VERSION 5.8 ;
BUSBITCHARS "[]" ;
DIVIDERCHAR "/" ;
UNITS
    DATABASE MICRONS 1000 ;
END UNITS

VIA transformer_layer_block_via2_3_1600_480_1_5_320_320
  VIARULE M1M2_PR ;
  CUTSIZE 0.15 0.15 ;
  LAYERS met1 via met2 ;
  CUTSPACING 0.17 0.17 ;
  ENCLOSURE 0.085 0.165 0.055 0.085 ;
  ROWCOL 1 5 ;
END transformer_layer_block_via2_3_1600_480_1_5_320_320

VIA transformer_layer_block_via3_4_1600_480_1_4_400_400
  VIARULE M2M3_PR ;
  CUTSIZE 0.2 0.2 ;
  LAYERS met2 via2 met3 ;
  CUTSPACING 0.2 0.2 ;
  ENCLOSURE 0.04 0.085 0.065 0.065 ;
  ROWCOL 1 4 ;
END transformer_layer_block_via3_4_1600_480_1_4_400_400

VIA transformer_layer_block_via4_5_1600_480_1_4_400_400
  VIARULE M3M4_PR ;
  CUTSIZE 0.2 0.2 ;
  LAYERS met3 via3 met4 ;
  CUTSPACING 0.2 0.2 ;
  ENCLOSURE 0.09 0.06 0.1 0.065 ;
  ROWCOL 1 4 ;
END transformer_layer_block_via4_5_1600_480_1_4_400_400

VIA transformer_layer_block_via5_6_1600_1600_1_1_1600_1600
  VIARULE M4M5_PR ;
  CUTSIZE 0.8 0.8 ;
  LAYERS met4 via4 met5 ;
  CUTSPACING 0.8 0.8 ;
  ENCLOSURE 0.4 0.19 0.31 0.4 ;
END transformer_layer_block_via5_6_1600_1600_1_1_1600_1600

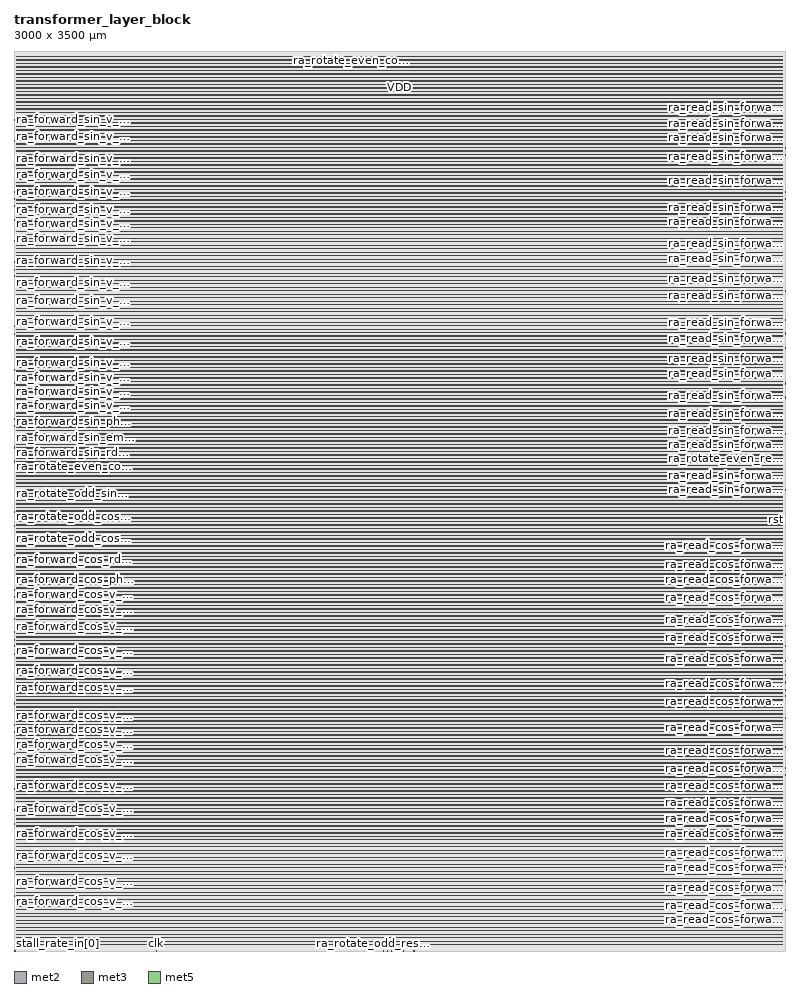
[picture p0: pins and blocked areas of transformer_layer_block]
MACRO transformer_layer_block
  FOREIGN transformer_layer_block 0 0 ;
  CLASS BLOCK ;
  SIZE 3000 BY 3500 ;
  PIN clk
    DIRECTION INPUT ;
    USE SIGNAL ;
    PORT
      LAYER met2 ;
        RECT  554 0 554.14 0.485 ;
    END
  END clk
  PIN ra_forward_cos_empty_out
    DIRECTION OUTPUT ;
    USE SIGNAL ;
    PORT
      LAYER met3 ;
        RECT  0 1504.35 0.8 1504.65 ;
    END
  END ra_forward_cos_empty_out
  PIN ra_forward_cos_phase_in[0]
    DIRECTION INPUT ;
    USE SIGNAL ;
    PORT
      LAYER met3 ;
        RECT  0 1443.15 0.8 1443.45 ;
    END
  END ra_forward_cos_phase_in[0]
  PIN ra_forward_cos_phase_in[1]
    DIRECTION INPUT ;
    USE SIGNAL ;
    PORT
      LAYER met3 ;
        RECT  0 1444.51 0.8 1444.81 ;
    END
  END ra_forward_cos_phase_in[1]
  PIN ra_forward_cos_rden_in
    DIRECTION INPUT ;
    USE SIGNAL ;
    PORT
      LAYER met3 ;
        RECT  0 1520.67 0.8 1520.97 ;
    END
  END ra_forward_cos_rden_in
  PIN ra_forward_cos_rdy_out
    DIRECTION OUTPUT ;
    USE SIGNAL ;
    PORT
      LAYER met3 ;
        RECT  0 1496.19 0.8 1496.49 ;
    END
  END ra_forward_cos_rdy_out
  PIN ra_forward_cos_v_in[0]
    DIRECTION INPUT ;
    USE SIGNAL ;
    PORT
      LAYER met3 ;
        RECT  0 288.51 0.8 288.81 ;
    END
  END ra_forward_cos_v_in[0]
  PIN ra_forward_cos_v_in[100]
    DIRECTION INPUT ;
    USE SIGNAL ;
    PORT
      LAYER met3 ;
        RECT  0 916.83 0.8 917.13 ;
    END
  END ra_forward_cos_v_in[100]
  PIN ra_forward_cos_v_in[101]
    DIRECTION INPUT ;
    USE SIGNAL ;
    PORT
      LAYER met3 ;
        RECT  0 861.07 0.8 861.37 ;
    END
  END ra_forward_cos_v_in[101]
  PIN ra_forward_cos_v_in[102]
    DIRECTION INPUT ;
    USE SIGNAL ;
    PORT
      LAYER met3 ;
        RECT  0 1028.35 0.8 1028.65 ;
    END
  END ra_forward_cos_v_in[102]
  PIN ra_forward_cos_v_in[103]
    DIRECTION INPUT ;
    USE SIGNAL ;
    PORT
      LAYER met3 ;
        RECT  0 1167.07 0.8 1167.37 ;
    END
  END ra_forward_cos_v_in[103]
  PIN ra_forward_cos_v_in[104]
    DIRECTION INPUT ;
    USE SIGNAL ;
    PORT
      LAYER met3 ;
        RECT  0 1417.31 0.8 1417.61 ;
    END
  END ra_forward_cos_v_in[104]
  PIN ra_forward_cos_v_in[105]
    DIRECTION INPUT ;
    USE SIGNAL ;
    PORT
      LAYER met3 ;
        RECT  0 454.43 0.8 454.73 ;
    END
  END ra_forward_cos_v_in[105]
  PIN ra_forward_cos_v_in[106]
    DIRECTION INPUT ;
    USE SIGNAL ;
    PORT
      LAYER met3 ;
        RECT  0 397.31 0.8 397.61 ;
    END
  END ra_forward_cos_v_in[106]
  PIN ra_forward_cos_v_in[107]
    DIRECTION INPUT ;
    USE SIGNAL ;
    PORT
      LAYER met3 ;
        RECT  0 1024.27 0.8 1024.57 ;
    END
  END ra_forward_cos_v_in[107]
  PIN ra_forward_cos_v_in[108]
    DIRECTION INPUT ;
    USE SIGNAL ;
    PORT
      LAYER met3 ;
        RECT  0 224.59 0.8 224.89 ;
    END
  END ra_forward_cos_v_in[108]
  PIN ra_forward_cos_v_in[109]
    DIRECTION INPUT ;
    USE SIGNAL ;
    PORT
      LAYER met3 ;
        RECT  0 923.63 0.8 923.93 ;
    END
  END ra_forward_cos_v_in[109]
  PIN ra_forward_cos_v_in[10]
    DIRECTION INPUT ;
    USE SIGNAL ;
    PORT
      LAYER met3 ;
        RECT  0 270.83 0.8 271.13 ;
    END
  END ra_forward_cos_v_in[10]
  PIN ra_forward_cos_v_in[110]
    DIRECTION INPUT ;
    USE SIGNAL ;
    PORT
      LAYER met3 ;
        RECT  0 1328.91 0.8 1329.21 ;
    END
  END ra_forward_cos_v_in[110]
  PIN ra_forward_cos_v_in[111]
    DIRECTION INPUT ;
    USE SIGNAL ;
    PORT
      LAYER met3 ;
        RECT  0 832.51 0.8 832.81 ;
    END
  END ra_forward_cos_v_in[111]
  PIN ra_forward_cos_v_in[112]
    DIRECTION INPUT ;
    USE SIGNAL ;
    PORT
      LAYER met3 ;
        RECT  0 971.23 0.8 971.53 ;
    END
  END ra_forward_cos_v_in[112]
  PIN ra_forward_cos_v_in[113]
    DIRECTION INPUT ;
    USE SIGNAL ;
    PORT
      LAYER met3 ;
        RECT  0 642.11 0.8 642.41 ;
    END
  END ra_forward_cos_v_in[113]
  PIN ra_forward_cos_v_in[114]
    DIRECTION INPUT ;
    USE SIGNAL ;
    PORT
      LAYER met3 ;
        RECT  0 648.91 0.8 649.21 ;
    END
  END ra_forward_cos_v_in[114]
  PIN ra_forward_cos_v_in[115]
    DIRECTION INPUT ;
    USE SIGNAL ;
    PORT
      LAYER met3 ;
        RECT  0 1262.27 0.8 1262.57 ;
    END
  END ra_forward_cos_v_in[115]
  PIN ra_forward_cos_v_in[116]
    DIRECTION INPUT ;
    USE SIGNAL ;
    PORT
      LAYER met3 ;
        RECT  0 871.95 0.8 872.25 ;
    END
  END ra_forward_cos_v_in[116]
  PIN ra_forward_cos_v_in[117]
    DIRECTION INPUT ;
    USE SIGNAL ;
    PORT
      LAYER met3 ;
        RECT  0 201.47 0.8 201.77 ;
    END
  END ra_forward_cos_v_in[117]
  PIN ra_forward_cos_v_in[118]
    DIRECTION INPUT ;
    USE SIGNAL ;
    PORT
      LAYER met3 ;
        RECT  0 534.67 0.8 534.97 ;
    END
  END ra_forward_cos_v_in[118]
  PIN ra_forward_cos_v_in[119]
    DIRECTION INPUT ;
    USE SIGNAL ;
    PORT
      LAYER met3 ;
        RECT  0 497.95 0.8 498.25 ;
    END
  END ra_forward_cos_v_in[119]
  PIN ra_forward_cos_v_in[11]
    DIRECTION INPUT ;
    USE SIGNAL ;
    PORT
      LAYER met3 ;
        RECT  0 640.75 0.8 641.05 ;
    END
  END ra_forward_cos_v_in[11]
  PIN ra_forward_cos_v_in[120]
    DIRECTION INPUT ;
    USE SIGNAL ;
    PORT
      LAYER met3 ;
        RECT  0 413.63 0.8 413.93 ;
    END
  END ra_forward_cos_v_in[120]
  PIN ra_forward_cos_v_in[121]
    DIRECTION INPUT ;
    USE SIGNAL ;
    PORT
      LAYER met3 ;
        RECT  0 371.47 0.8 371.77 ;
    END
  END ra_forward_cos_v_in[121]
  PIN ra_forward_cos_v_in[122]
    DIRECTION INPUT ;
    USE SIGNAL ;
    PORT
      LAYER met3 ;
        RECT  0 296.67 0.8 296.97 ;
    END
  END ra_forward_cos_v_in[122]
  PIN ra_forward_cos_v_in[123]
    DIRECTION INPUT ;
    USE SIGNAL ;
    PORT
      LAYER met3 ;
        RECT  0 269.47 0.8 269.77 ;
    END
  END ra_forward_cos_v_in[123]
  PIN ra_forward_cos_v_in[124]
    DIRECTION INPUT ;
    USE SIGNAL ;
    PORT
      LAYER met3 ;
        RECT  0 900.51 0.8 900.81 ;
    END
  END ra_forward_cos_v_in[124]
  PIN ra_forward_cos_v_in[125]
    DIRECTION INPUT ;
    USE SIGNAL ;
    PORT
      LAYER met3 ;
        RECT  0 907.31 0.8 907.61 ;
    END
  END ra_forward_cos_v_in[125]
  PIN ra_forward_cos_v_in[126]
    DIRECTION INPUT ;
    USE SIGNAL ;
    PORT
      LAYER met3 ;
        RECT  0 878.75 0.8 879.05 ;
    END
  END ra_forward_cos_v_in[126]
  PIN ra_forward_cos_v_in[127]
    DIRECTION INPUT ;
    USE SIGNAL ;
    PORT
      LAYER met3 ;
        RECT  0 1418.67 0.8 1418.97 ;
    END
  END ra_forward_cos_v_in[127]
  PIN ra_forward_cos_v_in[128]
    DIRECTION INPUT ;
    USE SIGNAL ;
    PORT
      LAYER met3 ;
        RECT  0 1290.83 0.8 1291.13 ;
    END
  END ra_forward_cos_v_in[128]
  PIN ra_forward_cos_v_in[129]
    DIRECTION INPUT ;
    USE SIGNAL ;
    PORT
      LAYER met3 ;
        RECT  0 1002.51 0.8 1002.81 ;
    END
  END ra_forward_cos_v_in[129]
  PIN ra_forward_cos_v_in[12]
    DIRECTION INPUT ;
    USE SIGNAL ;
    PORT
      LAYER met3 ;
        RECT  0 284.43 0.8 284.73 ;
    END
  END ra_forward_cos_v_in[12]
  PIN ra_forward_cos_v_in[130]
    DIRECTION INPUT ;
    USE SIGNAL ;
    PORT
      LAYER met3 ;
        RECT  0 220.51 0.8 220.81 ;
    END
  END ra_forward_cos_v_in[130]
  PIN ra_forward_cos_v_in[131]
    DIRECTION INPUT ;
    USE SIGNAL ;
    PORT
      LAYER met3 ;
        RECT  0 322.51 0.8 322.81 ;
    END
  END ra_forward_cos_v_in[131]
  PIN ra_forward_cos_v_in[132]
    DIRECTION INPUT ;
    USE SIGNAL ;
    PORT
      LAYER met3 ;
        RECT  0 929.07 0.8 929.37 ;
    END
  END ra_forward_cos_v_in[132]
  PIN ra_forward_cos_v_in[133]
    DIRECTION INPUT ;
    USE SIGNAL ;
    PORT
      LAYER met3 ;
        RECT  0 202.83 0.8 203.13 ;
    END
  END ra_forward_cos_v_in[133]
  PIN ra_forward_cos_v_in[134]
    DIRECTION INPUT ;
    USE SIGNAL ;
    PORT
      LAYER met3 ;
        RECT  0 1368.35 0.8 1368.65 ;
    END
  END ra_forward_cos_v_in[134]
  PIN ra_forward_cos_v_in[135]
    DIRECTION INPUT ;
    USE SIGNAL ;
    PORT
      LAYER met3 ;
        RECT  0 455.79 0.8 456.09 ;
    END
  END ra_forward_cos_v_in[135]
  PIN ra_forward_cos_v_in[136]
    DIRECTION INPUT ;
    USE SIGNAL ;
    PORT
      LAYER met3 ;
        RECT  0 423.15 0.8 423.45 ;
    END
  END ra_forward_cos_v_in[136]
  PIN ra_forward_cos_v_in[137]
    DIRECTION INPUT ;
    USE SIGNAL ;
    PORT
      LAYER met3 ;
        RECT  0 973.95 0.8 974.25 ;
    END
  END ra_forward_cos_v_in[137]
  PIN ra_forward_cos_v_in[138]
    DIRECTION INPUT ;
    USE SIGNAL ;
    PORT
      LAYER met3 ;
        RECT  0 1315.31 0.8 1315.61 ;
    END
  END ra_forward_cos_v_in[138]
  PIN ra_forward_cos_v_in[139]
    DIRECTION INPUT ;
    USE SIGNAL ;
    PORT
      LAYER met3 ;
        RECT  0 525.15 0.8 525.45 ;
    END
  END ra_forward_cos_v_in[139]
  PIN ra_forward_cos_v_in[13]
    DIRECTION INPUT ;
    USE SIGNAL ;
    PORT
      LAYER met3 ;
        RECT  0 1224.19 0.8 1224.49 ;
    END
  END ra_forward_cos_v_in[13]
  PIN ra_forward_cos_v_in[140]
    DIRECTION INPUT ;
    USE SIGNAL ;
    PORT
      LAYER met3 ;
        RECT  0 409.55 0.8 409.85 ;
    END
  END ra_forward_cos_v_in[140]
  PIN ra_forward_cos_v_in[141]
    DIRECTION INPUT ;
    USE SIGNAL ;
    PORT
      LAYER met3 ;
        RECT  0 1331.63 0.8 1331.93 ;
    END
  END ra_forward_cos_v_in[141]
  PIN ra_forward_cos_v_in[142]
    DIRECTION INPUT ;
    USE SIGNAL ;
    PORT
      LAYER met3 ;
        RECT  0 1426.83 0.8 1427.13 ;
    END
  END ra_forward_cos_v_in[142]
  PIN ra_forward_cos_v_in[143]
    DIRECTION INPUT ;
    USE SIGNAL ;
    PORT
      LAYER met3 ;
        RECT  0 881.47 0.8 881.77 ;
    END
  END ra_forward_cos_v_in[143]
  PIN ra_forward_cos_v_in[144]
    DIRECTION INPUT ;
    USE SIGNAL ;
    PORT
      LAYER met3 ;
        RECT  0 1398.27 0.8 1398.57 ;
    END
  END ra_forward_cos_v_in[144]
  PIN ra_forward_cos_v_in[145]
    DIRECTION INPUT ;
    USE SIGNAL ;
    PORT
      LAYER met3 ;
        RECT  0 837.95 0.8 838.25 ;
    END
  END ra_forward_cos_v_in[145]
  PIN ra_forward_cos_v_in[146]
    DIRECTION INPUT ;
    USE SIGNAL ;
    PORT
      LAYER met3 ;
        RECT  0 1428.19 0.8 1428.49 ;
    END
  END ra_forward_cos_v_in[146]
  PIN ra_forward_cos_v_in[147]
    DIRECTION INPUT ;
    USE SIGNAL ;
    PORT
      LAYER met3 ;
        RECT  0 1255.47 0.8 1255.77 ;
    END
  END ra_forward_cos_v_in[147]
  PIN ra_forward_cos_v_in[148]
    DIRECTION INPUT ;
    USE SIGNAL ;
    PORT
      LAYER met3 ;
        RECT  0 1217.39 0.8 1217.69 ;
    END
  END ra_forward_cos_v_in[148]
  PIN ra_forward_cos_v_in[149]
    DIRECTION INPUT ;
    USE SIGNAL ;
    PORT
      LAYER met3 ;
        RECT  0 1043.31 0.8 1043.61 ;
    END
  END ra_forward_cos_v_in[149]
  PIN ra_forward_cos_v_in[14]
    DIRECTION INPUT ;
    USE SIGNAL ;
    PORT
      LAYER met3 ;
        RECT  0 552.35 0.8 552.65 ;
    END
  END ra_forward_cos_v_in[14]
  PIN ra_forward_cos_v_in[150]
    DIRECTION INPUT ;
    USE SIGNAL ;
    PORT
      LAYER met3 ;
        RECT  0 1240.51 0.8 1240.81 ;
    END
  END ra_forward_cos_v_in[150]
  PIN ra_forward_cos_v_in[151]
    DIRECTION INPUT ;
    USE SIGNAL ;
    PORT
      LAYER met3 ;
        RECT  0 1421.39 0.8 1421.69 ;
    END
  END ra_forward_cos_v_in[151]
  PIN ra_forward_cos_v_in[152]
    DIRECTION INPUT ;
    USE SIGNAL ;
    PORT
      LAYER met3 ;
        RECT  0 336.11 0.8 336.41 ;
    END
  END ra_forward_cos_v_in[152]
  PIN ra_forward_cos_v_in[153]
    DIRECTION INPUT ;
    USE SIGNAL ;
    PORT
      LAYER met3 ;
        RECT  0 314.35 0.8 314.65 ;
    END
  END ra_forward_cos_v_in[153]
  PIN ra_forward_cos_v_in[154]
    DIRECTION INPUT ;
    USE SIGNAL ;
    PORT
      LAYER met3 ;
        RECT  0 225.95 0.8 226.25 ;
    END
  END ra_forward_cos_v_in[154]
  PIN ra_forward_cos_v_in[155]
    DIRECTION INPUT ;
    USE SIGNAL ;
    PORT
      LAYER met3 ;
        RECT  0 1122.19 0.8 1122.49 ;
    END
  END ra_forward_cos_v_in[155]
  PIN ra_forward_cos_v_in[156]
    DIRECTION INPUT ;
    USE SIGNAL ;
    PORT
      LAYER met3 ;
        RECT  0 1199.71 0.8 1200.01 ;
    END
  END ra_forward_cos_v_in[156]
  PIN ra_forward_cos_v_in[157]
    DIRECTION INPUT ;
    USE SIGNAL ;
    PORT
      LAYER met3 ;
        RECT  0 703.31 0.8 703.61 ;
    END
  END ra_forward_cos_v_in[157]
  PIN ra_forward_cos_v_in[158]
    DIRECTION INPUT ;
    USE SIGNAL ;
    PORT
      LAYER met3 ;
        RECT  0 999.79 0.8 1000.09 ;
    END
  END ra_forward_cos_v_in[158]
  PIN ra_forward_cos_v_in[159]
    DIRECTION INPUT ;
    USE SIGNAL ;
    PORT
      LAYER met3 ;
        RECT  0 1377.87 0.8 1378.17 ;
    END
  END ra_forward_cos_v_in[159]
  PIN ra_forward_cos_v_in[15]
    DIRECTION INPUT ;
    USE SIGNAL ;
    PORT
      LAYER met3 ;
        RECT  0 1312.59 0.8 1312.89 ;
    END
  END ra_forward_cos_v_in[15]
  PIN ra_forward_cos_v_in[160]
    DIRECTION INPUT ;
    USE SIGNAL ;
    PORT
      LAYER met3 ;
        RECT  0 744.11 0.8 744.41 ;
    END
  END ra_forward_cos_v_in[160]
  PIN ra_forward_cos_v_in[161]
    DIRECTION INPUT ;
    USE SIGNAL ;
    PORT
      LAYER met3 ;
        RECT  0 439.47 0.8 439.77 ;
    END
  END ra_forward_cos_v_in[161]
  PIN ra_forward_cos_v_in[162]
    DIRECTION INPUT ;
    USE SIGNAL ;
    PORT
      LAYER met3 ;
        RECT  0 937.23 0.8 937.53 ;
    END
  END ra_forward_cos_v_in[162]
  PIN ra_forward_cos_v_in[163]
    DIRECTION INPUT ;
    USE SIGNAL ;
    PORT
      LAYER met3 ;
        RECT  0 221.87 0.8 222.17 ;
    END
  END ra_forward_cos_v_in[163]
  PIN ra_forward_cos_v_in[164]
    DIRECTION INPUT ;
    USE SIGNAL ;
    PORT
      LAYER met3 ;
        RECT  0 1101.79 0.8 1102.09 ;
    END
  END ra_forward_cos_v_in[164]
  PIN ra_forward_cos_v_in[165]
    DIRECTION INPUT ;
    USE SIGNAL ;
    PORT
      LAYER met3 ;
        RECT  0 1293.55 0.8 1293.85 ;
    END
  END ra_forward_cos_v_in[165]
  PIN ra_forward_cos_v_in[166]
    DIRECTION INPUT ;
    USE SIGNAL ;
    PORT
      LAYER met3 ;
        RECT  0 1103.15 0.8 1103.45 ;
    END
  END ra_forward_cos_v_in[166]
  PIN ra_forward_cos_v_in[167]
    DIRECTION INPUT ;
    USE SIGNAL ;
    PORT
      LAYER met3 ;
        RECT  0 1186.11 0.8 1186.41 ;
    END
  END ra_forward_cos_v_in[167]
  PIN ra_forward_cos_v_in[168]
    DIRECTION INPUT ;
    USE SIGNAL ;
    PORT
      LAYER met3 ;
        RECT  0 204.19 0.8 204.49 ;
    END
  END ra_forward_cos_v_in[168]
  PIN ra_forward_cos_v_in[169]
    DIRECTION INPUT ;
    USE SIGNAL ;
    PORT
      LAYER met3 ;
        RECT  0 1383.31 0.8 1383.61 ;
    END
  END ra_forward_cos_v_in[169]
  PIN ra_forward_cos_v_in[16]
    DIRECTION INPUT ;
    USE SIGNAL ;
    PORT
      LAYER met3 ;
        RECT  0 623.07 0.8 623.37 ;
    END
  END ra_forward_cos_v_in[16]
  PIN ra_forward_cos_v_in[170]
    DIRECTION INPUT ;
    USE SIGNAL ;
    PORT
      LAYER met3 ;
        RECT  0 414.99 0.8 415.29 ;
    END
  END ra_forward_cos_v_in[170]
  PIN ra_forward_cos_v_in[171]
    DIRECTION INPUT ;
    USE SIGNAL ;
    PORT
      LAYER met3 ;
        RECT  0 258.59 0.8 258.89 ;
    END
  END ra_forward_cos_v_in[171]
  PIN ra_forward_cos_v_in[172]
    DIRECTION INPUT ;
    USE SIGNAL ;
    PORT
      LAYER met3 ;
        RECT  0 208.27 0.8 208.57 ;
    END
  END ra_forward_cos_v_in[172]
  PIN ra_forward_cos_v_in[173]
    DIRECTION INPUT ;
    USE SIGNAL ;
    PORT
      LAYER met3 ;
        RECT  0 1071.87 0.8 1072.17 ;
    END
  END ra_forward_cos_v_in[173]
  PIN ra_forward_cos_v_in[174]
    DIRECTION INPUT ;
    USE SIGNAL ;
    PORT
      LAYER met3 ;
        RECT  0 492.51 0.8 492.81 ;
    END
  END ra_forward_cos_v_in[174]
  PIN ra_forward_cos_v_in[175]
    DIRECTION INPUT ;
    USE SIGNAL ;
    PORT
      LAYER met3 ;
        RECT  0 1356.11 0.8 1356.41 ;
    END
  END ra_forward_cos_v_in[175]
  PIN ra_forward_cos_v_in[176]
    DIRECTION INPUT ;
    USE SIGNAL ;
    PORT
      LAYER met3 ;
        RECT  0 1048.75 0.8 1049.05 ;
    END
  END ra_forward_cos_v_in[176]
  PIN ra_forward_cos_v_in[177]
    DIRECTION INPUT ;
    USE SIGNAL ;
    PORT
      LAYER met3 ;
        RECT  0 1282.67 0.8 1282.97 ;
    END
  END ra_forward_cos_v_in[177]
  PIN ra_forward_cos_v_in[178]
    DIRECTION INPUT ;
    USE SIGNAL ;
    PORT
      LAYER met3 ;
        RECT  0 1092.27 0.8 1092.57 ;
    END
  END ra_forward_cos_v_in[178]
  PIN ra_forward_cos_v_in[179]
    DIRECTION INPUT ;
    USE SIGNAL ;
    PORT
      LAYER met3 ;
        RECT  0 591.79 0.8 592.09 ;
    END
  END ra_forward_cos_v_in[179]
  PIN ra_forward_cos_v_in[17]
    DIRECTION INPUT ;
    USE SIGNAL ;
    PORT
      LAYER met3 ;
        RECT  0 689.71 0.8 690.01 ;
    END
  END ra_forward_cos_v_in[17]
  PIN ra_forward_cos_v_in[180]
    DIRECTION INPUT ;
    USE SIGNAL ;
    PORT
      LAYER met3 ;
        RECT  0 935.87 0.8 936.17 ;
    END
  END ra_forward_cos_v_in[180]
  PIN ra_forward_cos_v_in[181]
    DIRECTION INPUT ;
    USE SIGNAL ;
    PORT
      LAYER met3 ;
        RECT  0 417.71 0.8 418.01 ;
    END
  END ra_forward_cos_v_in[181]
  PIN ra_forward_cos_v_in[182]
    DIRECTION INPUT ;
    USE SIGNAL ;
    PORT
      LAYER met3 ;
        RECT  0 776.75 0.8 777.05 ;
    END
  END ra_forward_cos_v_in[182]
  PIN ra_forward_cos_v_in[183]
    DIRECTION INPUT ;
    USE SIGNAL ;
    PORT
      LAYER met3 ;
        RECT  0 618.99 0.8 619.29 ;
    END
  END ra_forward_cos_v_in[183]
  PIN ra_forward_cos_v_in[184]
    DIRECTION INPUT ;
    USE SIGNAL ;
    PORT
      LAYER met3 ;
        RECT  0 829.79 0.8 830.09 ;
    END
  END ra_forward_cos_v_in[184]
  PIN ra_forward_cos_v_in[185]
    DIRECTION INPUT ;
    USE SIGNAL ;
    PORT
      LAYER met3 ;
        RECT  0 315.71 0.8 316.01 ;
    END
  END ra_forward_cos_v_in[185]
  PIN ra_forward_cos_v_in[186]
    DIRECTION INPUT ;
    USE SIGNAL ;
    PORT
      LAYER met3 ;
        RECT  0 1352.03 0.8 1352.33 ;
    END
  END ra_forward_cos_v_in[186]
  PIN ra_forward_cos_v_in[187]
    DIRECTION INPUT ;
    USE SIGNAL ;
    PORT
      LAYER met3 ;
        RECT  0 376.91 0.8 377.21 ;
    END
  END ra_forward_cos_v_in[187]
  PIN ra_forward_cos_v_in[188]
    DIRECTION INPUT ;
    USE SIGNAL ;
    PORT
      LAYER met3 ;
        RECT  0 767.23 0.8 767.53 ;
    END
  END ra_forward_cos_v_in[188]
  PIN ra_forward_cos_v_in[189]
    DIRECTION INPUT ;
    USE SIGNAL ;
    PORT
      LAYER met3 ;
        RECT  0 662.51 0.8 662.81 ;
    END
  END ra_forward_cos_v_in[189]
  PIN ra_forward_cos_v_in[18]
    DIRECTION INPUT ;
    USE SIGNAL ;
    PORT
      LAYER met3 ;
        RECT  0 1201.07 0.8 1201.37 ;
    END
  END ra_forward_cos_v_in[18]
  PIN ra_forward_cos_v_in[190]
    DIRECTION INPUT ;
    USE SIGNAL ;
    PORT
      LAYER met3 ;
        RECT  0 1339.79 0.8 1340.09 ;
    END
  END ra_forward_cos_v_in[190]
  PIN ra_forward_cos_v_in[191]
    DIRECTION INPUT ;
    USE SIGNAL ;
    PORT
      LAYER met3 ;
        RECT  0 549.63 0.8 549.93 ;
    END
  END ra_forward_cos_v_in[191]
  PIN ra_forward_cos_v_in[192]
    DIRECTION INPUT ;
    USE SIGNAL ;
    PORT
      LAYER met3 ;
        RECT  0 512.91 0.8 513.21 ;
    END
  END ra_forward_cos_v_in[192]
  PIN ra_forward_cos_v_in[193]
    DIRECTION INPUT ;
    USE SIGNAL ;
    PORT
      LAYER met3 ;
        RECT  0 1409.15 0.8 1409.45 ;
    END
  END ra_forward_cos_v_in[193]
  PIN ra_forward_cos_v_in[194]
    DIRECTION INPUT ;
    USE SIGNAL ;
    PORT
      LAYER met3 ;
        RECT  0 976.67 0.8 976.97 ;
    END
  END ra_forward_cos_v_in[194]
  PIN ra_forward_cos_v_in[195]
    DIRECTION INPUT ;
    USE SIGNAL ;
    PORT
      LAYER met3 ;
        RECT  0 1387.39 0.8 1387.69 ;
    END
  END ra_forward_cos_v_in[195]
  PIN ra_forward_cos_v_in[196]
    DIRECTION INPUT ;
    USE SIGNAL ;
    PORT
      LAYER met3 ;
        RECT  0 205.55 0.8 205.85 ;
    END
  END ra_forward_cos_v_in[196]
  PIN ra_forward_cos_v_in[197]
    DIRECTION INPUT ;
    USE SIGNAL ;
    PORT
      LAYER met3 ;
        RECT  0 1436.35 0.8 1436.65 ;
    END
  END ra_forward_cos_v_in[197]
  PIN ra_forward_cos_v_in[198]
    DIRECTION INPUT ;
    USE SIGNAL ;
    PORT
      LAYER met3 ;
        RECT  0 1012.03 0.8 1012.33 ;
    END
  END ra_forward_cos_v_in[198]
  PIN ra_forward_cos_v_in[199]
    DIRECTION INPUT ;
    USE SIGNAL ;
    PORT
      LAYER met3 ;
        RECT  0 378.27 0.8 378.57 ;
    END
  END ra_forward_cos_v_in[199]
  PIN ra_forward_cos_v_in[19]
    DIRECTION INPUT ;
    USE SIGNAL ;
    PORT
      LAYER met3 ;
        RECT  0 629.87 0.8 630.17 ;
    END
  END ra_forward_cos_v_in[19]
  PIN ra_forward_cos_v_in[1]
    DIRECTION INPUT ;
    USE SIGNAL ;
    PORT
      LAYER met3 ;
        RECT  0 1286.75 0.8 1287.05 ;
    END
  END ra_forward_cos_v_in[1]
  PIN ra_forward_cos_v_in[200]
    DIRECTION INPUT ;
    USE SIGNAL ;
    PORT
      LAYER met3 ;
        RECT  0 780.83 0.8 781.13 ;
    END
  END ra_forward_cos_v_in[200]
  PIN ra_forward_cos_v_in[201]
    DIRECTION INPUT ;
    USE SIGNAL ;
    PORT
      LAYER met3 ;
        RECT  0 729.15 0.8 729.45 ;
    END
  END ra_forward_cos_v_in[201]
  PIN ra_forward_cos_v_in[202]
    DIRECTION INPUT ;
    USE SIGNAL ;
    PORT
      LAYER met3 ;
        RECT  0 1175.23 0.8 1175.53 ;
    END
  END ra_forward_cos_v_in[202]
  PIN ra_forward_cos_v_in[203]
    DIRECTION INPUT ;
    USE SIGNAL ;
    PORT
      LAYER met3 ;
        RECT  0 319.79 0.8 320.09 ;
    END
  END ra_forward_cos_v_in[203]
  PIN ra_forward_cos_v_in[204]
    DIRECTION INPUT ;
    USE SIGNAL ;
    PORT
      LAYER met3 ;
        RECT  0 206.91 0.8 207.21 ;
    END
  END ra_forward_cos_v_in[204]
  PIN ra_forward_cos_v_in[205]
    DIRECTION INPUT ;
    USE SIGNAL ;
    PORT
      LAYER met3 ;
        RECT  0 485.71 0.8 486.01 ;
    END
  END ra_forward_cos_v_in[205]
  PIN ra_forward_cos_v_in[206]
    DIRECTION INPUT ;
    USE SIGNAL ;
    PORT
      LAYER met3 ;
        RECT  0 546.91 0.8 547.21 ;
    END
  END ra_forward_cos_v_in[206]
  PIN ra_forward_cos_v_in[207]
    DIRECTION INPUT ;
    USE SIGNAL ;
    PORT
      LAYER met3 ;
        RECT  0 636.67 0.8 636.97 ;
    END
  END ra_forward_cos_v_in[207]
  PIN ra_forward_cos_v_in[208]
    DIRECTION INPUT ;
    USE SIGNAL ;
    PORT
      LAYER met3 ;
        RECT  0 859.71 0.8 860.01 ;
    END
  END ra_forward_cos_v_in[208]
  PIN ra_forward_cos_v_in[209]
    DIRECTION INPUT ;
    USE SIGNAL ;
    PORT
      LAYER met3 ;
        RECT  0 444.91 0.8 445.21 ;
    END
  END ra_forward_cos_v_in[209]
  PIN ra_forward_cos_v_in[20]
    DIRECTION INPUT ;
    USE SIGNAL ;
    PORT
      LAYER met3 ;
        RECT  0 682.91 0.8 683.21 ;
    END
  END ra_forward_cos_v_in[20]
  PIN ra_forward_cos_v_in[210]
    DIRECTION INPUT ;
    USE SIGNAL ;
    PORT
      LAYER met3 ;
        RECT  0 1078.67 0.8 1078.97 ;
    END
  END ra_forward_cos_v_in[210]
  PIN ra_forward_cos_v_in[211]
    DIRECTION INPUT ;
    USE SIGNAL ;
    PORT
      LAYER met3 ;
        RECT  0 783.55 0.8 783.85 ;
    END
  END ra_forward_cos_v_in[211]
  PIN ra_forward_cos_v_in[212]
    DIRECTION INPUT ;
    USE SIGNAL ;
    PORT
      LAYER met3 ;
        RECT  0 605.39 0.8 605.69 ;
    END
  END ra_forward_cos_v_in[212]
  PIN ra_forward_cos_v_in[213]
    DIRECTION INPUT ;
    USE SIGNAL ;
    PORT
      LAYER met3 ;
        RECT  0 608.11 0.8 608.41 ;
    END
  END ra_forward_cos_v_in[213]
  PIN ra_forward_cos_v_in[214]
    DIRECTION INPUT ;
    USE SIGNAL ;
    PORT
      LAYER met3 ;
        RECT  0 697.87 0.8 698.17 ;
    END
  END ra_forward_cos_v_in[214]
  PIN ra_forward_cos_v_in[215]
    DIRECTION INPUT ;
    USE SIGNAL ;
    PORT
      LAYER met3 ;
        RECT  0 831.15 0.8 831.45 ;
    END
  END ra_forward_cos_v_in[215]
  PIN ra_forward_cos_v_in[216]
    DIRECTION INPUT ;
    USE SIGNAL ;
    PORT
      LAYER met3 ;
        RECT  0 882.83 0.8 883.13 ;
    END
  END ra_forward_cos_v_in[216]
  PIN ra_forward_cos_v_in[217]
    DIRECTION INPUT ;
    USE SIGNAL ;
    PORT
      LAYER met3 ;
        RECT  0 874.67 0.8 874.97 ;
    END
  END ra_forward_cos_v_in[217]
  PIN ra_forward_cos_v_in[218]
    DIRECTION INPUT ;
    USE SIGNAL ;
    PORT
      LAYER met3 ;
        RECT  0 526.51 0.8 526.81 ;
    END
  END ra_forward_cos_v_in[218]
  PIN ra_forward_cos_v_in[219]
    DIRECTION INPUT ;
    USE SIGNAL ;
    PORT
      LAYER met3 ;
        RECT  0 210.99 0.8 211.29 ;
    END
  END ra_forward_cos_v_in[219]
  PIN ra_forward_cos_v_in[21]
    DIRECTION INPUT ;
    USE SIGNAL ;
    PORT
      LAYER met3 ;
        RECT  0 606.75 0.8 607.05 ;
    END
  END ra_forward_cos_v_in[21]
  PIN ra_forward_cos_v_in[220]
    DIRECTION INPUT ;
    USE SIGNAL ;
    PORT
      LAYER met3 ;
        RECT  0 808.03 0.8 808.33 ;
    END
  END ra_forward_cos_v_in[220]
  PIN ra_forward_cos_v_in[221]
    DIRECTION INPUT ;
    USE SIGNAL ;
    PORT
      LAYER met3 ;
        RECT  0 321.15 0.8 321.45 ;
    END
  END ra_forward_cos_v_in[221]
  PIN ra_forward_cos_v_in[222]
    DIRECTION INPUT ;
    USE SIGNAL ;
    PORT
      LAYER met3 ;
        RECT  0 292.59 0.8 292.89 ;
    END
  END ra_forward_cos_v_in[222]
  PIN ra_forward_cos_v_in[223]
    DIRECTION INPUT ;
    USE SIGNAL ;
    PORT
      LAYER met3 ;
        RECT  0 548.27 0.8 548.57 ;
    END
  END ra_forward_cos_v_in[223]
  PIN ra_forward_cos_v_in[224]
    DIRECTION INPUT ;
    USE SIGNAL ;
    PORT
      LAYER met3 ;
        RECT  0 760.43 0.8 760.73 ;
    END
  END ra_forward_cos_v_in[224]
  PIN ra_forward_cos_v_in[225]
    DIRECTION INPUT ;
    USE SIGNAL ;
    PORT
      LAYER met3 ;
        RECT  0 1164.35 0.8 1164.65 ;
    END
  END ra_forward_cos_v_in[225]
  PIN ra_forward_cos_v_in[226]
    DIRECTION INPUT ;
    USE SIGNAL ;
    PORT
      LAYER met3 ;
        RECT  0 965.79 0.8 966.09 ;
    END
  END ra_forward_cos_v_in[226]
  PIN ra_forward_cos_v_in[227]
    DIRECTION INPUT ;
    USE SIGNAL ;
    PORT
      LAYER met3 ;
        RECT  0 1376.51 0.8 1376.81 ;
    END
  END ra_forward_cos_v_in[227]
  PIN ra_forward_cos_v_in[228]
    DIRECTION INPUT ;
    USE SIGNAL ;
    PORT
      LAYER met3 ;
        RECT  0 209.63 0.8 209.93 ;
    END
  END ra_forward_cos_v_in[228]
  PIN ra_forward_cos_v_in[229]
    DIRECTION INPUT ;
    USE SIGNAL ;
    PORT
      LAYER met3 ;
        RECT  0 357.87 0.8 358.17 ;
    END
  END ra_forward_cos_v_in[229]
  PIN ra_forward_cos_v_in[22]
    DIRECTION INPUT ;
    USE SIGNAL ;
    PORT
      LAYER met3 ;
        RECT  0 1346.59 0.8 1346.89 ;
    END
  END ra_forward_cos_v_in[22]
  PIN ra_forward_cos_v_in[230]
    DIRECTION INPUT ;
    USE SIGNAL ;
    PORT
      LAYER met3 ;
        RECT  0 1429.55 0.8 1429.85 ;
    END
  END ra_forward_cos_v_in[230]
  PIN ra_forward_cos_v_in[231]
    DIRECTION INPUT ;
    USE SIGNAL ;
    PORT
      LAYER met3 ;
        RECT  0 330.67 0.8 330.97 ;
    END
  END ra_forward_cos_v_in[231]
  PIN ra_forward_cos_v_in[232]
    DIRECTION INPUT ;
    USE SIGNAL ;
    PORT
      LAYER met3 ;
        RECT  0 255.87 0.8 256.17 ;
    END
  END ra_forward_cos_v_in[232]
  PIN ra_forward_cos_v_in[233]
    DIRECTION INPUT ;
    USE SIGNAL ;
    PORT
      LAYER met3 ;
        RECT  0 765.87 0.8 766.17 ;
    END
  END ra_forward_cos_v_in[233]
  PIN ra_forward_cos_v_in[234]
    DIRECTION INPUT ;
    USE SIGNAL ;
    PORT
      LAYER met3 ;
        RECT  0 223.23 0.8 223.53 ;
    END
  END ra_forward_cos_v_in[234]
  PIN ra_forward_cos_v_in[235]
    DIRECTION INPUT ;
    USE SIGNAL ;
    PORT
      LAYER met3 ;
        RECT  0 289.87 0.8 290.17 ;
    END
  END ra_forward_cos_v_in[235]
  PIN ra_forward_cos_v_in[236]
    DIRECTION INPUT ;
    USE SIGNAL ;
    PORT
      LAYER met3 ;
        RECT  0 784.91 0.8 785.21 ;
    END
  END ra_forward_cos_v_in[236]
  PIN ra_forward_cos_v_in[237]
    DIRECTION INPUT ;
    USE SIGNAL ;
    PORT
      LAYER met3 ;
        RECT  0 730.51 0.8 730.81 ;
    END
  END ra_forward_cos_v_in[237]
  PIN ra_forward_cos_v_in[238]
    DIRECTION INPUT ;
    USE SIGNAL ;
    PORT
      LAYER met3 ;
        RECT  0 1350.67 0.8 1350.97 ;
    END
  END ra_forward_cos_v_in[238]
  PIN ra_forward_cos_v_in[239]
    DIRECTION INPUT ;
    USE SIGNAL ;
    PORT
      LAYER met3 ;
        RECT  0 960.35 0.8 960.65 ;
    END
  END ra_forward_cos_v_in[239]
  PIN ra_forward_cos_v_in[23]
    DIRECTION INPUT ;
    USE SIGNAL ;
    PORT
      LAYER met3 ;
        RECT  0 1403.71 0.8 1404.01 ;
    END
  END ra_forward_cos_v_in[23]
  PIN ra_forward_cos_v_in[240]
    DIRECTION INPUT ;
    USE SIGNAL ;
    PORT
      LAYER met3 ;
        RECT  0 386.43 0.8 386.73 ;
    END
  END ra_forward_cos_v_in[240]
  PIN ra_forward_cos_v_in[241]
    DIRECTION INPUT ;
    USE SIGNAL ;
    PORT
      LAYER met3 ;
        RECT  0 522.43 0.8 522.73 ;
    END
  END ra_forward_cos_v_in[241]
  PIN ra_forward_cos_v_in[242]
    DIRECTION INPUT ;
    USE SIGNAL ;
    PORT
      LAYER met3 ;
        RECT  0 1420.03 0.8 1420.33 ;
    END
  END ra_forward_cos_v_in[242]
  PIN ra_forward_cos_v_in[243]
    DIRECTION INPUT ;
    USE SIGNAL ;
    PORT
      LAYER met3 ;
        RECT  0 1096.35 0.8 1096.65 ;
    END
  END ra_forward_cos_v_in[243]
  PIN ra_forward_cos_v_in[244]
    DIRECTION INPUT ;
    USE SIGNAL ;
    PORT
      LAYER met3 ;
        RECT  0 538.75 0.8 539.05 ;
    END
  END ra_forward_cos_v_in[244]
  PIN ra_forward_cos_v_in[245]
    DIRECTION INPUT ;
    USE SIGNAL ;
    PORT
      LAYER met3 ;
        RECT  0 701.95 0.8 702.25 ;
    END
  END ra_forward_cos_v_in[245]
  PIN ra_forward_cos_v_in[246]
    DIRECTION INPUT ;
    USE SIGNAL ;
    PORT
      LAYER met3 ;
        RECT  0 764.51 0.8 764.81 ;
    END
  END ra_forward_cos_v_in[246]
  PIN ra_forward_cos_v_in[247]
    DIRECTION INPUT ;
    USE SIGNAL ;
    PORT
      LAYER met3 ;
        RECT  0 1244.59 0.8 1244.89 ;
    END
  END ra_forward_cos_v_in[247]
  PIN ra_forward_cos_v_in[248]
    DIRECTION INPUT ;
    USE SIGNAL ;
    PORT
      LAYER met3 ;
        RECT  0 213.71 0.8 214.01 ;
    END
  END ra_forward_cos_v_in[248]
  PIN ra_forward_cos_v_in[249]
    DIRECTION INPUT ;
    USE SIGNAL ;
    PORT
      LAYER met3 ;
        RECT  0 257.23 0.8 257.53 ;
    END
  END ra_forward_cos_v_in[249]
  PIN ra_forward_cos_v_in[24]
    DIRECTION INPUT ;
    USE SIGNAL ;
    PORT
      LAYER met3 ;
        RECT  0 318.43 0.8 318.73 ;
    END
  END ra_forward_cos_v_in[24]
  PIN ra_forward_cos_v_in[250]
    DIRECTION INPUT ;
    USE SIGNAL ;
    PORT
      LAYER met3 ;
        RECT  0 1120.83 0.8 1121.13 ;
    END
  END ra_forward_cos_v_in[250]
  PIN ra_forward_cos_v_in[251]
    DIRECTION INPUT ;
    USE SIGNAL ;
    PORT
      LAYER met3 ;
        RECT  0 632.59 0.8 632.89 ;
    END
  END ra_forward_cos_v_in[251]
  PIN ra_forward_cos_v_in[252]
    DIRECTION INPUT ;
    USE SIGNAL ;
    PORT
      LAYER met3 ;
        RECT  0 1162.99 0.8 1163.29 ;
    END
  END ra_forward_cos_v_in[252]
  PIN ra_forward_cos_v_in[253]
    DIRECTION INPUT ;
    USE SIGNAL ;
    PORT
      LAYER met3 ;
        RECT  0 212.35 0.8 212.65 ;
    END
  END ra_forward_cos_v_in[253]
  PIN ra_forward_cos_v_in[254]
    DIRECTION INPUT ;
    USE SIGNAL ;
    PORT
      LAYER met3 ;
        RECT  0 888.27 0.8 888.57 ;
    END
  END ra_forward_cos_v_in[254]
  PIN ra_forward_cos_v_in[255]
    DIRECTION INPUT ;
    USE SIGNAL ;
    PORT
      LAYER met3 ;
        RECT  0 234.11 0.8 234.41 ;
    END
  END ra_forward_cos_v_in[255]
  PIN ra_forward_cos_v_in[25]
    DIRECTION INPUT ;
    USE SIGNAL ;
    PORT
      LAYER met3 ;
        RECT  0 828.43 0.8 828.73 ;
    END
  END ra_forward_cos_v_in[25]
  PIN ra_forward_cos_v_in[26]
    DIRECTION INPUT ;
    USE SIGNAL ;
    PORT
      LAYER met3 ;
        RECT  0 232.75 0.8 233.05 ;
    END
  END ra_forward_cos_v_in[26]
  PIN ra_forward_cos_v_in[27]
    DIRECTION INPUT ;
    USE SIGNAL ;
    PORT
      LAYER met3 ;
        RECT  0 337.47 0.8 337.77 ;
    END
  END ra_forward_cos_v_in[27]
  PIN ra_forward_cos_v_in[28]
    DIRECTION INPUT ;
    USE SIGNAL ;
    PORT
      LAYER met3 ;
        RECT  0 934.51 0.8 934.81 ;
    END
  END ra_forward_cos_v_in[28]
  PIN ra_forward_cos_v_in[29]
    DIRECTION INPUT ;
    USE SIGNAL ;
    PORT
      LAYER met3 ;
        RECT  0 227.31 0.8 227.61 ;
    END
  END ra_forward_cos_v_in[29]
  PIN ra_forward_cos_v_in[2]
    DIRECTION INPUT ;
    USE SIGNAL ;
    PORT
      LAYER met3 ;
        RECT  0 748.19 0.8 748.49 ;
    END
  END ra_forward_cos_v_in[2]
  PIN ra_forward_cos_v_in[30]
    DIRECTION INPUT ;
    USE SIGNAL ;
    PORT
      LAYER met3 ;
        RECT  0 1190.19 0.8 1190.49 ;
    END
  END ra_forward_cos_v_in[30]
  PIN ra_forward_cos_v_in[31]
    DIRECTION INPUT ;
    USE SIGNAL ;
    PORT
      LAYER met3 ;
        RECT  0 876.03 0.8 876.33 ;
    END
  END ra_forward_cos_v_in[31]
  PIN ra_forward_cos_v_in[32]
    DIRECTION INPUT ;
    USE SIGNAL ;
    PORT
      LAYER met3 ;
        RECT  0 1128.99 0.8 1129.29 ;
    END
  END ra_forward_cos_v_in[32]
  PIN ra_forward_cos_v_in[33]
    DIRECTION INPUT ;
    USE SIGNAL ;
    PORT
      LAYER met3 ;
        RECT  0 631.23 0.8 631.53 ;
    END
  END ra_forward_cos_v_in[33]
  PIN ra_forward_cos_v_in[34]
    DIRECTION INPUT ;
    USE SIGNAL ;
    PORT
      LAYER met3 ;
        RECT  0 964.43 0.8 964.73 ;
    END
  END ra_forward_cos_v_in[34]
  PIN ra_forward_cos_v_in[35]
    DIRECTION INPUT ;
    USE SIGNAL ;
    PORT
      LAYER met3 ;
        RECT  0 1031.07 0.8 1031.37 ;
    END
  END ra_forward_cos_v_in[35]
  PIN ra_forward_cos_v_in[36]
    DIRECTION INPUT ;
    USE SIGNAL ;
    PORT
      LAYER met3 ;
        RECT  0 617.63 0.8 617.93 ;
    END
  END ra_forward_cos_v_in[36]
  PIN ra_forward_cos_v_in[37]
    DIRECTION INPUT ;
    USE SIGNAL ;
    PORT
      LAYER met3 ;
        RECT  0 806.67 0.8 806.97 ;
    END
  END ra_forward_cos_v_in[37]
  PIN ra_forward_cos_v_in[38]
    DIRECTION INPUT ;
    USE SIGNAL ;
    PORT
      LAYER met3 ;
        RECT  0 360.59 0.8 360.89 ;
    END
  END ra_forward_cos_v_in[38]
  PIN ra_forward_cos_v_in[39]
    DIRECTION INPUT ;
    USE SIGNAL ;
    PORT
      LAYER met3 ;
        RECT  0 740.03 0.8 740.33 ;
    END
  END ra_forward_cos_v_in[39]
  PIN ra_forward_cos_v_in[3]
    DIRECTION INPUT ;
    USE SIGNAL ;
    PORT
      LAYER met3 ;
        RECT  0 527.87 0.8 528.17 ;
    END
  END ra_forward_cos_v_in[3]
  PIN ra_forward_cos_v_in[40]
    DIRECTION INPUT ;
    USE SIGNAL ;
    PORT
      LAYER met3 ;
        RECT  0 402.75 0.8 403.05 ;
    END
  END ra_forward_cos_v_in[40]
  PIN ra_forward_cos_v_in[41]
    DIRECTION INPUT ;
    USE SIGNAL ;
    PORT
      LAYER met3 ;
        RECT  0 1422.75 0.8 1423.05 ;
    END
  END ra_forward_cos_v_in[41]
  PIN ra_forward_cos_v_in[42]
    DIRECTION INPUT ;
    USE SIGNAL ;
    PORT
      LAYER met3 ;
        RECT  0 374.19 0.8 374.49 ;
    END
  END ra_forward_cos_v_in[42]
  PIN ra_forward_cos_v_in[43]
    DIRECTION INPUT ;
    USE SIGNAL ;
    PORT
      LAYER met3 ;
        RECT  0 493.87 0.8 494.17 ;
    END
  END ra_forward_cos_v_in[43]
  PIN ra_forward_cos_v_in[44]
    DIRECTION INPUT ;
    USE SIGNAL ;
    PORT
      LAYER met3 ;
        RECT  0 613.55 0.8 613.85 ;
    END
  END ra_forward_cos_v_in[44]
  PIN ra_forward_cos_v_in[45]
    DIRECTION INPUT ;
    USE SIGNAL ;
    PORT
      LAYER met3 ;
        RECT  0 514.27 0.8 514.57 ;
    END
  END ra_forward_cos_v_in[45]
  PIN ra_forward_cos_v_in[46]
    DIRECTION INPUT ;
    USE SIGNAL ;
    PORT
      LAYER met3 ;
        RECT  0 217.79 0.8 218.09 ;
    END
  END ra_forward_cos_v_in[46]
  PIN ra_forward_cos_v_in[47]
    DIRECTION INPUT ;
    USE SIGNAL ;
    PORT
      LAYER met3 ;
        RECT  0 1133.07 0.8 1133.37 ;
    END
  END ra_forward_cos_v_in[47]
  PIN ra_forward_cos_v_in[48]
    DIRECTION INPUT ;
    USE SIGNAL ;
    PORT
      LAYER met3 ;
        RECT  0 379.63 0.8 379.93 ;
    END
  END ra_forward_cos_v_in[48]
  PIN ra_forward_cos_v_in[49]
    DIRECTION INPUT ;
    USE SIGNAL ;
    PORT
      LAYER met3 ;
        RECT  0 372.83 0.8 373.13 ;
    END
  END ra_forward_cos_v_in[49]
  PIN ra_forward_cos_v_in[4]
    DIRECTION INPUT ;
    USE SIGNAL ;
    PORT
      LAYER met3 ;
        RECT  0 550.99 0.8 551.29 ;
    END
  END ra_forward_cos_v_in[4]
  PIN ra_forward_cos_v_in[50]
    DIRECTION INPUT ;
    USE SIGNAL ;
    PORT
      LAYER met3 ;
        RECT  0 851.55 0.8 851.85 ;
    END
  END ra_forward_cos_v_in[50]
  PIN ra_forward_cos_v_in[51]
    DIRECTION INPUT ;
    USE SIGNAL ;
    PORT
      LAYER met3 ;
        RECT  0 261.31 0.8 261.61 ;
    END
  END ra_forward_cos_v_in[51]
  PIN ra_forward_cos_v_in[52]
    DIRECTION INPUT ;
    USE SIGNAL ;
    PORT
      LAYER met3 ;
        RECT  0 484.35 0.8 484.65 ;
    END
  END ra_forward_cos_v_in[52]
  PIN ra_forward_cos_v_in[53]
    DIRECTION INPUT ;
    USE SIGNAL ;
    PORT
      LAYER met3 ;
        RECT  0 502.03 0.8 502.33 ;
    END
  END ra_forward_cos_v_in[53]
  PIN ra_forward_cos_v_in[54]
    DIRECTION INPUT ;
    USE SIGNAL ;
    PORT
      LAYER met3 ;
        RECT  0 866.51 0.8 866.81 ;
    END
  END ra_forward_cos_v_in[54]
  PIN ra_forward_cos_v_in[55]
    DIRECTION INPUT ;
    USE SIGNAL ;
    PORT
      LAYER met3 ;
        RECT  0 355.15 0.8 355.45 ;
    END
  END ra_forward_cos_v_in[55]
  PIN ra_forward_cos_v_in[56]
    DIRECTION INPUT ;
    USE SIGNAL ;
    PORT
      LAYER met3 ;
        RECT  0 1247.31 0.8 1247.61 ;
    END
  END ra_forward_cos_v_in[56]
  PIN ra_forward_cos_v_in[57]
    DIRECTION INPUT ;
    USE SIGNAL ;
    PORT
      LAYER met3 ;
        RECT  0 1022.91 0.8 1023.21 ;
    END
  END ra_forward_cos_v_in[57]
  PIN ra_forward_cos_v_in[58]
    DIRECTION INPUT ;
    USE SIGNAL ;
    PORT
      LAYER met3 ;
        RECT  0 1347.95 0.8 1348.25 ;
    END
  END ra_forward_cos_v_in[58]
  PIN ra_forward_cos_v_in[59]
    DIRECTION INPUT ;
    USE SIGNAL ;
    PORT
      LAYER met3 ;
        RECT  0 228.67 0.8 228.97 ;
    END
  END ra_forward_cos_v_in[59]
  PIN ra_forward_cos_v_in[5]
    DIRECTION INPUT ;
    USE SIGNAL ;
    PORT
      LAYER met3 ;
        RECT  0 1425.47 0.8 1425.77 ;
    END
  END ra_forward_cos_v_in[5]
  PIN ra_forward_cos_v_in[60]
    DIRECTION INPUT ;
    USE SIGNAL ;
    PORT
      LAYER met3 ;
        RECT  0 537.39 0.8 537.69 ;
    END
  END ra_forward_cos_v_in[60]
  PIN ra_forward_cos_v_in[61]
    DIRECTION INPUT ;
    USE SIGNAL ;
    PORT
      LAYER met3 ;
        RECT  0 1345.23 0.8 1345.53 ;
    END
  END ra_forward_cos_v_in[61]
  PIN ra_forward_cos_v_in[62]
    DIRECTION INPUT ;
    USE SIGNAL ;
    PORT
      LAYER met3 ;
        RECT  0 511.55 0.8 511.85 ;
    END
  END ra_forward_cos_v_in[62]
  PIN ra_forward_cos_v_in[63]
    DIRECTION INPUT ;
    USE SIGNAL ;
    PORT
      LAYER met3 ;
        RECT  0 230.03 0.8 230.33 ;
    END
  END ra_forward_cos_v_in[63]
  PIN ra_forward_cos_v_in[64]
    DIRECTION INPUT ;
    USE SIGNAL ;
    PORT
      LAYER met3 ;
        RECT  0 1131.71 0.8 1132.01 ;
    END
  END ra_forward_cos_v_in[64]
  PIN ra_forward_cos_v_in[65]
    DIRECTION INPUT ;
    USE SIGNAL ;
    PORT
      LAYER met3 ;
        RECT  0 852.91 0.8 853.21 ;
    END
  END ra_forward_cos_v_in[65]
  PIN ra_forward_cos_v_in[66]
    DIRECTION INPUT ;
    USE SIGNAL ;
    PORT
      LAYER met3 ;
        RECT  0 1165.71 0.8 1166.01 ;
    END
  END ra_forward_cos_v_in[66]
  PIN ra_forward_cos_v_in[67]
    DIRECTION INPUT ;
    USE SIGNAL ;
    PORT
      LAYER met3 ;
        RECT  0 972.59 0.8 972.89 ;
    END
  END ra_forward_cos_v_in[67]
  PIN ra_forward_cos_v_in[68]
    DIRECTION INPUT ;
    USE SIGNAL ;
    PORT
      LAYER met3 ;
        RECT  0 231.39 0.8 231.69 ;
    END
  END ra_forward_cos_v_in[68]
  PIN ra_forward_cos_v_in[69]
    DIRECTION INPUT ;
    USE SIGNAL ;
    PORT
      LAYER met3 ;
        RECT  0 443.55 0.8 443.85 ;
    END
  END ra_forward_cos_v_in[69]
  PIN ra_forward_cos_v_in[6]
    DIRECTION INPUT ;
    USE SIGNAL ;
    PORT
      LAYER met3 ;
        RECT  0 387.79 0.8 388.09 ;
    END
  END ra_forward_cos_v_in[6]
  PIN ra_forward_cos_v_in[70]
    DIRECTION INPUT ;
    USE SIGNAL ;
    PORT
      LAYER met3 ;
        RECT  0 1343.87 0.8 1344.17 ;
    END
  END ra_forward_cos_v_in[70]
  PIN ra_forward_cos_v_in[71]
    DIRECTION INPUT ;
    USE SIGNAL ;
    PORT
      LAYER met3 ;
        RECT  0 1153.47 0.8 1153.77 ;
    END
  END ra_forward_cos_v_in[71]
  PIN ra_forward_cos_v_in[72]
    DIRECTION INPUT ;
    USE SIGNAL ;
    PORT
      LAYER met3 ;
        RECT  0 967.15 0.8 967.45 ;
    END
  END ra_forward_cos_v_in[72]
  PIN ra_forward_cos_v_in[73]
    DIRECTION INPUT ;
    USE SIGNAL ;
    PORT
      LAYER met3 ;
        RECT  0 839.31 0.8 839.61 ;
    END
  END ra_forward_cos_v_in[73]
  PIN ra_forward_cos_v_in[74]
    DIRECTION INPUT ;
    USE SIGNAL ;
    PORT
      LAYER met3 ;
        RECT  0 1105.87 0.8 1106.17 ;
    END
  END ra_forward_cos_v_in[74]
  PIN ra_forward_cos_v_in[75]
    DIRECTION INPUT ;
    USE SIGNAL ;
    PORT
      LAYER met3 ;
        RECT  0 726.43 0.8 726.73 ;
    END
  END ra_forward_cos_v_in[75]
  PIN ra_forward_cos_v_in[76]
    DIRECTION INPUT ;
    USE SIGNAL ;
    PORT
      LAYER met3 ;
        RECT  0 945.39 0.8 945.69 ;
    END
  END ra_forward_cos_v_in[76]
  PIN ra_forward_cos_v_in[77]
    DIRECTION INPUT ;
    USE SIGNAL ;
    PORT
      LAYER met3 ;
        RECT  0 673.39 0.8 673.69 ;
    END
  END ra_forward_cos_v_in[77]
  PIN ra_forward_cos_v_in[78]
    DIRECTION INPUT ;
    USE SIGNAL ;
    PORT
      LAYER met3 ;
        RECT  0 956.27 0.8 956.57 ;
    END
  END ra_forward_cos_v_in[78]
  PIN ra_forward_cos_v_in[79]
    DIRECTION INPUT ;
    USE SIGNAL ;
    PORT
      LAYER met3 ;
        RECT  0 661.15 0.8 661.45 ;
    END
  END ra_forward_cos_v_in[79]
  PIN ra_forward_cos_v_in[7]
    DIRECTION INPUT ;
    USE SIGNAL ;
    PORT
      LAYER met3 ;
        RECT  0 752.27 0.8 752.57 ;
    END
  END ra_forward_cos_v_in[7]
  PIN ra_forward_cos_v_in[80]
    DIRECTION INPUT ;
    USE SIGNAL ;
    PORT
      LAYER met3 ;
        RECT  0 215.07 0.8 215.37 ;
    END
  END ra_forward_cos_v_in[80]
  PIN ra_forward_cos_v_in[81]
    DIRECTION INPUT ;
    USE SIGNAL ;
    PORT
      LAYER met3 ;
        RECT  0 1239.15 0.8 1239.45 ;
    END
  END ra_forward_cos_v_in[81]
  PIN ra_forward_cos_v_in[82]
    DIRECTION INPUT ;
    USE SIGNAL ;
    PORT
      LAYER met3 ;
        RECT  0 466.67 0.8 466.97 ;
    END
  END ra_forward_cos_v_in[82]
  PIN ra_forward_cos_v_in[83]
    DIRECTION INPUT ;
    USE SIGNAL ;
    PORT
      LAYER met3 ;
        RECT  0 219.15 0.8 219.45 ;
    END
  END ra_forward_cos_v_in[83]
  PIN ra_forward_cos_v_in[84]
    DIRECTION INPUT ;
    USE SIGNAL ;
    PORT
      LAYER met3 ;
        RECT  0 1067.79 0.8 1068.09 ;
    END
  END ra_forward_cos_v_in[84]
  PIN ra_forward_cos_v_in[85]
    DIRECTION INPUT ;
    USE SIGNAL ;
    PORT
      LAYER met3 ;
        RECT  0 725.07 0.8 725.37 ;
    END
  END ra_forward_cos_v_in[85]
  PIN ra_forward_cos_v_in[86]
    DIRECTION INPUT ;
    USE SIGNAL ;
    PORT
      LAYER met3 ;
        RECT  0 633.95 0.8 634.25 ;
    END
  END ra_forward_cos_v_in[86]
  PIN ra_forward_cos_v_in[87]
    DIRECTION INPUT ;
    USE SIGNAL ;
    PORT
      LAYER met3 ;
        RECT  0 1126.27 0.8 1126.57 ;
    END
  END ra_forward_cos_v_in[87]
  PIN ra_forward_cos_v_in[88]
    DIRECTION INPUT ;
    USE SIGNAL ;
    PORT
      LAYER met3 ;
        RECT  0 375.55 0.8 375.85 ;
    END
  END ra_forward_cos_v_in[88]
  PIN ra_forward_cos_v_in[89]
    DIRECTION INPUT ;
    USE SIGNAL ;
    PORT
      LAYER met3 ;
        RECT  0 317.07 0.8 317.37 ;
    END
  END ra_forward_cos_v_in[89]
  PIN ra_forward_cos_v_in[8]
    DIRECTION INPUT ;
    USE SIGNAL ;
    PORT
      LAYER met3 ;
        RECT  0 541.47 0.8 541.77 ;
    END
  END ra_forward_cos_v_in[8]
  PIN ra_forward_cos_v_in[90]
    DIRECTION INPUT ;
    USE SIGNAL ;
    PORT
      LAYER met3 ;
        RECT  0 635.31 0.8 635.61 ;
    END
  END ra_forward_cos_v_in[90]
  PIN ra_forward_cos_v_in[91]
    DIRECTION INPUT ;
    USE SIGNAL ;
    PORT
      LAYER met3 ;
        RECT  0 216.43 0.8 216.73 ;
    END
  END ra_forward_cos_v_in[91]
  PIN ra_forward_cos_v_in[92]
    DIRECTION INPUT ;
    USE SIGNAL ;
    PORT
      LAYER met3 ;
        RECT  0 1168.43 0.8 1168.73 ;
    END
  END ra_forward_cos_v_in[92]
  PIN ra_forward_cos_v_in[93]
    DIRECTION INPUT ;
    USE SIGNAL ;
    PORT
      LAYER met3 ;
        RECT  0 1013.39 0.8 1013.69 ;
    END
  END ra_forward_cos_v_in[93]
  PIN ra_forward_cos_v_in[94]
    DIRECTION INPUT ;
    USE SIGNAL ;
    PORT
      LAYER met3 ;
        RECT  0 1424.11 0.8 1424.41 ;
    END
  END ra_forward_cos_v_in[94]
  PIN ra_forward_cos_v_in[95]
    DIRECTION INPUT ;
    USE SIGNAL ;
    PORT
      LAYER met3 ;
        RECT  0 1154.83 0.8 1155.13 ;
    END
  END ra_forward_cos_v_in[95]
  PIN ra_forward_cos_v_in[96]
    DIRECTION INPUT ;
    USE SIGNAL ;
    PORT
      LAYER met3 ;
        RECT  0 1050.11 0.8 1050.41 ;
    END
  END ra_forward_cos_v_in[96]
  PIN ra_forward_cos_v_in[97]
    DIRECTION INPUT ;
    USE SIGNAL ;
    PORT
      LAYER met3 ;
        RECT  0 1433.63 0.8 1433.93 ;
    END
  END ra_forward_cos_v_in[97]
  PIN ra_forward_cos_v_in[98]
    DIRECTION INPUT ;
    USE SIGNAL ;
    PORT
      LAYER met3 ;
        RECT  0 727.79 0.8 728.09 ;
    END
  END ra_forward_cos_v_in[98]
  PIN ra_forward_cos_v_in[99]
    DIRECTION INPUT ;
    USE SIGNAL ;
    PORT
      LAYER met3 ;
        RECT  0 495.23 0.8 495.53 ;
    END
  END ra_forward_cos_v_in[99]
  PIN ra_forward_cos_v_in[9]
    DIRECTION INPUT ;
    USE SIGNAL ;
    PORT
      LAYER met3 ;
        RECT  0 1209.23 0.8 1209.53 ;
    END
  END ra_forward_cos_v_in[9]
  PIN ra_forward_cos_valid_in
    DIRECTION INPUT ;
    USE SIGNAL ;
    PORT
      LAYER met3 ;
        RECT  0 1493.47 0.8 1493.77 ;
    END
  END ra_forward_cos_valid_in
  PIN ra_forward_sin_empty_out
    DIRECTION OUTPUT ;
    USE SIGNAL ;
    PORT
      LAYER met3 ;
        RECT  0 1998.03 0.8 1998.33 ;
    END
  END ra_forward_sin_empty_out
  PIN ra_forward_sin_phase_in[0]
    DIRECTION INPUT ;
    USE SIGNAL ;
    PORT
      LAYER met3 ;
        RECT  0 2060.59 0.8 2060.89 ;
    END
  END ra_forward_sin_phase_in[0]
  PIN ra_forward_sin_phase_in[1]
    DIRECTION INPUT ;
    USE SIGNAL ;
    PORT
      LAYER met3 ;
        RECT  0 2061.95 0.8 2062.25 ;
    END
  END ra_forward_sin_phase_in[1]
  PIN ra_forward_sin_rden_in
    DIRECTION INPUT ;
    USE SIGNAL ;
    PORT
      LAYER met3 ;
        RECT  0 1969.47 0.8 1969.77 ;
    END
  END ra_forward_sin_rden_in
  PIN ra_forward_sin_rdy_out
    DIRECTION OUTPUT ;
    USE SIGNAL ;
    PORT
      LAYER met3 ;
        RECT  0 1995.31 0.8 1995.61 ;
    END
  END ra_forward_sin_rdy_out
  PIN ra_forward_sin_v_in[0]
    DIRECTION INPUT ;
    USE SIGNAL ;
    PORT
      LAYER met3 ;
        RECT  0 2853.47 0.8 2853.77 ;
    END
  END ra_forward_sin_v_in[0]
  PIN ra_forward_sin_v_in[100]
    DIRECTION INPUT ;
    USE SIGNAL ;
    PORT
      LAYER met3 ;
        RECT  0 2828.99 0.8 2829.29 ;
    END
  END ra_forward_sin_v_in[100]
  PIN ra_forward_sin_v_in[101]
    DIRECTION INPUT ;
    USE SIGNAL ;
    PORT
      LAYER met3 ;
        RECT  0 3039.79 0.8 3040.09 ;
    END
  END ra_forward_sin_v_in[101]
  PIN ra_forward_sin_v_in[102]
    DIRECTION INPUT ;
    USE SIGNAL ;
    PORT
      LAYER met3 ;
        RECT  0 3151.31 0.8 3151.61 ;
    END
  END ra_forward_sin_v_in[102]
  PIN ra_forward_sin_v_in[103]
    DIRECTION INPUT ;
    USE SIGNAL ;
    PORT
      LAYER met3 ;
        RECT  0 3096.91 0.8 3097.21 ;
    END
  END ra_forward_sin_v_in[103]
  PIN ra_forward_sin_v_in[104]
    DIRECTION INPUT ;
    USE SIGNAL ;
    PORT
      LAYER met3 ;
        RECT  0 3013.95 0.8 3014.25 ;
    END
  END ra_forward_sin_v_in[104]
  PIN ra_forward_sin_v_in[105]
    DIRECTION INPUT ;
    USE SIGNAL ;
    PORT
      LAYER met3 ;
        RECT  0 2737.87 0.8 2738.17 ;
    END
  END ra_forward_sin_v_in[105]
  PIN ra_forward_sin_v_in[106]
    DIRECTION INPUT ;
    USE SIGNAL ;
    PORT
      LAYER met3 ;
        RECT  0 2089.15 0.8 2089.45 ;
    END
  END ra_forward_sin_v_in[106]
  PIN ra_forward_sin_v_in[107]
    DIRECTION INPUT ;
    USE SIGNAL ;
    PORT
      LAYER met3 ;
        RECT  0 2449.55 0.8 2449.85 ;
    END
  END ra_forward_sin_v_in[107]
  PIN ra_forward_sin_v_in[108]
    DIRECTION INPUT ;
    USE SIGNAL ;
    PORT
      LAYER met3 ;
        RECT  0 3134.99 0.8 3135.29 ;
    END
  END ra_forward_sin_v_in[108]
  PIN ra_forward_sin_v_in[109]
    DIRECTION INPUT ;
    USE SIGNAL ;
    PORT
      LAYER met3 ;
        RECT  0 3231.55 0.8 3231.85 ;
    END
  END ra_forward_sin_v_in[109]
  PIN ra_forward_sin_v_in[10]
    DIRECTION INPUT ;
    USE SIGNAL ;
    PORT
      LAYER met3 ;
        RECT  0 2495.79 0.8 2496.09 ;
    END
  END ra_forward_sin_v_in[10]
  PIN ra_forward_sin_v_in[110]
    DIRECTION INPUT ;
    USE SIGNAL ;
    PORT
      LAYER met3 ;
        RECT  0 2930.99 0.8 2931.29 ;
    END
  END ra_forward_sin_v_in[110]
  PIN ra_forward_sin_v_in[111]
    DIRECTION INPUT ;
    USE SIGNAL ;
    PORT
      LAYER met3 ;
        RECT  0 3222.03 0.8 3222.33 ;
    END
  END ra_forward_sin_v_in[111]
  PIN ra_forward_sin_v_in[112]
    DIRECTION INPUT ;
    USE SIGNAL ;
    PORT
      LAYER met3 ;
        RECT  0 3209.79 0.8 3210.09 ;
    END
  END ra_forward_sin_v_in[112]
  PIN ra_forward_sin_v_in[113]
    DIRECTION INPUT ;
    USE SIGNAL ;
    PORT
      LAYER met3 ;
        RECT  0 2138.11 0.8 2138.41 ;
    END
  END ra_forward_sin_v_in[113]
  PIN ra_forward_sin_v_in[114]
    DIRECTION INPUT ;
    USE SIGNAL ;
    PORT
      LAYER met3 ;
        RECT  0 2067.39 0.8 2067.69 ;
    END
  END ra_forward_sin_v_in[114]
  PIN ra_forward_sin_v_in[115]
    DIRECTION INPUT ;
    USE SIGNAL ;
    PORT
      LAYER met3 ;
        RECT  0 2365.23 0.8 2365.53 ;
    END
  END ra_forward_sin_v_in[115]
  PIN ra_forward_sin_v_in[116]
    DIRECTION INPUT ;
    USE SIGNAL ;
    PORT
      LAYER met3 ;
        RECT  0 2106.83 0.8 2107.13 ;
    END
  END ra_forward_sin_v_in[116]
  PIN ra_forward_sin_v_in[117]
    DIRECTION INPUT ;
    USE SIGNAL ;
    PORT
      LAYER met3 ;
        RECT  0 2161.23 0.8 2161.53 ;
    END
  END ra_forward_sin_v_in[117]
  PIN ra_forward_sin_v_in[118]
    DIRECTION INPUT ;
    USE SIGNAL ;
    PORT
      LAYER met3 ;
        RECT  0 2827.63 0.8 2827.93 ;
    END
  END ra_forward_sin_v_in[118]
  PIN ra_forward_sin_v_in[119]
    DIRECTION INPUT ;
    USE SIGNAL ;
    PORT
      LAYER met3 ;
        RECT  0 2280.91 0.8 2281.21 ;
    END
  END ra_forward_sin_v_in[119]
  PIN ra_forward_sin_v_in[11]
    DIRECTION INPUT ;
    USE SIGNAL ;
    PORT
      LAYER met3 ;
        RECT  0 2877.95 0.8 2878.25 ;
    END
  END ra_forward_sin_v_in[11]
  PIN ra_forward_sin_v_in[120]
    DIRECTION INPUT ;
    USE SIGNAL ;
    PORT
      LAYER met3 ;
        RECT  0 2686.19 0.8 2686.49 ;
    END
  END ra_forward_sin_v_in[120]
  PIN ra_forward_sin_v_in[121]
    DIRECTION INPUT ;
    USE SIGNAL ;
    PORT
      LAYER met3 ;
        RECT  0 2816.75 0.8 2817.05 ;
    END
  END ra_forward_sin_v_in[121]
  PIN ra_forward_sin_v_in[122]
    DIRECTION INPUT ;
    USE SIGNAL ;
    PORT
      LAYER met3 ;
        RECT  0 3126.83 0.8 3127.13 ;
    END
  END ra_forward_sin_v_in[122]
  PIN ra_forward_sin_v_in[123]
    DIRECTION INPUT ;
    USE SIGNAL ;
    PORT
      LAYER met3 ;
        RECT  0 2085.07 0.8 2085.37 ;
    END
  END ra_forward_sin_v_in[123]
  PIN ra_forward_sin_v_in[124]
    DIRECTION INPUT ;
    USE SIGNAL ;
    PORT
      LAYER met3 ;
        RECT  0 3215.23 0.8 3215.53 ;
    END
  END ra_forward_sin_v_in[124]
  PIN ra_forward_sin_v_in[125]
    DIRECTION INPUT ;
    USE SIGNAL ;
    PORT
      LAYER met3 ;
        RECT  0 3193.47 0.8 3193.77 ;
    END
  END ra_forward_sin_v_in[125]
  PIN ra_forward_sin_v_in[126]
    DIRECTION INPUT ;
    USE SIGNAL ;
    PORT
      LAYER met3 ;
        RECT  0 2658.99 0.8 2659.29 ;
    END
  END ra_forward_sin_v_in[126]
  PIN ra_forward_sin_v_in[127]
    DIRECTION INPUT ;
    USE SIGNAL ;
    PORT
      LAYER met3 ;
        RECT  0 2600.51 0.8 2600.81 ;
    END
  END ra_forward_sin_v_in[127]
  PIN ra_forward_sin_v_in[128]
    DIRECTION INPUT ;
    USE SIGNAL ;
    PORT
      LAYER met3 ;
        RECT  0 3136.35 0.8 3136.65 ;
    END
  END ra_forward_sin_v_in[128]
  PIN ra_forward_sin_v_in[129]
    DIRECTION INPUT ;
    USE SIGNAL ;
    PORT
      LAYER met3 ;
        RECT  0 3107.79 0.8 3108.09 ;
    END
  END ra_forward_sin_v_in[129]
  PIN ra_forward_sin_v_in[12]
    DIRECTION INPUT ;
    USE SIGNAL ;
    PORT
      LAYER met3 ;
        RECT  0 2289.07 0.8 2289.37 ;
    END
  END ra_forward_sin_v_in[12]
  PIN ra_forward_sin_v_in[130]
    DIRECTION INPUT ;
    USE SIGNAL ;
    PORT
      LAYER met3 ;
        RECT  0 2286.35 0.8 2286.65 ;
    END
  END ra_forward_sin_v_in[130]
  PIN ra_forward_sin_v_in[131]
    DIRECTION INPUT ;
    USE SIGNAL ;
    PORT
      LAYER met3 ;
        RECT  0 2339.39 0.8 2339.69 ;
    END
  END ra_forward_sin_v_in[131]
  PIN ra_forward_sin_v_in[132]
    DIRECTION INPUT ;
    USE SIGNAL ;
    PORT
      LAYER met3 ;
        RECT  0 2305.39 0.8 2305.69 ;
    END
  END ra_forward_sin_v_in[132]
  PIN ra_forward_sin_v_in[133]
    DIRECTION INPUT ;
    USE SIGNAL ;
    PORT
      LAYER met3 ;
        RECT  0 2611.39 0.8 2611.69 ;
    END
  END ra_forward_sin_v_in[133]
  PIN ra_forward_sin_v_in[134]
    DIRECTION INPUT ;
    USE SIGNAL ;
    PORT
      LAYER met3 ;
        RECT  0 2278.19 0.8 2278.49 ;
    END
  END ra_forward_sin_v_in[134]
  PIN ra_forward_sin_v_in[135]
    DIRECTION INPUT ;
    USE SIGNAL ;
    PORT
      LAYER met3 ;
        RECT  0 3236.99 0.8 3237.29 ;
    END
  END ra_forward_sin_v_in[135]
  PIN ra_forward_sin_v_in[136]
    DIRECTION INPUT ;
    USE SIGNAL ;
    PORT
      LAYER met3 ;
        RECT  0 2879.31 0.8 2879.61 ;
    END
  END ra_forward_sin_v_in[136]
  PIN ra_forward_sin_v_in[137]
    DIRECTION INPUT ;
    USE SIGNAL ;
    PORT
      LAYER met3 ;
        RECT  0 2082.35 0.8 2082.65 ;
    END
  END ra_forward_sin_v_in[137]
  PIN ra_forward_sin_v_in[138]
    DIRECTION INPUT ;
    USE SIGNAL ;
    PORT
      LAYER met3 ;
        RECT  0 2370.67 0.8 2370.97 ;
    END
  END ra_forward_sin_v_in[138]
  PIN ra_forward_sin_v_in[139]
    DIRECTION INPUT ;
    USE SIGNAL ;
    PORT
      LAYER met3 ;
        RECT  0 2195.23 0.8 2195.53 ;
    END
  END ra_forward_sin_v_in[139]
  PIN ra_forward_sin_v_in[13]
    DIRECTION INPUT ;
    USE SIGNAL ;
    PORT
      LAYER met3 ;
        RECT  0 2819.47 0.8 2819.77 ;
    END
  END ra_forward_sin_v_in[13]
  PIN ra_forward_sin_v_in[140]
    DIRECTION INPUT ;
    USE SIGNAL ;
    PORT
      LAYER met3 ;
        RECT  0 3018.03 0.8 3018.33 ;
    END
  END ra_forward_sin_v_in[140]
  PIN ra_forward_sin_v_in[141]
    DIRECTION INPUT ;
    USE SIGNAL ;
    PORT
      LAYER met3 ;
        RECT  0 2896.99 0.8 2897.29 ;
    END
  END ra_forward_sin_v_in[141]
  PIN ra_forward_sin_v_in[142]
    DIRECTION INPUT ;
    USE SIGNAL ;
    PORT
      LAYER met3 ;
        RECT  0 2076.91 0.8 2077.21 ;
    END
  END ra_forward_sin_v_in[142]
  PIN ra_forward_sin_v_in[143]
    DIRECTION INPUT ;
    USE SIGNAL ;
    PORT
      LAYER met3 ;
        RECT  0 2282.27 0.8 2282.57 ;
    END
  END ra_forward_sin_v_in[143]
  PIN ra_forward_sin_v_in[144]
    DIRECTION INPUT ;
    USE SIGNAL ;
    PORT
      LAYER met3 ;
        RECT  0 3226.11 0.8 3226.41 ;
    END
  END ra_forward_sin_v_in[144]
  PIN ra_forward_sin_v_in[145]
    DIRECTION INPUT ;
    USE SIGNAL ;
    PORT
      LAYER met3 ;
        RECT  0 2531.15 0.8 2531.45 ;
    END
  END ra_forward_sin_v_in[145]
  PIN ra_forward_sin_v_in[146]
    DIRECTION INPUT ;
    USE SIGNAL ;
    PORT
      LAYER met3 ;
        RECT  0 2952.75 0.8 2953.05 ;
    END
  END ra_forward_sin_v_in[146]
  PIN ra_forward_sin_v_in[147]
    DIRECTION INPUT ;
    USE SIGNAL ;
    PORT
      LAYER met3 ;
        RECT  0 3224.75 0.8 3225.05 ;
    END
  END ra_forward_sin_v_in[147]
  PIN ra_forward_sin_v_in[148]
    DIRECTION INPUT ;
    USE SIGNAL ;
    PORT
      LAYER met3 ;
        RECT  0 2954.11 0.8 2954.41 ;
    END
  END ra_forward_sin_v_in[148]
  PIN ra_forward_sin_v_in[149]
    DIRECTION INPUT ;
    USE SIGNAL ;
    PORT
      LAYER met3 ;
        RECT  0 2624.99 0.8 2625.29 ;
    END
  END ra_forward_sin_v_in[149]
  PIN ra_forward_sin_v_in[14]
    DIRECTION INPUT ;
    USE SIGNAL ;
    PORT
      LAYER met3 ;
        RECT  0 2410.11 0.8 2410.41 ;
    END
  END ra_forward_sin_v_in[14]
  PIN ra_forward_sin_v_in[150]
    DIRECTION INPUT ;
    USE SIGNAL ;
    PORT
      LAYER met3 ;
        RECT  0 2612.75 0.8 2613.05 ;
    END
  END ra_forward_sin_v_in[150]
  PIN ra_forward_sin_v_in[151]
    DIRECTION INPUT ;
    USE SIGNAL ;
    PORT
      LAYER met3 ;
        RECT  0 3167.63 0.8 3167.93 ;
    END
  END ra_forward_sin_v_in[151]
  PIN ra_forward_sin_v_in[152]
    DIRECTION INPUT ;
    USE SIGNAL ;
    PORT
      LAYER met3 ;
        RECT  0 2505.31 0.8 2505.61 ;
    END
  END ra_forward_sin_v_in[152]
  PIN ra_forward_sin_v_in[153]
    DIRECTION INPUT ;
    USE SIGNAL ;
    PORT
      LAYER met3 ;
        RECT  0 3114.59 0.8 3114.89 ;
    END
  END ra_forward_sin_v_in[153]
  PIN ra_forward_sin_v_in[154]
    DIRECTION INPUT ;
    USE SIGNAL ;
    PORT
      LAYER met3 ;
        RECT  0 2080.99 0.8 2081.29 ;
    END
  END ra_forward_sin_v_in[154]
  PIN ra_forward_sin_v_in[155]
    DIRECTION INPUT ;
    USE SIGNAL ;
    PORT
      LAYER met3 ;
        RECT  0 2452.27 0.8 2452.57 ;
    END
  END ra_forward_sin_v_in[155]
  PIN ra_forward_sin_v_in[156]
    DIRECTION INPUT ;
    USE SIGNAL ;
    PORT
      LAYER met3 ;
        RECT  0 3190.75 0.8 3191.05 ;
    END
  END ra_forward_sin_v_in[156]
  PIN ra_forward_sin_v_in[157]
    DIRECTION INPUT ;
    USE SIGNAL ;
    PORT
      LAYER met3 ;
        RECT  0 2948.67 0.8 2948.97 ;
    END
  END ra_forward_sin_v_in[157]
  PIN ra_forward_sin_v_in[158]
    DIRECTION INPUT ;
    USE SIGNAL ;
    PORT
      LAYER met3 ;
        RECT  0 2169.39 0.8 2169.69 ;
    END
  END ra_forward_sin_v_in[158]
  PIN ra_forward_sin_v_in[159]
    DIRECTION INPUT ;
    USE SIGNAL ;
    PORT
      LAYER met3 ;
        RECT  0 2423.71 0.8 2424.01 ;
    END
  END ra_forward_sin_v_in[159]
  PIN ra_forward_sin_v_in[15]
    DIRECTION INPUT ;
    USE SIGNAL ;
    PORT
      LAYER met3 ;
        RECT  0 3194.83 0.8 3195.13 ;
    END
  END ra_forward_sin_v_in[15]
  PIN ra_forward_sin_v_in[160]
    DIRECTION INPUT ;
    USE SIGNAL ;
    PORT
      LAYER met3 ;
        RECT  0 2554.27 0.8 2554.57 ;
    END
  END ra_forward_sin_v_in[160]
  PIN ra_forward_sin_v_in[161]
    DIRECTION INPUT ;
    USE SIGNAL ;
    PORT
      LAYER met3 ;
        RECT  0 2188.43 0.8 2188.73 ;
    END
  END ra_forward_sin_v_in[161]
  PIN ra_forward_sin_v_in[162]
    DIRECTION INPUT ;
    USE SIGNAL ;
    PORT
      LAYER met3 ;
        RECT  0 2550.19 0.8 2550.49 ;
    END
  END ra_forward_sin_v_in[162]
  PIN ra_forward_sin_v_in[163]
    DIRECTION INPUT ;
    USE SIGNAL ;
    PORT
      LAYER met3 ;
        RECT  0 3235.63 0.8 3235.93 ;
    END
  END ra_forward_sin_v_in[163]
  PIN ra_forward_sin_v_in[164]
    DIRECTION INPUT ;
    USE SIGNAL ;
    PORT
      LAYER met3 ;
        RECT  0 2064.67 0.8 2064.97 ;
    END
  END ra_forward_sin_v_in[164]
  PIN ra_forward_sin_v_in[165]
    DIRECTION INPUT ;
    USE SIGNAL ;
    PORT
      LAYER met3 ;
        RECT  0 2524.35 0.8 2524.65 ;
    END
  END ra_forward_sin_v_in[165]
  PIN ra_forward_sin_v_in[166]
    DIRECTION INPUT ;
    USE SIGNAL ;
    PORT
      LAYER met3 ;
        RECT  0 2607.31 0.8 2607.61 ;
    END
  END ra_forward_sin_v_in[166]
  PIN ra_forward_sin_v_in[167]
    DIRECTION INPUT ;
    USE SIGNAL ;
    PORT
      LAYER met3 ;
        RECT  0 2184.35 0.8 2184.65 ;
    END
  END ra_forward_sin_v_in[167]
  PIN ra_forward_sin_v_in[168]
    DIRECTION INPUT ;
    USE SIGNAL ;
    PORT
      LAYER met3 ;
        RECT  0 2769.15 0.8 2769.45 ;
    END
  END ra_forward_sin_v_in[168]
  PIN ra_forward_sin_v_in[169]
    DIRECTION INPUT ;
    USE SIGNAL ;
    PORT
      LAYER met3 ;
        RECT  0 2396.51 0.8 2396.81 ;
    END
  END ra_forward_sin_v_in[169]
  PIN ra_forward_sin_v_in[16]
    DIRECTION INPUT ;
    USE SIGNAL ;
    PORT
      LAYER met3 ;
        RECT  0 2918.75 0.8 2919.05 ;
    END
  END ra_forward_sin_v_in[16]
  PIN ra_forward_sin_v_in[170]
    DIRECTION INPUT ;
    USE SIGNAL ;
    PORT
      LAYER met3 ;
        RECT  0 3216.59 0.8 3216.89 ;
    END
  END ra_forward_sin_v_in[170]
  PIN ra_forward_sin_v_in[171]
    DIRECTION INPUT ;
    USE SIGNAL ;
    PORT
      LAYER met3 ;
        RECT  0 2230.59 0.8 2230.89 ;
    END
  END ra_forward_sin_v_in[171]
  PIN ra_forward_sin_v_in[172]
    DIRECTION INPUT ;
    USE SIGNAL ;
    PORT
      LAYER met3 ;
        RECT  0 2921.47 0.8 2921.77 ;
    END
  END ra_forward_sin_v_in[172]
  PIN ra_forward_sin_v_in[173]
    DIRECTION INPUT ;
    USE SIGNAL ;
    PORT
      LAYER met3 ;
        RECT  0 3227.47 0.8 3227.77 ;
    END
  END ra_forward_sin_v_in[173]
  PIN ra_forward_sin_v_in[174]
    DIRECTION INPUT ;
    USE SIGNAL ;
    PORT
      LAYER met3 ;
        RECT  0 3054.75 0.8 3055.05 ;
    END
  END ra_forward_sin_v_in[174]
  PIN ra_forward_sin_v_in[175]
    DIRECTION INPUT ;
    USE SIGNAL ;
    PORT
      LAYER met3 ;
        RECT  0 3003.07 0.8 3003.37 ;
    END
  END ra_forward_sin_v_in[175]
  PIN ra_forward_sin_v_in[176]
    DIRECTION INPUT ;
    USE SIGNAL ;
    PORT
      LAYER met3 ;
        RECT  0 2208.83 0.8 2209.13 ;
    END
  END ra_forward_sin_v_in[176]
  PIN ra_forward_sin_v_in[177]
    DIRECTION INPUT ;
    USE SIGNAL ;
    PORT
      LAYER met3 ;
        RECT  0 2578.75 0.8 2579.05 ;
    END
  END ra_forward_sin_v_in[177]
  PIN ra_forward_sin_v_in[178]
    DIRECTION INPUT ;
    USE SIGNAL ;
    PORT
      LAYER met3 ;
        RECT  0 2608.67 0.8 2608.97 ;
    END
  END ra_forward_sin_v_in[178]
  PIN ra_forward_sin_v_in[179]
    DIRECTION INPUT ;
    USE SIGNAL ;
    PORT
      LAYER met3 ;
        RECT  0 2100.03 0.8 2100.33 ;
    END
  END ra_forward_sin_v_in[179]
  PIN ra_forward_sin_v_in[17]
    DIRECTION INPUT ;
    USE SIGNAL ;
    PORT
      LAYER met3 ;
        RECT  0 2548.83 0.8 2549.13 ;
    END
  END ra_forward_sin_v_in[17]
  PIN ra_forward_sin_v_in[180]
    DIRECTION INPUT ;
    USE SIGNAL ;
    PORT
      LAYER met3 ;
        RECT  0 2399.23 0.8 2399.53 ;
    END
  END ra_forward_sin_v_in[180]
  PIN ra_forward_sin_v_in[181]
    DIRECTION INPUT ;
    USE SIGNAL ;
    PORT
      LAYER met3 ;
        RECT  0 2808.59 0.8 2808.89 ;
    END
  END ra_forward_sin_v_in[181]
  PIN ra_forward_sin_v_in[182]
    DIRECTION INPUT ;
    USE SIGNAL ;
    PORT
      LAYER met3 ;
        RECT  0 2151.71 0.8 2152.01 ;
    END
  END ra_forward_sin_v_in[182]
  PIN ra_forward_sin_v_in[183]
    DIRECTION INPUT ;
    USE SIGNAL ;
    PORT
      LAYER met3 ;
        RECT  0 2109.55 0.8 2109.85 ;
    END
  END ra_forward_sin_v_in[183]
  PIN ra_forward_sin_v_in[184]
    DIRECTION INPUT ;
    USE SIGNAL ;
    PORT
      LAYER met3 ;
        RECT  0 2165.31 0.8 2165.61 ;
    END
  END ra_forward_sin_v_in[184]
  PIN ra_forward_sin_v_in[185]
    DIRECTION INPUT ;
    USE SIGNAL ;
    PORT
      LAYER met3 ;
        RECT  0 3223.39 0.8 3223.69 ;
    END
  END ra_forward_sin_v_in[185]
  PIN ra_forward_sin_v_in[186]
    DIRECTION INPUT ;
    USE SIGNAL ;
    PORT
      LAYER met3 ;
        RECT  0 3069.71 0.8 3070.01 ;
    END
  END ra_forward_sin_v_in[186]
  PIN ra_forward_sin_v_in[187]
    DIRECTION INPUT ;
    USE SIGNAL ;
    PORT
      LAYER met3 ;
        RECT  0 2501.23 0.8 2501.53 ;
    END
  END ra_forward_sin_v_in[187]
  PIN ra_forward_sin_v_in[188]
    DIRECTION INPUT ;
    USE SIGNAL ;
    PORT
      LAYER met3 ;
        RECT  0 2216.99 0.8 2217.29 ;
    END
  END ra_forward_sin_v_in[188]
  PIN ra_forward_sin_v_in[189]
    DIRECTION INPUT ;
    USE SIGNAL ;
    PORT
      LAYER met3 ;
        RECT  0 2057.87 0.8 2058.17 ;
    END
  END ra_forward_sin_v_in[189]
  PIN ra_forward_sin_v_in[18]
    DIRECTION INPUT ;
    USE SIGNAL ;
    PORT
      LAYER met3 ;
        RECT  0 3211.15 0.8 3211.45 ;
    END
  END ra_forward_sin_v_in[18]
  PIN ra_forward_sin_v_in[190]
    DIRECTION INPUT ;
    USE SIGNAL ;
    PORT
      LAYER met3 ;
        RECT  0 2468.59 0.8 2468.89 ;
    END
  END ra_forward_sin_v_in[190]
  PIN ra_forward_sin_v_in[191]
    DIRECTION INPUT ;
    USE SIGNAL ;
    PORT
      LAYER met3 ;
        RECT  0 2794.99 0.8 2795.29 ;
    END
  END ra_forward_sin_v_in[191]
  PIN ra_forward_sin_v_in[192]
    DIRECTION INPUT ;
    USE SIGNAL ;
    PORT
      LAYER met3 ;
        RECT  0 2274.11 0.8 2274.41 ;
    END
  END ra_forward_sin_v_in[192]
  PIN ra_forward_sin_v_in[193]
    DIRECTION INPUT ;
    USE SIGNAL ;
    PORT
      LAYER met3 ;
        RECT  0 2430.51 0.8 2430.81 ;
    END
  END ra_forward_sin_v_in[193]
  PIN ra_forward_sin_v_in[194]
    DIRECTION INPUT ;
    USE SIGNAL ;
    PORT
      LAYER met3 ;
        RECT  0 2078.27 0.8 2078.57 ;
    END
  END ra_forward_sin_v_in[194]
  PIN ra_forward_sin_v_in[195]
    DIRECTION INPUT ;
    USE SIGNAL ;
    PORT
      LAYER met3 ;
        RECT  0 2063.31 0.8 2063.61 ;
    END
  END ra_forward_sin_v_in[195]
  PIN ra_forward_sin_v_in[196]
    DIRECTION INPUT ;
    USE SIGNAL ;
    PORT
      LAYER met3 ;
        RECT  0 2162.59 0.8 2162.89 ;
    END
  END ra_forward_sin_v_in[196]
  PIN ra_forward_sin_v_in[197]
    DIRECTION INPUT ;
    USE SIGNAL ;
    PORT
      LAYER met3 ;
        RECT  0 2414.19 0.8 2414.49 ;
    END
  END ra_forward_sin_v_in[197]
  PIN ra_forward_sin_v_in[198]
    DIRECTION INPUT ;
    USE SIGNAL ;
    PORT
      LAYER met3 ;
        RECT  0 3023.47 0.8 3023.77 ;
    END
  END ra_forward_sin_v_in[198]
  PIN ra_forward_sin_v_in[199]
    DIRECTION INPUT ;
    USE SIGNAL ;
    PORT
      LAYER met3 ;
        RECT  0 2283.63 0.8 2283.93 ;
    END
  END ra_forward_sin_v_in[199]
  PIN ra_forward_sin_v_in[19]
    DIRECTION INPUT ;
    USE SIGNAL ;
    PORT
      LAYER met3 ;
        RECT  0 2691.63 0.8 2691.93 ;
    END
  END ra_forward_sin_v_in[19]
  PIN ra_forward_sin_v_in[1]
    DIRECTION INPUT ;
    USE SIGNAL ;
    PORT
      LAYER met3 ;
        RECT  0 2687.55 0.8 2687.85 ;
    END
  END ra_forward_sin_v_in[1]
  PIN ra_forward_sin_v_in[200]
    DIRECTION INPUT ;
    USE SIGNAL ;
    PORT
      LAYER met3 ;
        RECT  0 2498.51 0.8 2498.81 ;
    END
  END ra_forward_sin_v_in[200]
  PIN ra_forward_sin_v_in[201]
    DIRECTION INPUT ;
    USE SIGNAL ;
    PORT
      LAYER met3 ;
        RECT  0 3219.31 0.8 3219.61 ;
    END
  END ra_forward_sin_v_in[201]
  PIN ra_forward_sin_v_in[202]
    DIRECTION INPUT ;
    USE SIGNAL ;
    PORT
      LAYER met3 ;
        RECT  0 2559.71 0.8 2560.01 ;
    END
  END ra_forward_sin_v_in[202]
  PIN ra_forward_sin_v_in[203]
    DIRECTION INPUT ;
    USE SIGNAL ;
    PORT
      LAYER met3 ;
        RECT  0 2187.07 0.8 2187.37 ;
    END
  END ra_forward_sin_v_in[203]
  PIN ra_forward_sin_v_in[204]
    DIRECTION INPUT ;
    USE SIGNAL ;
    PORT
      LAYER met3 ;
        RECT  0 3046.59 0.8 3046.89 ;
    END
  END ra_forward_sin_v_in[204]
  PIN ra_forward_sin_v_in[205]
    DIRECTION INPUT ;
    USE SIGNAL ;
    PORT
      LAYER met3 ;
        RECT  0 3182.59 0.8 3182.89 ;
    END
  END ra_forward_sin_v_in[205]
  PIN ra_forward_sin_v_in[206]
    DIRECTION INPUT ;
    USE SIGNAL ;
    PORT
      LAYER met3 ;
        RECT  0 2852.11 0.8 2852.41 ;
    END
  END ra_forward_sin_v_in[206]
  PIN ra_forward_sin_v_in[207]
    DIRECTION INPUT ;
    USE SIGNAL ;
    PORT
      LAYER met3 ;
        RECT  0 2755.55 0.8 2755.85 ;
    END
  END ra_forward_sin_v_in[207]
  PIN ra_forward_sin_v_in[208]
    DIRECTION INPUT ;
    USE SIGNAL ;
    PORT
      LAYER met3 ;
        RECT  0 2679.39 0.8 2679.69 ;
    END
  END ra_forward_sin_v_in[208]
  PIN ra_forward_sin_v_in[209]
    DIRECTION INPUT ;
    USE SIGNAL ;
    PORT
      LAYER met3 ;
        RECT  0 2820.83 0.8 2821.13 ;
    END
  END ra_forward_sin_v_in[209]
  PIN ra_forward_sin_v_in[20]
    DIRECTION INPUT ;
    USE SIGNAL ;
    PORT
      LAYER met3 ;
        RECT  0 2174.83 0.8 2175.13 ;
    END
  END ra_forward_sin_v_in[20]
  PIN ra_forward_sin_v_in[210]
    DIRECTION INPUT ;
    USE SIGNAL ;
    PORT
      LAYER met3 ;
        RECT  0 2525.71 0.8 2526.01 ;
    END
  END ra_forward_sin_v_in[210]
  PIN ra_forward_sin_v_in[211]
    DIRECTION INPUT ;
    USE SIGNAL ;
    PORT
      LAYER met3 ;
        RECT  0 2418.27 0.8 2418.57 ;
    END
  END ra_forward_sin_v_in[211]
  PIN ra_forward_sin_v_in[212]
    DIRECTION INPUT ;
    USE SIGNAL ;
    PORT
      LAYER met3 ;
        RECT  0 3212.51 0.8 3212.81 ;
    END
  END ra_forward_sin_v_in[212]
  PIN ra_forward_sin_v_in[213]
    DIRECTION INPUT ;
    USE SIGNAL ;
    PORT
      LAYER met3 ;
        RECT  0 2071.47 0.8 2071.77 ;
    END
  END ra_forward_sin_v_in[213]
  PIN ra_forward_sin_v_in[214]
    DIRECTION INPUT ;
    USE SIGNAL ;
    PORT
      LAYER met3 ;
        RECT  0 3232.91 0.8 3233.21 ;
    END
  END ra_forward_sin_v_in[214]
  PIN ra_forward_sin_v_in[215]
    DIRECTION INPUT ;
    USE SIGNAL ;
    PORT
      LAYER met3 ;
        RECT  0 2826.27 0.8 2826.57 ;
    END
  END ra_forward_sin_v_in[215]
  PIN ra_forward_sin_v_in[216]
    DIRECTION INPUT ;
    USE SIGNAL ;
    PORT
      LAYER met3 ;
        RECT  0 2562.43 0.8 2562.73 ;
    END
  END ra_forward_sin_v_in[216]
  PIN ra_forward_sin_v_in[217]
    DIRECTION INPUT ;
    USE SIGNAL ;
    PORT
      LAYER met3 ;
        RECT  0 2291.79 0.8 2292.09 ;
    END
  END ra_forward_sin_v_in[217]
  PIN ra_forward_sin_v_in[218]
    DIRECTION INPUT ;
    USE SIGNAL ;
    PORT
      LAYER met3 ;
        RECT  0 2660.35 0.8 2660.65 ;
    END
  END ra_forward_sin_v_in[218]
  PIN ra_forward_sin_v_in[219]
    DIRECTION INPUT ;
    USE SIGNAL ;
    PORT
      LAYER met3 ;
        RECT  0 2093.23 0.8 2093.53 ;
    END
  END ra_forward_sin_v_in[219]
  PIN ra_forward_sin_v_in[21]
    DIRECTION INPUT ;
    USE SIGNAL ;
    PORT
      LAYER met3 ;
        RECT  0 3213.87 0.8 3214.17 ;
    END
  END ra_forward_sin_v_in[21]
  PIN ra_forward_sin_v_in[220]
    DIRECTION INPUT ;
    USE SIGNAL ;
    PORT
      LAYER met3 ;
        RECT  0 3098.27 0.8 3098.57 ;
    END
  END ra_forward_sin_v_in[220]
  PIN ra_forward_sin_v_in[221]
    DIRECTION INPUT ;
    USE SIGNAL ;
    PORT
      LAYER met3 ;
        RECT  0 2967.71 0.8 2968.01 ;
    END
  END ra_forward_sin_v_in[221]
  PIN ra_forward_sin_v_in[222]
    DIRECTION INPUT ;
    USE SIGNAL ;
    PORT
      LAYER met3 ;
        RECT  0 2713.39 0.8 2713.69 ;
    END
  END ra_forward_sin_v_in[222]
  PIN ra_forward_sin_v_in[223]
    DIRECTION INPUT ;
    USE SIGNAL ;
    PORT
      LAYER met3 ;
        RECT  0 2688.91 0.8 2689.21 ;
    END
  END ra_forward_sin_v_in[223]
  PIN ra_forward_sin_v_in[224]
    DIRECTION INPUT ;
    USE SIGNAL ;
    PORT
      LAYER met3 ;
        RECT  0 2722.91 0.8 2723.21 ;
    END
  END ra_forward_sin_v_in[224]
  PIN ra_forward_sin_v_in[225]
    DIRECTION INPUT ;
    USE SIGNAL ;
    PORT
      LAYER met3 ;
        RECT  0 3011.23 0.8 3011.53 ;
    END
  END ra_forward_sin_v_in[225]
  PIN ra_forward_sin_v_in[226]
    DIRECTION INPUT ;
    USE SIGNAL ;
    PORT
      LAYER met3 ;
        RECT  0 2994.91 0.8 2995.21 ;
    END
  END ra_forward_sin_v_in[226]
  PIN ra_forward_sin_v_in[227]
    DIRECTION INPUT ;
    USE SIGNAL ;
    PORT
      LAYER met3 ;
        RECT  0 2639.95 0.8 2640.25 ;
    END
  END ra_forward_sin_v_in[227]
  PIN ra_forward_sin_v_in[228]
    DIRECTION INPUT ;
    USE SIGNAL ;
    PORT
      LAYER met3 ;
        RECT  0 3168.99 0.8 3169.29 ;
    END
  END ra_forward_sin_v_in[228]
  PIN ra_forward_sin_v_in[229]
    DIRECTION INPUT ;
    USE SIGNAL ;
    PORT
      LAYER met3 ;
        RECT  0 3124.11 0.8 3124.41 ;
    END
  END ra_forward_sin_v_in[229]
  PIN ra_forward_sin_v_in[22]
    DIRECTION INPUT ;
    USE SIGNAL ;
    PORT
      LAYER met3 ;
        RECT  0 2642.67 0.8 2642.97 ;
    END
  END ra_forward_sin_v_in[22]
  PIN ra_forward_sin_v_in[230]
    DIRECTION INPUT ;
    USE SIGNAL ;
    PORT
      LAYER met3 ;
        RECT  0 2951.39 0.8 2951.69 ;
    END
  END ra_forward_sin_v_in[230]
  PIN ra_forward_sin_v_in[231]
    DIRECTION INPUT ;
    USE SIGNAL ;
    PORT
      LAYER met3 ;
        RECT  0 2479.47 0.8 2479.77 ;
    END
  END ra_forward_sin_v_in[231]
  PIN ra_forward_sin_v_in[232]
    DIRECTION INPUT ;
    USE SIGNAL ;
    PORT
      LAYER met3 ;
        RECT  0 2871.15 0.8 2871.45 ;
    END
  END ra_forward_sin_v_in[232]
  PIN ra_forward_sin_v_in[233]
    DIRECTION INPUT ;
    USE SIGNAL ;
    PORT
      LAYER met3 ;
        RECT  0 2997.63 0.8 2997.93 ;
    END
  END ra_forward_sin_v_in[233]
  PIN ra_forward_sin_v_in[234]
    DIRECTION INPUT ;
    USE SIGNAL ;
    PORT
      LAYER met3 ;
        RECT  0 3149.95 0.8 3150.25 ;
    END
  END ra_forward_sin_v_in[234]
  PIN ra_forward_sin_v_in[235]
    DIRECTION INPUT ;
    USE SIGNAL ;
    PORT
      LAYER met3 ;
        RECT  0 2108.19 0.8 2108.49 ;
    END
  END ra_forward_sin_v_in[235]
  PIN ra_forward_sin_v_in[236]
    DIRECTION INPUT ;
    USE SIGNAL ;
    PORT
      LAYER met3 ;
        RECT  0 3140.43 0.8 3140.73 ;
    END
  END ra_forward_sin_v_in[236]
  PIN ra_forward_sin_v_in[237]
    DIRECTION INPUT ;
    USE SIGNAL ;
    PORT
      LAYER met3 ;
        RECT  0 2695.71 0.8 2696.01 ;
    END
  END ra_forward_sin_v_in[237]
  PIN ra_forward_sin_v_in[238]
    DIRECTION INPUT ;
    USE SIGNAL ;
    PORT
      LAYER met3 ;
        RECT  0 2079.63 0.8 2079.93 ;
    END
  END ra_forward_sin_v_in[238]
  PIN ra_forward_sin_v_in[239]
    DIRECTION INPUT ;
    USE SIGNAL ;
    PORT
      LAYER met3 ;
        RECT  0 2226.51 0.8 2226.81 ;
    END
  END ra_forward_sin_v_in[239]
  PIN ra_forward_sin_v_in[23]
    DIRECTION INPUT ;
    USE SIGNAL ;
    PORT
      LAYER met3 ;
        RECT  0 2882.03 0.8 2882.33 ;
    END
  END ra_forward_sin_v_in[23]
  PIN ra_forward_sin_v_in[240]
    DIRECTION INPUT ;
    USE SIGNAL ;
    PORT
      LAYER met3 ;
        RECT  0 2760.99 0.8 2761.29 ;
    END
  END ra_forward_sin_v_in[240]
  PIN ra_forward_sin_v_in[241]
    DIRECTION INPUT ;
    USE SIGNAL ;
    PORT
      LAYER met3 ;
        RECT  0 3208.43 0.8 3208.73 ;
    END
  END ra_forward_sin_v_in[241]
  PIN ra_forward_sin_v_in[242]
    DIRECTION INPUT ;
    USE SIGNAL ;
    PORT
      LAYER met3 ;
        RECT  0 2605.95 0.8 2606.25 ;
    END
  END ra_forward_sin_v_in[242]
  PIN ra_forward_sin_v_in[243]
    DIRECTION INPUT ;
    USE SIGNAL ;
    PORT
      LAYER met3 ;
        RECT  0 2420.99 0.8 2421.29 ;
    END
  END ra_forward_sin_v_in[243]
  PIN ra_forward_sin_v_in[244]
    DIRECTION INPUT ;
    USE SIGNAL ;
    PORT
      LAYER met3 ;
        RECT  0 2422.35 0.8 2422.65 ;
    END
  END ra_forward_sin_v_in[244]
  PIN ra_forward_sin_v_in[245]
    DIRECTION INPUT ;
    USE SIGNAL ;
    PORT
      LAYER met3 ;
        RECT  0 2425.07 0.8 2425.37 ;
    END
  END ra_forward_sin_v_in[245]
  PIN ra_forward_sin_v_in[246]
    DIRECTION INPUT ;
    USE SIGNAL ;
    PORT
      LAYER met3 ;
        RECT  0 3087.39 0.8 3087.69 ;
    END
  END ra_forward_sin_v_in[246]
  PIN ra_forward_sin_v_in[247]
    DIRECTION INPUT ;
    USE SIGNAL ;
    PORT
      LAYER met3 ;
        RECT  0 2467.23 0.8 2467.53 ;
    END
  END ra_forward_sin_v_in[247]
  PIN ra_forward_sin_v_in[248]
    DIRECTION INPUT ;
    USE SIGNAL ;
    PORT
      LAYER met3 ;
        RECT  0 2070.11 0.8 2070.41 ;
    END
  END ra_forward_sin_v_in[248]
  PIN ra_forward_sin_v_in[249]
    DIRECTION INPUT ;
    USE SIGNAL ;
    PORT
      LAYER met3 ;
        RECT  0 3071.07 0.8 3071.37 ;
    END
  END ra_forward_sin_v_in[249]
  PIN ra_forward_sin_v_in[24]
    DIRECTION INPUT ;
    USE SIGNAL ;
    PORT
      LAYER met3 ;
        RECT  0 2856.19 0.8 2856.49 ;
    END
  END ra_forward_sin_v_in[24]
  PIN ra_forward_sin_v_in[250]
    DIRECTION INPUT ;
    USE SIGNAL ;
    PORT
      LAYER met3 ;
        RECT  0 3080.59 0.8 3080.89 ;
    END
  END ra_forward_sin_v_in[250]
  PIN ra_forward_sin_v_in[251]
    DIRECTION INPUT ;
    USE SIGNAL ;
    PORT
      LAYER met3 ;
        RECT  0 2310.83 0.8 2311.13 ;
    END
  END ra_forward_sin_v_in[251]
  PIN ra_forward_sin_v_in[252]
    DIRECTION INPUT ;
    USE SIGNAL ;
    PORT
      LAYER met3 ;
        RECT  0 3049.31 0.8 3049.61 ;
    END
  END ra_forward_sin_v_in[252]
  PIN ra_forward_sin_v_in[253]
    DIRECTION INPUT ;
    USE SIGNAL ;
    PORT
      LAYER met3 ;
        RECT  0 2697.07 0.8 2697.37 ;
    END
  END ra_forward_sin_v_in[253]
  PIN ra_forward_sin_v_in[254]
    DIRECTION INPUT ;
    USE SIGNAL ;
    PORT
      LAYER met3 ;
        RECT  0 2714.75 0.8 2715.05 ;
    END
  END ra_forward_sin_v_in[254]
  PIN ra_forward_sin_v_in[255]
    DIRECTION INPUT ;
    USE SIGNAL ;
    PORT
      LAYER met3 ;
        RECT  0 2842.59 0.8 2842.89 ;
    END
  END ra_forward_sin_v_in[255]
  PIN ra_forward_sin_v_in[25]
    DIRECTION INPUT ;
    USE SIGNAL ;
    PORT
      LAYER met3 ;
        RECT  0 2445.47 0.8 2445.77 ;
    END
  END ra_forward_sin_v_in[25]
  PIN ra_forward_sin_v_in[26]
    DIRECTION INPUT ;
    USE SIGNAL ;
    PORT
      LAYER met3 ;
        RECT  0 2770.51 0.8 2770.81 ;
    END
  END ra_forward_sin_v_in[26]
  PIN ra_forward_sin_v_in[27]
    DIRECTION INPUT ;
    USE SIGNAL ;
    PORT
      LAYER met3 ;
        RECT  0 2094.59 0.8 2094.89 ;
    END
  END ra_forward_sin_v_in[27]
  PIN ra_forward_sin_v_in[28]
    DIRECTION INPUT ;
    USE SIGNAL ;
    PORT
      LAYER met3 ;
        RECT  0 2367.95 0.8 2368.25 ;
    END
  END ra_forward_sin_v_in[28]
  PIN ra_forward_sin_v_in[29]
    DIRECTION INPUT ;
    USE SIGNAL ;
    PORT
      LAYER met3 ;
        RECT  0 3042.51 0.8 3042.81 ;
    END
  END ra_forward_sin_v_in[29]
  PIN ra_forward_sin_v_in[2]
    DIRECTION INPUT ;
    USE SIGNAL ;
    PORT
      LAYER met3 ;
        RECT  0 2419.63 0.8 2419.93 ;
    END
  END ra_forward_sin_v_in[2]
  PIN ra_forward_sin_v_in[30]
    DIRECTION INPUT ;
    USE SIGNAL ;
    PORT
      LAYER met3 ;
        RECT  0 2902.43 0.8 2902.73 ;
    END
  END ra_forward_sin_v_in[30]
  PIN ra_forward_sin_v_in[31]
    DIRECTION INPUT ;
    USE SIGNAL ;
    PORT
      LAYER met3 ;
        RECT  0 2831.71 0.8 2832.01 ;
    END
  END ra_forward_sin_v_in[31]
  PIN ra_forward_sin_v_in[32]
    DIRECTION INPUT ;
    USE SIGNAL ;
    PORT
      LAYER met3 ;
        RECT  0 2427.79 0.8 2428.09 ;
    END
  END ra_forward_sin_v_in[32]
  PIN ra_forward_sin_v_in[33]
    DIRECTION INPUT ;
    USE SIGNAL ;
    PORT
      LAYER met3 ;
        RECT  0 3111.87 0.8 3112.17 ;
    END
  END ra_forward_sin_v_in[33]
  PIN ra_forward_sin_v_in[34]
    DIRECTION INPUT ;
    USE SIGNAL ;
    PORT
      LAYER met3 ;
        RECT  0 2086.43 0.8 2086.73 ;
    END
  END ra_forward_sin_v_in[34]
  PIN ra_forward_sin_v_in[35]
    DIRECTION INPUT ;
    USE SIGNAL ;
    PORT
      LAYER met3 ;
        RECT  0 2767.79 0.8 2768.09 ;
    END
  END ra_forward_sin_v_in[35]
  PIN ra_forward_sin_v_in[36]
    DIRECTION INPUT ;
    USE SIGNAL ;
    PORT
      LAYER met3 ;
        RECT  0 2565.15 0.8 2565.45 ;
    END
  END ra_forward_sin_v_in[36]
  PIN ra_forward_sin_v_in[37]
    DIRECTION INPUT ;
    USE SIGNAL ;
    PORT
      LAYER met3 ;
        RECT  0 2929.63 0.8 2929.93 ;
    END
  END ra_forward_sin_v_in[37]
  PIN ra_forward_sin_v_in[38]
    DIRECTION INPUT ;
    USE SIGNAL ;
    PORT
      LAYER met3 ;
        RECT  0 2830.35 0.8 2830.65 ;
    END
  END ra_forward_sin_v_in[38]
  PIN ra_forward_sin_v_in[39]
    DIRECTION INPUT ;
    USE SIGNAL ;
    PORT
      LAYER met3 ;
        RECT  0 3205.71 0.8 3206.01 ;
    END
  END ra_forward_sin_v_in[39]
  PIN ra_forward_sin_v_in[3]
    DIRECTION INPUT ;
    USE SIGNAL ;
    PORT
      LAYER met3 ;
        RECT  0 2087.79 0.8 2088.09 ;
    END
  END ra_forward_sin_v_in[3]
  PIN ra_forward_sin_v_in[40]
    DIRECTION INPUT ;
    USE SIGNAL ;
    PORT
      LAYER met3 ;
        RECT  0 3041.15 0.8 3041.45 ;
    END
  END ra_forward_sin_v_in[40]
  PIN ra_forward_sin_v_in[41]
    DIRECTION INPUT ;
    USE SIGNAL ;
    PORT
      LAYER met3 ;
        RECT  0 2075.55 0.8 2075.85 ;
    END
  END ra_forward_sin_v_in[41]
  PIN ra_forward_sin_v_in[42]
    DIRECTION INPUT ;
    USE SIGNAL ;
    PORT
      LAYER met3 ;
        RECT  0 3186.67 0.8 3186.97 ;
    END
  END ra_forward_sin_v_in[42]
  PIN ra_forward_sin_v_in[43]
    DIRECTION INPUT ;
    USE SIGNAL ;
    PORT
      LAYER met3 ;
        RECT  0 2287.71 0.8 2288.01 ;
    END
  END ra_forward_sin_v_in[43]
  PIN ra_forward_sin_v_in[44]
    DIRECTION INPUT ;
    USE SIGNAL ;
    PORT
      LAYER met3 ;
        RECT  0 3139.07 0.8 3139.37 ;
    END
  END ra_forward_sin_v_in[44]
  PIN ra_forward_sin_v_in[45]
    DIRECTION INPUT ;
    USE SIGNAL ;
    PORT
      LAYER met3 ;
        RECT  0 2629.07 0.8 2629.37 ;
    END
  END ra_forward_sin_v_in[45]
  PIN ra_forward_sin_v_in[46]
    DIRECTION INPUT ;
    USE SIGNAL ;
    PORT
      LAYER met3 ;
        RECT  0 3001.71 0.8 3002.01 ;
    END
  END ra_forward_sin_v_in[46]
  PIN ra_forward_sin_v_in[47]
    DIRECTION INPUT ;
    USE SIGNAL ;
    PORT
      LAYER met3 ;
        RECT  0 2309.47 0.8 2309.77 ;
    END
  END ra_forward_sin_v_in[47]
  PIN ra_forward_sin_v_in[48]
    DIRECTION INPUT ;
    USE SIGNAL ;
    PORT
      LAYER met3 ;
        RECT  0 2083.71 0.8 2084.01 ;
    END
  END ra_forward_sin_v_in[48]
  PIN ra_forward_sin_v_in[49]
    DIRECTION INPUT ;
    USE SIGNAL ;
    PORT
      LAYER met3 ;
        RECT  0 2474.03 0.8 2474.33 ;
    END
  END ra_forward_sin_v_in[49]
  PIN ra_forward_sin_v_in[4]
    DIRECTION INPUT ;
    USE SIGNAL ;
    PORT
      LAYER met3 ;
        RECT  0 2741.95 0.8 2742.25 ;
    END
  END ra_forward_sin_v_in[4]
  PIN ra_forward_sin_v_in[50]
    DIRECTION INPUT ;
    USE SIGNAL ;
    PORT
      LAYER met3 ;
        RECT  0 2294.51 0.8 2294.81 ;
    END
  END ra_forward_sin_v_in[50]
  PIN ra_forward_sin_v_in[51]
    DIRECTION INPUT ;
    USE SIGNAL ;
    PORT
      LAYER met3 ;
        RECT  0 2762.35 0.8 2762.65 ;
    END
  END ra_forward_sin_v_in[51]
  PIN ra_forward_sin_v_in[52]
    DIRECTION INPUT ;
    USE SIGNAL ;
    PORT
      LAYER met3 ;
        RECT  0 2293.15 0.8 2293.45 ;
    END
  END ra_forward_sin_v_in[52]
  PIN ra_forward_sin_v_in[53]
    DIRECTION INPUT ;
    USE SIGNAL ;
    PORT
      LAYER met3 ;
        RECT  0 2848.03 0.8 2848.33 ;
    END
  END ra_forward_sin_v_in[53]
  PIN ra_forward_sin_v_in[54]
    DIRECTION INPUT ;
    USE SIGNAL ;
    PORT
      LAYER met3 ;
        RECT  0 2074.19 0.8 2074.49 ;
    END
  END ra_forward_sin_v_in[54]
  PIN ra_forward_sin_v_in[55]
    DIRECTION INPUT ;
    USE SIGNAL ;
    PORT
      LAYER met3 ;
        RECT  0 2935.07 0.8 2935.37 ;
    END
  END ra_forward_sin_v_in[55]
  PIN ra_forward_sin_v_in[56]
    DIRECTION INPUT ;
    USE SIGNAL ;
    PORT
      LAYER met3 ;
        RECT  0 2185.71 0.8 2186.01 ;
    END
  END ra_forward_sin_v_in[56]
  PIN ra_forward_sin_v_in[57]
    DIRECTION INPUT ;
    USE SIGNAL ;
    PORT
      LAYER met3 ;
        RECT  0 2633.15 0.8 2633.45 ;
    END
  END ra_forward_sin_v_in[57]
  PIN ra_forward_sin_v_in[58]
    DIRECTION INPUT ;
    USE SIGNAL ;
    PORT
      LAYER met3 ;
        RECT  0 3166.27 0.8 3166.57 ;
    END
  END ra_forward_sin_v_in[58]
  PIN ra_forward_sin_v_in[59]
    DIRECTION INPUT ;
    USE SIGNAL ;
    PORT
      LAYER met3 ;
        RECT  0 2351.63 0.8 2351.93 ;
    END
  END ra_forward_sin_v_in[59]
  PIN ra_forward_sin_v_in[5]
    DIRECTION INPUT ;
    USE SIGNAL ;
    PORT
      LAYER met3 ;
        RECT  0 2306.75 0.8 2307.05 ;
    END
  END ra_forward_sin_v_in[5]
  PIN ra_forward_sin_v_in[60]
    DIRECTION INPUT ;
    USE SIGNAL ;
    PORT
      LAYER met3 ;
        RECT  0 2114.99 0.8 2115.29 ;
    END
  END ra_forward_sin_v_in[60]
  PIN ra_forward_sin_v_in[61]
    DIRECTION INPUT ;
    USE SIGNAL ;
    PORT
      LAYER met3 ;
        RECT  0 2924.19 0.8 2924.49 ;
    END
  END ra_forward_sin_v_in[61]
  PIN ra_forward_sin_v_in[62]
    DIRECTION INPUT ;
    USE SIGNAL ;
    PORT
      LAYER met3 ;
        RECT  0 2486.27 0.8 2486.57 ;
    END
  END ra_forward_sin_v_in[62]
  PIN ra_forward_sin_v_in[63]
    DIRECTION INPUT ;
    USE SIGNAL ;
    PORT
      LAYER met3 ;
        RECT  0 2532.51 0.8 2532.81 ;
    END
  END ra_forward_sin_v_in[63]
  PIN ra_forward_sin_v_in[64]
    DIRECTION INPUT ;
    USE SIGNAL ;
    PORT
      LAYER met3 ;
        RECT  0 2446.83 0.8 2447.13 ;
    END
  END ra_forward_sin_v_in[64]
  PIN ra_forward_sin_v_in[65]
    DIRECTION INPUT ;
    USE SIGNAL ;
    PORT
      LAYER met3 ;
        RECT  0 3094.19 0.8 3094.49 ;
    END
  END ra_forward_sin_v_in[65]
  PIN ra_forward_sin_v_in[66]
    DIRECTION INPUT ;
    USE SIGNAL ;
    PORT
      LAYER met3 ;
        RECT  0 3137.71 0.8 3138.01 ;
    END
  END ra_forward_sin_v_in[66]
  PIN ra_forward_sin_v_in[67]
    DIRECTION INPUT ;
    USE SIGNAL ;
    PORT
      LAYER met3 ;
        RECT  0 2726.99 0.8 2727.29 ;
    END
  END ra_forward_sin_v_in[67]
  PIN ra_forward_sin_v_in[68]
    DIRECTION INPUT ;
    USE SIGNAL ;
    PORT
      LAYER met3 ;
        RECT  0 2577.39 0.8 2577.69 ;
    END
  END ra_forward_sin_v_in[68]
  PIN ra_forward_sin_v_in[69]
    DIRECTION INPUT ;
    USE SIGNAL ;
    PORT
      LAYER met3 ;
        RECT  0 3220.67 0.8 3220.97 ;
    END
  END ra_forward_sin_v_in[69]
  PIN ra_forward_sin_v_in[6]
    DIRECTION INPUT ;
    USE SIGNAL ;
    PORT
      LAYER met3 ;
        RECT  0 2212.91 0.8 2213.21 ;
    END
  END ra_forward_sin_v_in[6]
  PIN ra_forward_sin_v_in[70]
    DIRECTION INPUT ;
    USE SIGNAL ;
    PORT
      LAYER met3 ;
        RECT  0 2880.67 0.8 2880.97 ;
    END
  END ra_forward_sin_v_in[70]
  PIN ra_forward_sin_v_in[71]
    DIRECTION INPUT ;
    USE SIGNAL ;
    PORT
      LAYER met3 ;
        RECT  0 3217.95 0.8 3218.25 ;
    END
  END ra_forward_sin_v_in[71]
  PIN ra_forward_sin_v_in[72]
    DIRECTION INPUT ;
    USE SIGNAL ;
    PORT
      LAYER met3 ;
        RECT  0 2634.51 0.8 2634.81 ;
    END
  END ra_forward_sin_v_in[72]
  PIN ra_forward_sin_v_in[73]
    DIRECTION INPUT ;
    USE SIGNAL ;
    PORT
      LAYER met3 ;
        RECT  0 2444.11 0.8 2444.41 ;
    END
  END ra_forward_sin_v_in[73]
  PIN ra_forward_sin_v_in[74]
    DIRECTION INPUT ;
    USE SIGNAL ;
    PORT
      LAYER met3 ;
        RECT  0 2448.19 0.8 2448.49 ;
    END
  END ra_forward_sin_v_in[74]
  PIN ra_forward_sin_v_in[75]
    DIRECTION INPUT ;
    USE SIGNAL ;
    PORT
      LAYER met3 ;
        RECT  0 2416.91 0.8 2417.21 ;
    END
  END ra_forward_sin_v_in[75]
  PIN ra_forward_sin_v_in[76]
    DIRECTION INPUT ;
    USE SIGNAL ;
    PORT
      LAYER met3 ;
        RECT  0 2903.79 0.8 2904.09 ;
    END
  END ra_forward_sin_v_in[76]
  PIN ra_forward_sin_v_in[77]
    DIRECTION INPUT ;
    USE SIGNAL ;
    PORT
      LAYER met3 ;
        RECT  0 2189.79 0.8 2190.09 ;
    END
  END ra_forward_sin_v_in[77]
  PIN ra_forward_sin_v_in[78]
    DIRECTION INPUT ;
    USE SIGNAL ;
    PORT
      LAYER met3 ;
        RECT  0 3068.35 0.8 3068.65 ;
    END
  END ra_forward_sin_v_in[78]
  PIN ra_forward_sin_v_in[79]
    DIRECTION INPUT ;
    USE SIGNAL ;
    PORT
      LAYER met3 ;
        RECT  0 2857.55 0.8 2857.85 ;
    END
  END ra_forward_sin_v_in[79]
  PIN ra_forward_sin_v_in[7]
    DIRECTION INPUT ;
    USE SIGNAL ;
    PORT
      LAYER met3 ;
        RECT  0 3015.31 0.8 3015.61 ;
    END
  END ra_forward_sin_v_in[7]
  PIN ra_forward_sin_v_in[80]
    DIRECTION INPUT ;
    USE SIGNAL ;
    PORT
      LAYER met3 ;
        RECT  0 2943.23 0.8 2943.53 ;
    END
  END ra_forward_sin_v_in[80]
  PIN ra_forward_sin_v_in[81]
    DIRECTION INPUT ;
    USE SIGNAL ;
    PORT
      LAYER met3 ;
        RECT  0 2735.15 0.8 2735.45 ;
    END
  END ra_forward_sin_v_in[81]
  PIN ra_forward_sin_v_in[82]
    DIRECTION INPUT ;
    USE SIGNAL ;
    PORT
      LAYER met3 ;
        RECT  0 2163.95 0.8 2164.25 ;
    END
  END ra_forward_sin_v_in[82]
  PIN ra_forward_sin_v_in[83]
    DIRECTION INPUT ;
    USE SIGNAL ;
    PORT
      LAYER met3 ;
        RECT  0 3192.11 0.8 3192.41 ;
    END
  END ra_forward_sin_v_in[83]
  PIN ra_forward_sin_v_in[84]
    DIRECTION INPUT ;
    USE SIGNAL ;
    PORT
      LAYER met3 ;
        RECT  0 2592.35 0.8 2592.65 ;
    END
  END ra_forward_sin_v_in[84]
  PIN ra_forward_sin_v_in[85]
    DIRECTION INPUT ;
    USE SIGNAL ;
    PORT
      LAYER met3 ;
        RECT  0 2771.87 0.8 2772.17 ;
    END
  END ra_forward_sin_v_in[85]
  PIN ra_forward_sin_v_in[86]
    DIRECTION INPUT ;
    USE SIGNAL ;
    PORT
      LAYER met3 ;
        RECT  0 3113.23 0.8 3113.53 ;
    END
  END ra_forward_sin_v_in[86]
  PIN ra_forward_sin_v_in[87]
    DIRECTION INPUT ;
    USE SIGNAL ;
    PORT
      LAYER met3 ;
        RECT  0 2796.35 0.8 2796.65 ;
    END
  END ra_forward_sin_v_in[87]
  PIN ra_forward_sin_v_in[88]
    DIRECTION INPUT ;
    USE SIGNAL ;
    PORT
      LAYER met3 ;
        RECT  0 3228.83 0.8 3229.13 ;
    END
  END ra_forward_sin_v_in[88]
  PIN ra_forward_sin_v_in[89]
    DIRECTION INPUT ;
    USE SIGNAL ;
    PORT
      LAYER met3 ;
        RECT  0 3144.51 0.8 3144.81 ;
    END
  END ra_forward_sin_v_in[89]
  PIN ra_forward_sin_v_in[8]
    DIRECTION INPUT ;
    USE SIGNAL ;
    PORT
      LAYER met3 ;
        RECT  0 2238.75 0.8 2239.05 ;
    END
  END ra_forward_sin_v_in[8]
  PIN ra_forward_sin_v_in[90]
    DIRECTION INPUT ;
    USE SIGNAL ;
    PORT
      LAYER met3 ;
        RECT  0 2259.15 0.8 2259.45 ;
    END
  END ra_forward_sin_v_in[90]
  PIN ra_forward_sin_v_in[91]
    DIRECTION INPUT ;
    USE SIGNAL ;
    PORT
      LAYER met3 ;
        RECT  0 2615.47 0.8 2615.77 ;
    END
  END ra_forward_sin_v_in[91]
  PIN ra_forward_sin_v_in[92]
    DIRECTION INPUT ;
    USE SIGNAL ;
    PORT
      LAYER met3 ;
        RECT  0 2234.67 0.8 2234.97 ;
    END
  END ra_forward_sin_v_in[92]
  PIN ra_forward_sin_v_in[93]
    DIRECTION INPUT ;
    USE SIGNAL ;
    PORT
      LAYER met3 ;
        RECT  0 2068.75 0.8 2069.05 ;
    END
  END ra_forward_sin_v_in[93]
  PIN ra_forward_sin_v_in[94]
    DIRECTION INPUT ;
    USE SIGNAL ;
    PORT
      LAYER met3 ;
        RECT  0 2984.03 0.8 2984.33 ;
    END
  END ra_forward_sin_v_in[94]
  PIN ra_forward_sin_v_in[95]
    DIRECTION INPUT ;
    USE SIGNAL ;
    PORT
      LAYER met3 ;
        RECT  0 2824.91 0.8 2825.21 ;
    END
  END ra_forward_sin_v_in[95]
  PIN ra_forward_sin_v_in[96]
    DIRECTION INPUT ;
    USE SIGNAL ;
    PORT
      LAYER met3 ;
        RECT  0 2867.07 0.8 2867.37 ;
    END
  END ra_forward_sin_v_in[96]
  PIN ra_forward_sin_v_in[97]
    DIRECTION INPUT ;
    USE SIGNAL ;
    PORT
      LAYER met3 ;
        RECT  0 2072.83 0.8 2073.13 ;
    END
  END ra_forward_sin_v_in[97]
  PIN ra_forward_sin_v_in[98]
    DIRECTION INPUT ;
    USE SIGNAL ;
    PORT
      LAYER met3 ;
        RECT  0 2544.75 0.8 2545.05 ;
    END
  END ra_forward_sin_v_in[98]
  PIN ra_forward_sin_v_in[99]
    DIRECTION INPUT ;
    USE SIGNAL ;
    PORT
      LAYER met3 ;
        RECT  0 2648.11 0.8 2648.41 ;
    END
  END ra_forward_sin_v_in[99]
  PIN ra_forward_sin_v_in[9]
    DIRECTION INPUT ;
    USE SIGNAL ;
    PORT
      LAYER met3 ;
        RECT  0 2610.03 0.8 2610.33 ;
    END
  END ra_forward_sin_v_in[9]
  PIN ra_forward_sin_valid_in
    DIRECTION INPUT ;
    USE SIGNAL ;
    PORT
      LAYER met3 ;
        RECT  0 1996.67 0.8 1996.97 ;
    END
  END ra_forward_sin_valid_in
  PIN ra_read_cos_forwarded_empty_out
    DIRECTION OUTPUT ;
    USE SIGNAL ;
    PORT
      LAYER met3 ;
        RECT  2999.2 1577.79 3000 1578.09 ;
    END
  END ra_read_cos_forwarded_empty_out
  PIN ra_read_cos_forwarded_phase_in[0]
    DIRECTION INPUT ;
    USE SIGNAL ;
    PORT
      LAYER met3 ;
        RECT  2999.2 710.11 3000 710.41 ;
    END
  END ra_read_cos_forwarded_phase_in[0]
  PIN ra_read_cos_forwarded_phase_in[1]
    DIRECTION INPUT ;
    USE SIGNAL ;
    PORT
      LAYER met3 ;
        RECT  2999.2 659.79 3000 660.09 ;
    END
  END ra_read_cos_forwarded_phase_in[1]
  PIN ra_read_cos_forwarded_rden_in
    DIRECTION INPUT ;
    USE SIGNAL ;
    PORT
      LAYER met3 ;
        RECT  2999.2 1532.91 3000 1533.21 ;
    END
  END ra_read_cos_forwarded_rden_in
  PIN ra_read_cos_forwarded_rdy_out
    DIRECTION OUTPUT ;
    USE SIGNAL ;
    PORT
      LAYER met3 ;
        RECT  2999.2 1561.47 3000 1561.77 ;
    END
  END ra_read_cos_forwarded_rdy_out
  PIN ra_read_cos_forwarded_result_out[0]
    DIRECTION OUTPUT ;
    USE SIGNAL ;
    PORT
      LAYER met3 ;
        RECT  2999.2 261.31 3000 261.61 ;
    END
  END ra_read_cos_forwarded_result_out[0]
  PIN ra_read_cos_forwarded_result_out[100]
    DIRECTION OUTPUT ;
    USE SIGNAL ;
    PORT
      LAYER met3 ;
        RECT  2999.2 968.51 3000 968.81 ;
    END
  END ra_read_cos_forwarded_result_out[100]
  PIN ra_read_cos_forwarded_result_out[101]
    DIRECTION OUTPUT ;
    USE SIGNAL ;
    PORT
      LAYER met3 ;
        RECT  2999.2 888.27 3000 888.57 ;
    END
  END ra_read_cos_forwarded_result_out[101]
  PIN ra_read_cos_forwarded_result_out[102]
    DIRECTION OUTPUT ;
    USE SIGNAL ;
    PORT
      LAYER met3 ;
        RECT  2999.2 986.19 3000 986.49 ;
    END
  END ra_read_cos_forwarded_result_out[102]
  PIN ra_read_cos_forwarded_result_out[103]
    DIRECTION OUTPUT ;
    USE SIGNAL ;
    PORT
      LAYER met3 ;
        RECT  2999.2 1218.75 3000 1219.05 ;
    END
  END ra_read_cos_forwarded_result_out[103]
  PIN ra_read_cos_forwarded_result_out[104]
    DIRECTION OUTPUT ;
    USE SIGNAL ;
    PORT
      LAYER met3 ;
        RECT  2999.2 1477.15 3000 1477.45 ;
    END
  END ra_read_cos_forwarded_result_out[104]
  PIN ra_read_cos_forwarded_result_out[105]
    DIRECTION OUTPUT ;
    USE SIGNAL ;
    PORT
      LAYER met3 ;
        RECT  2999.2 497.95 3000 498.25 ;
    END
  END ra_read_cos_forwarded_result_out[105]
  PIN ra_read_cos_forwarded_result_out[106]
    DIRECTION OUTPUT ;
    USE SIGNAL ;
    PORT
      LAYER met3 ;
        RECT  2999.2 361.95 3000 362.25 ;
    END
  END ra_read_cos_forwarded_result_out[106]
  PIN ra_read_cos_forwarded_result_out[107]
    DIRECTION OUTPUT ;
    USE SIGNAL ;
    PORT
      LAYER met3 ;
        RECT  2999.2 1041.95 3000 1042.25 ;
    END
  END ra_read_cos_forwarded_result_out[107]
  PIN ra_read_cos_forwarded_result_out[108]
    DIRECTION OUTPUT ;
    USE SIGNAL ;
    PORT
      LAYER met3 ;
        RECT  2999.2 189.23 3000 189.53 ;
    END
  END ra_read_cos_forwarded_result_out[108]
  PIN ra_read_cos_forwarded_result_out[109]
    DIRECTION OUTPUT ;
    USE SIGNAL ;
    PORT
      LAYER met3 ;
        RECT  2999.2 965.79 3000 966.09 ;
    END
  END ra_read_cos_forwarded_result_out[109]
  PIN ra_read_cos_forwarded_result_out[10]
    DIRECTION OUTPUT ;
    USE SIGNAL ;
    PORT
      LAYER met3 ;
        RECT  2999.2 268.11 3000 268.41 ;
    END
  END ra_read_cos_forwarded_result_out[10]
  PIN ra_read_cos_forwarded_result_out[110]
    DIRECTION OUTPUT ;
    USE SIGNAL ;
    PORT
      LAYER met3 ;
        RECT  2999.2 1373.79 3000 1374.09 ;
    END
  END ra_read_cos_forwarded_result_out[110]
  PIN ra_read_cos_forwarded_result_out[111]
    DIRECTION OUTPUT ;
    USE SIGNAL ;
    PORT
      LAYER met3 ;
        RECT  2999.2 867.87 3000 868.17 ;
    END
  END ra_read_cos_forwarded_result_out[111]
  PIN ra_read_cos_forwarded_result_out[112]
    DIRECTION OUTPUT ;
    USE SIGNAL ;
    PORT
      LAYER met3 ;
        RECT  2999.2 1032.43 3000 1032.73 ;
    END
  END ra_read_cos_forwarded_result_out[112]
  PIN ra_read_cos_forwarded_result_out[113]
    DIRECTION OUTPUT ;
    USE SIGNAL ;
    PORT
      LAYER met3 ;
        RECT  2999.2 643.47 3000 643.77 ;
    END
  END ra_read_cos_forwarded_result_out[113]
  PIN ra_read_cos_forwarded_result_out[114]
    DIRECTION OUTPUT ;
    USE SIGNAL ;
    PORT
      LAYER met3 ;
        RECT  2999.2 699.23 3000 699.53 ;
    END
  END ra_read_cos_forwarded_result_out[114]
  PIN ra_read_cos_forwarded_result_out[115]
    DIRECTION OUTPUT ;
    USE SIGNAL ;
    PORT
      LAYER met3 ;
        RECT  2999.2 1289.47 3000 1289.77 ;
    END
  END ra_read_cos_forwarded_result_out[115]
  PIN ra_read_cos_forwarded_result_out[116]
    DIRECTION OUTPUT ;
    USE SIGNAL ;
    PORT
      LAYER met3 ;
        RECT  2999.2 904.59 3000 904.89 ;
    END
  END ra_read_cos_forwarded_result_out[116]
  PIN ra_read_cos_forwarded_result_out[117]
    DIRECTION OUTPUT ;
    USE SIGNAL ;
    PORT
      LAYER met3 ;
        RECT  2999.2 170.19 3000 170.49 ;
    END
  END ra_read_cos_forwarded_result_out[117]
  PIN ra_read_cos_forwarded_result_out[118]
    DIRECTION OUTPUT ;
    USE SIGNAL ;
    PORT
      LAYER met3 ;
        RECT  2999.2 578.19 3000 578.49 ;
    END
  END ra_read_cos_forwarded_result_out[118]
  PIN ra_read_cos_forwarded_result_out[119]
    DIRECTION OUTPUT ;
    USE SIGNAL ;
    PORT
      LAYER met3 ;
        RECT  2999.2 455.79 3000 456.09 ;
    END
  END ra_read_cos_forwarded_result_out[119]
  PIN ra_read_cos_forwarded_result_out[11]
    DIRECTION OUTPUT ;
    USE SIGNAL ;
    PORT
      LAYER met3 ;
        RECT  2999.2 613.55 3000 613.85 ;
    END
  END ra_read_cos_forwarded_result_out[11]
  PIN ra_read_cos_forwarded_result_out[120]
    DIRECTION OUTPUT ;
    USE SIGNAL ;
    PORT
      LAYER met3 ;
        RECT  2999.2 439.47 3000 439.77 ;
    END
  END ra_read_cos_forwarded_result_out[120]
  PIN ra_read_cos_forwarded_result_out[121]
    DIRECTION OUTPUT ;
    USE SIGNAL ;
    PORT
      LAYER met3 ;
        RECT  2999.2 390.51 3000 390.81 ;
    END
  END ra_read_cos_forwarded_result_out[121]
  PIN ra_read_cos_forwarded_result_out[122]
    DIRECTION OUTPUT ;
    USE SIGNAL ;
    PORT
      LAYER met3 ;
        RECT  2999.2 283.07 3000 283.37 ;
    END
  END ra_read_cos_forwarded_result_out[122]
  PIN ra_read_cos_forwarded_result_out[123]
    DIRECTION OUTPUT ;
    USE SIGNAL ;
    PORT
      LAYER met3 ;
        RECT  2999.2 272.19 3000 272.49 ;
    END
  END ra_read_cos_forwarded_result_out[123]
  PIN ra_read_cos_forwarded_result_out[124]
    DIRECTION OUTPUT ;
    USE SIGNAL ;
    PORT
      LAYER met3 ;
        RECT  2999.2 897.79 3000 898.09 ;
    END
  END ra_read_cos_forwarded_result_out[124]
  PIN ra_read_cos_forwarded_result_out[125]
    DIRECTION OUTPUT ;
    USE SIGNAL ;
    PORT
      LAYER met3 ;
        RECT  2999.2 919.55 3000 919.85 ;
    END
  END ra_read_cos_forwarded_result_out[125]
  PIN ra_read_cos_forwarded_result_out[126]
    DIRECTION OUTPUT ;
    USE SIGNAL ;
    PORT
      LAYER met3 ;
        RECT  2999.2 920.91 3000 921.21 ;
    END
  END ra_read_cos_forwarded_result_out[126]
  PIN ra_read_cos_forwarded_result_out[127]
    DIRECTION OUTPUT ;
    USE SIGNAL ;
    PORT
      LAYER met3 ;
        RECT  2999.2 1475.79 3000 1476.09 ;
    END
  END ra_read_cos_forwarded_result_out[127]
  PIN ra_read_cos_forwarded_result_out[128]
    DIRECTION OUTPUT ;
    USE SIGNAL ;
    PORT
      LAYER met3 ;
        RECT  2999.2 1264.99 3000 1265.29 ;
    END
  END ra_read_cos_forwarded_result_out[128]
  PIN ra_read_cos_forwarded_result_out[129]
    DIRECTION OUTPUT ;
    USE SIGNAL ;
    PORT
      LAYER met3 ;
        RECT  2999.2 1024.27 3000 1024.57 ;
    END
  END ra_read_cos_forwarded_result_out[129]
  PIN ra_read_cos_forwarded_result_out[12]
    DIRECTION OUTPUT ;
    USE SIGNAL ;
    PORT
      LAYER met3 ;
        RECT  2999.2 325.23 3000 325.53 ;
    END
  END ra_read_cos_forwarded_result_out[12]
  PIN ra_read_cos_forwarded_result_out[130]
    DIRECTION OUTPUT ;
    USE SIGNAL ;
    PORT
      LAYER met3 ;
        RECT  2999.2 176.99 3000 177.29 ;
    END
  END ra_read_cos_forwarded_result_out[130]
  PIN ra_read_cos_forwarded_result_out[131]
    DIRECTION OUTPUT ;
    USE SIGNAL ;
    PORT
      LAYER met3 ;
        RECT  2999.2 327.95 3000 328.25 ;
    END
  END ra_read_cos_forwarded_result_out[131]
  PIN ra_read_cos_forwarded_result_out[132]
    DIRECTION OUTPUT ;
    USE SIGNAL ;
    PORT
      LAYER met3 ;
        RECT  2999.2 945.39 3000 945.69 ;
    END
  END ra_read_cos_forwarded_result_out[132]
  PIN ra_read_cos_forwarded_result_out[133]
    DIRECTION OUTPUT ;
    USE SIGNAL ;
    PORT
      LAYER met3 ;
        RECT  2999.2 166.11 3000 166.41 ;
    END
  END ra_read_cos_forwarded_result_out[133]
  PIN ra_read_cos_forwarded_result_out[134]
    DIRECTION OUTPUT ;
    USE SIGNAL ;
    PORT
      LAYER met3 ;
        RECT  2999.2 1391.47 3000 1391.77 ;
    END
  END ra_read_cos_forwarded_result_out[134]
  PIN ra_read_cos_forwarded_result_out[135]
    DIRECTION OUTPUT ;
    USE SIGNAL ;
    PORT
      LAYER met3 ;
        RECT  2999.2 506.11 3000 506.41 ;
    END
  END ra_read_cos_forwarded_result_out[135]
  PIN ra_read_cos_forwarded_result_out[136]
    DIRECTION OUTPUT ;
    USE SIGNAL ;
    PORT
      LAYER met3 ;
        RECT  2999.2 419.07 3000 419.37 ;
    END
  END ra_read_cos_forwarded_result_out[136]
  PIN ra_read_cos_forwarded_result_out[137]
    DIRECTION OUTPUT ;
    USE SIGNAL ;
    PORT
      LAYER met3 ;
        RECT  2999.2 1025.63 3000 1025.93 ;
    END
  END ra_read_cos_forwarded_result_out[137]
  PIN ra_read_cos_forwarded_result_out[138]
    DIRECTION OUTPUT ;
    USE SIGNAL ;
    PORT
      LAYER met3 ;
        RECT  2999.2 1300.35 3000 1300.65 ;
    END
  END ra_read_cos_forwarded_result_out[138]
  PIN ra_read_cos_forwarded_result_out[139]
    DIRECTION OUTPUT ;
    USE SIGNAL ;
    PORT
      LAYER met3 ;
        RECT  2999.2 576.83 3000 577.13 ;
    END
  END ra_read_cos_forwarded_result_out[139]
  PIN ra_read_cos_forwarded_result_out[13]
    DIRECTION OUTPUT ;
    USE SIGNAL ;
    PORT
      LAYER met3 ;
        RECT  2999.2 1263.63 3000 1263.93 ;
    END
  END ra_read_cos_forwarded_result_out[13]
  PIN ra_read_cos_forwarded_result_out[140]
    DIRECTION OUTPUT ;
    USE SIGNAL ;
    PORT
      LAYER met3 ;
        RECT  2999.2 405.47 3000 405.77 ;
    END
  END ra_read_cos_forwarded_result_out[140]
  PIN ra_read_cos_forwarded_result_out[141]
    DIRECTION OUTPUT ;
    USE SIGNAL ;
    PORT
      LAYER met3 ;
        RECT  2999.2 1313.95 3000 1314.25 ;
    END
  END ra_read_cos_forwarded_result_out[141]
  PIN ra_read_cos_forwarded_result_out[142]
    DIRECTION OUTPUT ;
    USE SIGNAL ;
    PORT
      LAYER met3 ;
        RECT  2999.2 1473.07 3000 1473.37 ;
    END
  END ra_read_cos_forwarded_result_out[142]
  PIN ra_read_cos_forwarded_result_out[143]
    DIRECTION OUTPUT ;
    USE SIGNAL ;
    PORT
      LAYER met3 ;
        RECT  2999.2 908.67 3000 908.97 ;
    END
  END ra_read_cos_forwarded_result_out[143]
  PIN ra_read_cos_forwarded_result_out[144]
    DIRECTION OUTPUT ;
    USE SIGNAL ;
    PORT
      LAYER met3 ;
        RECT  2999.2 1343.87 3000 1344.17 ;
    END
  END ra_read_cos_forwarded_result_out[144]
  PIN ra_read_cos_forwarded_result_out[145]
    DIRECTION OUTPUT ;
    USE SIGNAL ;
    PORT
      LAYER met3 ;
        RECT  2999.2 847.47 3000 847.77 ;
    END
  END ra_read_cos_forwarded_result_out[145]
  PIN ra_read_cos_forwarded_result_out[146]
    DIRECTION OUTPUT ;
    USE SIGNAL ;
    PORT
      LAYER met3 ;
        RECT  2999.2 1471.71 3000 1472.01 ;
    END
  END ra_read_cos_forwarded_result_out[146]
  PIN ra_read_cos_forwarded_result_out[147]
    DIRECTION OUTPUT ;
    USE SIGNAL ;
    PORT
      LAYER met3 ;
        RECT  2999.2 1245.95 3000 1246.25 ;
    END
  END ra_read_cos_forwarded_result_out[147]
  PIN ra_read_cos_forwarded_result_out[148]
    DIRECTION OUTPUT ;
    USE SIGNAL ;
    PORT
      LAYER met3 ;
        RECT  2999.2 1167.07 3000 1167.37 ;
    END
  END ra_read_cos_forwarded_result_out[148]
  PIN ra_read_cos_forwarded_result_out[149]
    DIRECTION OUTPUT ;
    USE SIGNAL ;
    PORT
      LAYER met3 ;
        RECT  2999.2 1006.59 3000 1006.89 ;
    END
  END ra_read_cos_forwarded_result_out[149]
  PIN ra_read_cos_forwarded_result_out[14]
    DIRECTION OUTPUT ;
    USE SIGNAL ;
    PORT
      LAYER met3 ;
        RECT  2999.2 593.15 3000 593.45 ;
    END
  END ra_read_cos_forwarded_result_out[14]
  PIN ra_read_cos_forwarded_result_out[150]
    DIRECTION OUTPUT ;
    USE SIGNAL ;
    PORT
      LAYER met3 ;
        RECT  2999.2 1217.39 3000 1217.69 ;
    END
  END ra_read_cos_forwarded_result_out[150]
  PIN ra_read_cos_forwarded_result_out[151]
    DIRECTION OUTPUT ;
    USE SIGNAL ;
    PORT
      LAYER met3 ;
        RECT  2999.2 1447.23 3000 1447.53 ;
    END
  END ra_read_cos_forwarded_result_out[151]
  PIN ra_read_cos_forwarded_result_out[152]
    DIRECTION OUTPUT ;
    USE SIGNAL ;
    PORT
      LAYER met3 ;
        RECT  2999.2 349.71 3000 350.01 ;
    END
  END ra_read_cos_forwarded_result_out[152]
  PIN ra_read_cos_forwarded_result_out[153]
    DIRECTION OUTPUT ;
    USE SIGNAL ;
    PORT
      LAYER met3 ;
        RECT  2999.2 264.03 3000 264.33 ;
    END
  END ra_read_cos_forwarded_result_out[153]
  PIN ra_read_cos_forwarded_result_out[154]
    DIRECTION OUTPUT ;
    USE SIGNAL ;
    PORT
      LAYER met3 ;
        RECT  2999.2 247.71 3000 248.01 ;
    END
  END ra_read_cos_forwarded_result_out[154]
  PIN ra_read_cos_forwarded_result_out[155]
    DIRECTION OUTPUT ;
    USE SIGNAL ;
    PORT
      LAYER met3 ;
        RECT  2999.2 1111.31 3000 1111.61 ;
    END
  END ra_read_cos_forwarded_result_out[155]
  PIN ra_read_cos_forwarded_result_out[156]
    DIRECTION OUTPUT ;
    USE SIGNAL ;
    PORT
      LAYER met3 ;
        RECT  2999.2 1179.31 3000 1179.61 ;
    END
  END ra_read_cos_forwarded_result_out[156]
  PIN ra_read_cos_forwarded_result_out[157]
    DIRECTION OUTPUT ;
    USE SIGNAL ;
    PORT
      LAYER met3 ;
        RECT  2999.2 748.19 3000 748.49 ;
    END
  END ra_read_cos_forwarded_result_out[157]
  PIN ra_read_cos_forwarded_result_out[158]
    DIRECTION OUTPUT ;
    USE SIGNAL ;
    PORT
      LAYER met3 ;
        RECT  2999.2 1043.31 3000 1043.61 ;
    END
  END ra_read_cos_forwarded_result_out[158]
  PIN ra_read_cos_forwarded_result_out[159]
    DIRECTION OUTPUT ;
    USE SIGNAL ;
    PORT
      LAYER met3 ;
        RECT  2999.2 1352.03 3000 1352.33 ;
    END
  END ra_read_cos_forwarded_result_out[159]
  PIN ra_read_cos_forwarded_result_out[15]
    DIRECTION OUTPUT ;
    USE SIGNAL ;
    PORT
      LAYER met3 ;
        RECT  2999.2 1330.27 3000 1330.57 ;
    END
  END ra_read_cos_forwarded_result_out[15]
  PIN ra_read_cos_forwarded_result_out[160]
    DIRECTION OUTPUT ;
    USE SIGNAL ;
    PORT
      LAYER met3 ;
        RECT  2999.2 791.71 3000 792.01 ;
    END
  END ra_read_cos_forwarded_result_out[160]
  PIN ra_read_cos_forwarded_result_out[161]
    DIRECTION OUTPUT ;
    USE SIGNAL ;
    PORT
      LAYER met3 ;
        RECT  2999.2 492.51 3000 492.81 ;
    END
  END ra_read_cos_forwarded_result_out[161]
  PIN ra_read_cos_forwarded_result_out[162]
    DIRECTION OUTPUT ;
    USE SIGNAL ;
    PORT
      LAYER met3 ;
        RECT  2999.2 978.03 3000 978.33 ;
    END
  END ra_read_cos_forwarded_result_out[162]
  PIN ra_read_cos_forwarded_result_out[163]
    DIRECTION OUTPUT ;
    USE SIGNAL ;
    PORT
      LAYER met3 ;
        RECT  2999.2 171.55 3000 171.85 ;
    END
  END ra_read_cos_forwarded_result_out[163]
  PIN ra_read_cos_forwarded_result_out[164]
    DIRECTION OUTPUT ;
    USE SIGNAL ;
    PORT
      LAYER met3 ;
        RECT  2999.2 1067.79 3000 1068.09 ;
    END
  END ra_read_cos_forwarded_result_out[164]
  PIN ra_read_cos_forwarded_result_out[165]
    DIRECTION OUTPUT ;
    USE SIGNAL ;
    PORT
      LAYER met3 ;
        RECT  2999.2 1338.43 3000 1338.73 ;
    END
  END ra_read_cos_forwarded_result_out[165]
  PIN ra_read_cos_forwarded_result_out[166]
    DIRECTION OUTPUT ;
    USE SIGNAL ;
    PORT
      LAYER met3 ;
        RECT  2999.2 1063.71 3000 1064.01 ;
    END
  END ra_read_cos_forwarded_result_out[166]
  PIN ra_read_cos_forwarded_result_out[167]
    DIRECTION OUTPUT ;
    USE SIGNAL ;
    PORT
      LAYER met3 ;
        RECT  2999.2 1210.59 3000 1210.89 ;
    END
  END ra_read_cos_forwarded_result_out[167]
  PIN ra_read_cos_forwarded_result_out[168]
    DIRECTION OUTPUT ;
    USE SIGNAL ;
    PORT
      LAYER met3 ;
        RECT  2999.2 175.63 3000 175.93 ;
    END
  END ra_read_cos_forwarded_result_out[168]
  PIN ra_read_cos_forwarded_result_out[169]
    DIRECTION OUTPUT ;
    USE SIGNAL ;
    PORT
      LAYER met3 ;
        RECT  2999.2 1379.23 3000 1379.53 ;
    END
  END ra_read_cos_forwarded_result_out[169]
  PIN ra_read_cos_forwarded_result_out[16]
    DIRECTION OUTPUT ;
    USE SIGNAL ;
    PORT
      LAYER met3 ;
        RECT  2999.2 648.91 3000 649.21 ;
    END
  END ra_read_cos_forwarded_result_out[16]
  PIN ra_read_cos_forwarded_result_out[170]
    DIRECTION OUTPUT ;
    USE SIGNAL ;
    PORT
      LAYER met3 ;
        RECT  2999.2 420.43 3000 420.73 ;
    END
  END ra_read_cos_forwarded_result_out[170]
  PIN ra_read_cos_forwarded_result_out[171]
    DIRECTION OUTPUT ;
    USE SIGNAL ;
    PORT
      LAYER met3 ;
        RECT  2999.2 306.19 3000 306.49 ;
    END
  END ra_read_cos_forwarded_result_out[171]
  PIN ra_read_cos_forwarded_result_out[172]
    DIRECTION OUTPUT ;
    USE SIGNAL ;
    PORT
      LAYER met3 ;
        RECT  2999.2 253.15 3000 253.45 ;
    END
  END ra_read_cos_forwarded_result_out[172]
  PIN ra_read_cos_forwarded_result_out[173]
    DIRECTION OUTPUT ;
    USE SIGNAL ;
    PORT
      LAYER met3 ;
        RECT  2999.2 1014.75 3000 1015.05 ;
    END
  END ra_read_cos_forwarded_result_out[173]
  PIN ra_read_cos_forwarded_result_out[174]
    DIRECTION OUTPUT ;
    USE SIGNAL ;
    PORT
      LAYER met3 ;
        RECT  2999.2 480.27 3000 480.57 ;
    END
  END ra_read_cos_forwarded_result_out[174]
  PIN ra_read_cos_forwarded_result_out[175]
    DIRECTION OUTPUT ;
    USE SIGNAL ;
    PORT
      LAYER met3 ;
        RECT  2999.2 1390.11 3000 1390.41 ;
    END
  END ra_read_cos_forwarded_result_out[175]
  PIN ra_read_cos_forwarded_result_out[176]
    DIRECTION OUTPUT ;
    USE SIGNAL ;
    PORT
      LAYER met3 ;
        RECT  2999.2 1081.39 3000 1081.69 ;
    END
  END ra_read_cos_forwarded_result_out[176]
  PIN ra_read_cos_forwarded_result_out[177]
    DIRECTION OUTPUT ;
    USE SIGNAL ;
    PORT
      LAYER met3 ;
        RECT  2999.2 1298.99 3000 1299.29 ;
    END
  END ra_read_cos_forwarded_result_out[177]
  PIN ra_read_cos_forwarded_result_out[178]
    DIRECTION OUTPUT ;
    USE SIGNAL ;
    PORT
      LAYER met3 ;
        RECT  2999.2 1139.87 3000 1140.17 ;
    END
  END ra_read_cos_forwarded_result_out[178]
  PIN ra_read_cos_forwarded_result_out[179]
    DIRECTION OUTPUT ;
    USE SIGNAL ;
    PORT
      LAYER met3 ;
        RECT  2999.2 590.43 3000 590.73 ;
    END
  END ra_read_cos_forwarded_result_out[179]
  PIN ra_read_cos_forwarded_result_out[17]
    DIRECTION OUTPUT ;
    USE SIGNAL ;
    PORT
      LAYER met3 ;
        RECT  2999.2 711.47 3000 711.77 ;
    END
  END ra_read_cos_forwarded_result_out[17]
  PIN ra_read_cos_forwarded_result_out[180]
    DIRECTION OUTPUT ;
    USE SIGNAL ;
    PORT
      LAYER met3 ;
        RECT  2999.2 905.95 3000 906.25 ;
    END
  END ra_read_cos_forwarded_result_out[180]
  PIN ra_read_cos_forwarded_result_out[181]
    DIRECTION OUTPUT ;
    USE SIGNAL ;
    PORT
      LAYER met3 ;
        RECT  2999.2 474.83 3000 475.13 ;
    END
  END ra_read_cos_forwarded_result_out[181]
  PIN ra_read_cos_forwarded_result_out[182]
    DIRECTION OUTPUT ;
    USE SIGNAL ;
    PORT
      LAYER met3 ;
        RECT  2999.2 772.67 3000 772.97 ;
    END
  END ra_read_cos_forwarded_result_out[182]
  PIN ra_read_cos_forwarded_result_out[183]
    DIRECTION OUTPUT ;
    USE SIGNAL ;
    PORT
      LAYER met3 ;
        RECT  2999.2 635.31 3000 635.61 ;
    END
  END ra_read_cos_forwarded_result_out[183]
  PIN ra_read_cos_forwarded_result_out[184]
    DIRECTION OUTPUT ;
    USE SIGNAL ;
    PORT
      LAYER met3 ;
        RECT  2999.2 760.43 3000 760.73 ;
    END
  END ra_read_cos_forwarded_result_out[184]
  PIN ra_read_cos_forwarded_result_out[185]
    DIRECTION OUTPUT ;
    USE SIGNAL ;
    PORT
      LAYER met3 ;
        RECT  2999.2 262.67 3000 262.97 ;
    END
  END ra_read_cos_forwarded_result_out[185]
  PIN ra_read_cos_forwarded_result_out[186]
    DIRECTION OUTPUT ;
    USE SIGNAL ;
    PORT
      LAYER met3 ;
        RECT  2999.2 1369.71 3000 1370.01 ;
    END
  END ra_read_cos_forwarded_result_out[186]
  PIN ra_read_cos_forwarded_result_out[187]
    DIRECTION OUTPUT ;
    USE SIGNAL ;
    PORT
      LAYER met3 ;
        RECT  2999.2 438.11 3000 438.41 ;
    END
  END ra_read_cos_forwarded_result_out[187]
  PIN ra_read_cos_forwarded_result_out[188]
    DIRECTION OUTPUT ;
    USE SIGNAL ;
    PORT
      LAYER met3 ;
        RECT  2999.2 825.71 3000 826.01 ;
    END
  END ra_read_cos_forwarded_result_out[188]
  PIN ra_read_cos_forwarded_result_out[189]
    DIRECTION OUTPUT ;
    USE SIGNAL ;
    PORT
      LAYER met3 ;
        RECT  2999.2 655.71 3000 656.01 ;
    END
  END ra_read_cos_forwarded_result_out[189]
  PIN ra_read_cos_forwarded_result_out[18]
    DIRECTION OUTPUT ;
    USE SIGNAL ;
    PORT
      LAYER met3 ;
        RECT  2999.2 1150.75 3000 1151.05 ;
    END
  END ra_read_cos_forwarded_result_out[18]
  PIN ra_read_cos_forwarded_result_out[190]
    DIRECTION OUTPUT ;
    USE SIGNAL ;
    PORT
      LAYER met3 ;
        RECT  2999.2 1384.67 3000 1384.97 ;
    END
  END ra_read_cos_forwarded_result_out[190]
  PIN ra_read_cos_forwarded_result_out[191]
    DIRECTION OUTPUT ;
    USE SIGNAL ;
    PORT
      LAYER met3 ;
        RECT  2999.2 599.95 3000 600.25 ;
    END
  END ra_read_cos_forwarded_result_out[191]
  PIN ra_read_cos_forwarded_result_out[192]
    DIRECTION OUTPUT ;
    USE SIGNAL ;
    PORT
      LAYER met3 ;
        RECT  2999.2 559.15 3000 559.45 ;
    END
  END ra_read_cos_forwarded_result_out[192]
  PIN ra_read_cos_forwarded_result_out[193]
    DIRECTION OUTPUT ;
    USE SIGNAL ;
    PORT
      LAYER met3 ;
        RECT  2999.2 1462.19 3000 1462.49 ;
    END
  END ra_read_cos_forwarded_result_out[193]
  PIN ra_read_cos_forwarded_result_out[194]
    DIRECTION OUTPUT ;
    USE SIGNAL ;
    PORT
      LAYER met3 ;
        RECT  2999.2 1017.47 3000 1017.77 ;
    END
  END ra_read_cos_forwarded_result_out[194]
  PIN ra_read_cos_forwarded_result_out[195]
    DIRECTION OUTPUT ;
    USE SIGNAL ;
    PORT
      LAYER met3 ;
        RECT  2999.2 1380.59 3000 1380.89 ;
    END
  END ra_read_cos_forwarded_result_out[195]
  PIN ra_read_cos_forwarded_result_out[196]
    DIRECTION OUTPUT ;
    USE SIGNAL ;
    PORT
      LAYER met3 ;
        RECT  2999.2 152.51 3000 152.81 ;
    END
  END ra_read_cos_forwarded_result_out[196]
  PIN ra_read_cos_forwarded_result_out[197]
    DIRECTION OUTPUT ;
    USE SIGNAL ;
    PORT
      LAYER met3 ;
        RECT  2999.2 1470.35 3000 1470.65 ;
    END
  END ra_read_cos_forwarded_result_out[197]
  PIN ra_read_cos_forwarded_result_out[198]
    DIRECTION OUTPUT ;
    USE SIGNAL ;
    PORT
      LAYER met3 ;
        RECT  2999.2 1062.35 3000 1062.65 ;
    END
  END ra_read_cos_forwarded_result_out[198]
  PIN ra_read_cos_forwarded_result_out[199]
    DIRECTION OUTPUT ;
    USE SIGNAL ;
    PORT
      LAYER met3 ;
        RECT  2999.2 344.27 3000 344.57 ;
    END
  END ra_read_cos_forwarded_result_out[199]
  PIN ra_read_cos_forwarded_result_out[19]
    DIRECTION OUTPUT ;
    USE SIGNAL ;
    PORT
      LAYER met3 ;
        RECT  2999.2 666.59 3000 666.89 ;
    END
  END ra_read_cos_forwarded_result_out[19]
  PIN ra_read_cos_forwarded_result_out[1]
    DIRECTION OUTPUT ;
    USE SIGNAL ;
    PORT
      LAYER met3 ;
        RECT  2999.2 1243.23 3000 1243.53 ;
    END
  END ra_read_cos_forwarded_result_out[1]
  PIN ra_read_cos_forwarded_result_out[200]
    DIRECTION OUTPUT ;
    USE SIGNAL ;
    PORT
      LAYER met3 ;
        RECT  2999.2 833.87 3000 834.17 ;
    END
  END ra_read_cos_forwarded_result_out[200]
  PIN ra_read_cos_forwarded_result_out[201]
    DIRECTION OUTPUT ;
    USE SIGNAL ;
    PORT
      LAYER met3 ;
        RECT  2999.2 767.23 3000 767.53 ;
    END
  END ra_read_cos_forwarded_result_out[201]
  PIN ra_read_cos_forwarded_result_out[202]
    DIRECTION OUTPUT ;
    USE SIGNAL ;
    PORT
      LAYER met3 ;
        RECT  2999.2 1118.11 3000 1118.41 ;
    END
  END ra_read_cos_forwarded_result_out[202]
  PIN ra_read_cos_forwarded_result_out[203]
    DIRECTION OUTPUT ;
    USE SIGNAL ;
    PORT
      LAYER met3 ;
        RECT  2999.2 332.03 3000 332.33 ;
    END
  END ra_read_cos_forwarded_result_out[203]
  PIN ra_read_cos_forwarded_result_out[204]
    DIRECTION OUTPUT ;
    USE SIGNAL ;
    PORT
      LAYER met3 ;
        RECT  2999.2 167.47 3000 167.77 ;
    END
  END ra_read_cos_forwarded_result_out[204]
  PIN ra_read_cos_forwarded_result_out[205]
    DIRECTION OUTPUT ;
    USE SIGNAL ;
    PORT
      LAYER met3 ;
        RECT  2999.2 484.35 3000 484.65 ;
    END
  END ra_read_cos_forwarded_result_out[205]
  PIN ra_read_cos_forwarded_result_out[206]
    DIRECTION OUTPUT ;
    USE SIGNAL ;
    PORT
      LAYER met3 ;
        RECT  2999.2 570.03 3000 570.33 ;
    END
  END ra_read_cos_forwarded_result_out[206]
  PIN ra_read_cos_forwarded_result_out[207]
    DIRECTION OUTPUT ;
    USE SIGNAL ;
    PORT
      LAYER met3 ;
        RECT  2999.2 608.11 3000 608.41 ;
    END
  END ra_read_cos_forwarded_result_out[207]
  PIN ra_read_cos_forwarded_result_out[208]
    DIRECTION OUTPUT ;
    USE SIGNAL ;
    PORT
      LAYER met3 ;
        RECT  2999.2 822.99 3000 823.29 ;
    END
  END ra_read_cos_forwarded_result_out[208]
  PIN ra_read_cos_forwarded_result_out[209]
    DIRECTION OUTPUT ;
    USE SIGNAL ;
    PORT
      LAYER met3 ;
        RECT  2999.2 446.27 3000 446.57 ;
    END
  END ra_read_cos_forwarded_result_out[209]
  PIN ra_read_cos_forwarded_result_out[20]
    DIRECTION OUTPUT ;
    USE SIGNAL ;
    PORT
      LAYER met3 ;
        RECT  2999.2 672.03 3000 672.33 ;
    END
  END ra_read_cos_forwarded_result_out[20]
  PIN ra_read_cos_forwarded_result_out[210]
    DIRECTION OUTPUT ;
    USE SIGNAL ;
    PORT
      LAYER met3 ;
        RECT  2999.2 1055.55 3000 1055.85 ;
    END
  END ra_read_cos_forwarded_result_out[210]
  PIN ra_read_cos_forwarded_result_out[211]
    DIRECTION OUTPUT ;
    USE SIGNAL ;
    PORT
      LAYER met3 ;
        RECT  2999.2 829.79 3000 830.09 ;
    END
  END ra_read_cos_forwarded_result_out[211]
  PIN ra_read_cos_forwarded_result_out[212]
    DIRECTION OUTPUT ;
    USE SIGNAL ;
    PORT
      LAYER met3 ;
        RECT  2999.2 636.67 3000 636.97 ;
    END
  END ra_read_cos_forwarded_result_out[212]
  PIN ra_read_cos_forwarded_result_out[213]
    DIRECTION OUTPUT ;
    USE SIGNAL ;
    PORT
      LAYER met3 ;
        RECT  2999.2 591.79 3000 592.09 ;
    END
  END ra_read_cos_forwarded_result_out[213]
  PIN ra_read_cos_forwarded_result_out[214]
    DIRECTION OUTPUT ;
    USE SIGNAL ;
    PORT
      LAYER met3 ;
        RECT  2999.2 716.91 3000 717.21 ;
    END
  END ra_read_cos_forwarded_result_out[214]
  PIN ra_read_cos_forwarded_result_out[215]
    DIRECTION OUTPUT ;
    USE SIGNAL ;
    PORT
      LAYER met3 ;
        RECT  2999.2 882.83 3000 883.13 ;
    END
  END ra_read_cos_forwarded_result_out[215]
  PIN ra_read_cos_forwarded_result_out[216]
    DIRECTION OUTPUT ;
    USE SIGNAL ;
    PORT
      LAYER met3 ;
        RECT  2999.2 937.23 3000 937.53 ;
    END
  END ra_read_cos_forwarded_result_out[216]
  PIN ra_read_cos_forwarded_result_out[217]
    DIRECTION OUTPUT ;
    USE SIGNAL ;
    PORT
      LAYER met3 ;
        RECT  2999.2 863.79 3000 864.09 ;
    END
  END ra_read_cos_forwarded_result_out[217]
  PIN ra_read_cos_forwarded_result_out[218]
    DIRECTION OUTPUT ;
    USE SIGNAL ;
    PORT
      LAYER met3 ;
        RECT  2999.2 504.75 3000 505.05 ;
    END
  END ra_read_cos_forwarded_result_out[218]
  PIN ra_read_cos_forwarded_result_out[219]
    DIRECTION OUTPUT ;
    USE SIGNAL ;
    PORT
      LAYER met3 ;
        RECT  2999.2 160.67 3000 160.97 ;
    END
  END ra_read_cos_forwarded_result_out[219]
  PIN ra_read_cos_forwarded_result_out[21]
    DIRECTION OUTPUT ;
    USE SIGNAL ;
    PORT
      LAYER met3 ;
        RECT  2999.2 564.59 3000 564.89 ;
    END
  END ra_read_cos_forwarded_result_out[21]
  PIN ra_read_cos_forwarded_result_out[220]
    DIRECTION OUTPUT ;
    USE SIGNAL ;
    PORT
      LAYER met3 ;
        RECT  2999.2 842.03 3000 842.33 ;
    END
  END ra_read_cos_forwarded_result_out[220]
  PIN ra_read_cos_forwarded_result_out[221]
    DIRECTION OUTPUT ;
    USE SIGNAL ;
    PORT
      LAYER met3 ;
        RECT  2999.2 307.55 3000 307.85 ;
    END
  END ra_read_cos_forwarded_result_out[221]
  PIN ra_read_cos_forwarded_result_out[222]
    DIRECTION OUTPUT ;
    USE SIGNAL ;
    PORT
      LAYER met3 ;
        RECT  2999.2 239.55 3000 239.85 ;
    END
  END ra_read_cos_forwarded_result_out[222]
  PIN ra_read_cos_forwarded_result_out[223]
    DIRECTION OUTPUT ;
    USE SIGNAL ;
    PORT
      LAYER met3 ;
        RECT  2999.2 586.35 3000 586.65 ;
    END
  END ra_read_cos_forwarded_result_out[223]
  PIN ra_read_cos_forwarded_result_out[224]
    DIRECTION OUTPUT ;
    USE SIGNAL ;
    PORT
      LAYER met3 ;
        RECT  2999.2 794.43 3000 794.73 ;
    END
  END ra_read_cos_forwarded_result_out[224]
  PIN ra_read_cos_forwarded_result_out[225]
    DIRECTION OUTPUT ;
    USE SIGNAL ;
    PORT
      LAYER met3 ;
        RECT  2999.2 1183.39 3000 1183.69 ;
    END
  END ra_read_cos_forwarded_result_out[225]
  PIN ra_read_cos_forwarded_result_out[226]
    DIRECTION OUTPUT ;
    USE SIGNAL ;
    PORT
      LAYER met3 ;
        RECT  2999.2 984.83 3000 985.13 ;
    END
  END ra_read_cos_forwarded_result_out[226]
  PIN ra_read_cos_forwarded_result_out[227]
    DIRECTION OUTPUT ;
    USE SIGNAL ;
    PORT
      LAYER met3 ;
        RECT  2999.2 1387.39 3000 1387.69 ;
    END
  END ra_read_cos_forwarded_result_out[227]
  PIN ra_read_cos_forwarded_result_out[228]
    DIRECTION OUTPUT ;
    USE SIGNAL ;
    PORT
      LAYER met3 ;
        RECT  2999.2 164.75 3000 165.05 ;
    END
  END ra_read_cos_forwarded_result_out[228]
  PIN ra_read_cos_forwarded_result_out[229]
    DIRECTION OUTPUT ;
    USE SIGNAL ;
    PORT
      LAYER met3 ;
        RECT  2999.2 382.35 3000 382.65 ;
    END
  END ra_read_cos_forwarded_result_out[229]
  PIN ra_read_cos_forwarded_result_out[22]
    DIRECTION OUTPUT ;
    USE SIGNAL ;
    PORT
      LAYER met3 ;
        RECT  2999.2 1307.15 3000 1307.45 ;
    END
  END ra_read_cos_forwarded_result_out[22]
  PIN ra_read_cos_forwarded_result_out[230]
    DIRECTION OUTPUT ;
    USE SIGNAL ;
    PORT
      LAYER met3 ;
        RECT  2999.2 1409.15 3000 1409.45 ;
    END
  END ra_read_cos_forwarded_result_out[230]
  PIN ra_read_cos_forwarded_result_out[231]
    DIRECTION OUTPUT ;
    USE SIGNAL ;
    PORT
      LAYER met3 ;
        RECT  2999.2 287.15 3000 287.45 ;
    END
  END ra_read_cos_forwarded_result_out[231]
  PIN ra_read_cos_forwarded_result_out[232]
    DIRECTION OUTPUT ;
    USE SIGNAL ;
    PORT
      LAYER met3 ;
        RECT  2999.2 156.59 3000 156.89 ;
    END
  END ra_read_cos_forwarded_result_out[232]
  PIN ra_read_cos_forwarded_result_out[233]
    DIRECTION OUTPUT ;
    USE SIGNAL ;
    PORT
      LAYER met3 ;
        RECT  2999.2 813.47 3000 813.77 ;
    END
  END ra_read_cos_forwarded_result_out[233]
  PIN ra_read_cos_forwarded_result_out[234]
    DIRECTION OUTPUT ;
    USE SIGNAL ;
    PORT
      LAYER met3 ;
        RECT  2999.2 168.83 3000 169.13 ;
    END
  END ra_read_cos_forwarded_result_out[234]
  PIN ra_read_cos_forwarded_result_out[235]
    DIRECTION OUTPUT ;
    USE SIGNAL ;
    PORT
      LAYER met3 ;
        RECT  2999.2 326.59 3000 326.89 ;
    END
  END ra_read_cos_forwarded_result_out[235]
  PIN ra_read_cos_forwarded_result_out[236]
    DIRECTION OUTPUT ;
    USE SIGNAL ;
    PORT
      LAYER met3 ;
        RECT  2999.2 771.31 3000 771.61 ;
    END
  END ra_read_cos_forwarded_result_out[236]
  PIN ra_read_cos_forwarded_result_out[237]
    DIRECTION OUTPUT ;
    USE SIGNAL ;
    PORT
      LAYER met3 ;
        RECT  2999.2 703.31 3000 703.61 ;
    END
  END ra_read_cos_forwarded_result_out[237]
  PIN ra_read_cos_forwarded_result_out[238]
    DIRECTION OUTPUT ;
    USE SIGNAL ;
    PORT
      LAYER met3 ;
        RECT  2999.2 1305.79 3000 1306.09 ;
    END
  END ra_read_cos_forwarded_result_out[238]
  PIN ra_read_cos_forwarded_result_out[239]
    DIRECTION OUTPUT ;
    USE SIGNAL ;
    PORT
      LAYER met3 ;
        RECT  2999.2 935.87 3000 936.17 ;
    END
  END ra_read_cos_forwarded_result_out[239]
  PIN ra_read_cos_forwarded_result_out[23]
    DIRECTION OUTPUT ;
    USE SIGNAL ;
    PORT
      LAYER met3 ;
        RECT  2999.2 1474.43 3000 1474.73 ;
    END
  END ra_read_cos_forwarded_result_out[23]
  PIN ra_read_cos_forwarded_result_out[240]
    DIRECTION OUTPUT ;
    USE SIGNAL ;
    PORT
      LAYER met3 ;
        RECT  2999.2 345.63 3000 345.93 ;
    END
  END ra_read_cos_forwarded_result_out[240]
  PIN ra_read_cos_forwarded_result_out[241]
    DIRECTION OUTPUT ;
    USE SIGNAL ;
    PORT
      LAYER met3 ;
        RECT  2999.2 557.79 3000 558.09 ;
    END
  END ra_read_cos_forwarded_result_out[241]
  PIN ra_read_cos_forwarded_result_out[242]
    DIRECTION OUTPUT ;
    USE SIGNAL ;
    PORT
      LAYER met3 ;
        RECT  2999.2 1478.51 3000 1478.81 ;
    END
  END ra_read_cos_forwarded_result_out[242]
  PIN ra_read_cos_forwarded_result_out[243]
    DIRECTION OUTPUT ;
    USE SIGNAL ;
    PORT
      LAYER met3 ;
        RECT  2999.2 1050.11 3000 1050.41 ;
    END
  END ra_read_cos_forwarded_result_out[243]
  PIN ra_read_cos_forwarded_result_out[244]
    DIRECTION OUTPUT ;
    USE SIGNAL ;
    PORT
      LAYER met3 ;
        RECT  2999.2 584.99 3000 585.29 ;
    END
  END ra_read_cos_forwarded_result_out[244]
  PIN ra_read_cos_forwarded_result_out[245]
    DIRECTION OUTPUT ;
    USE SIGNAL ;
    PORT
      LAYER met3 ;
        RECT  2999.2 727.79 3000 728.09 ;
    END
  END ra_read_cos_forwarded_result_out[245]
  PIN ra_read_cos_forwarded_result_out[246]
    DIRECTION OUTPUT ;
    USE SIGNAL ;
    PORT
      LAYER met3 ;
        RECT  2999.2 761.79 3000 762.09 ;
    END
  END ra_read_cos_forwarded_result_out[246]
  PIN ra_read_cos_forwarded_result_out[247]
    DIRECTION OUTPUT ;
    USE SIGNAL ;
    PORT
      LAYER met3 ;
        RECT  2999.2 1233.71 3000 1234.01 ;
    END
  END ra_read_cos_forwarded_result_out[247]
  PIN ra_read_cos_forwarded_result_out[248]
    DIRECTION OUTPUT ;
    USE SIGNAL ;
    PORT
      LAYER met3 ;
        RECT  2999.2 157.95 3000 158.25 ;
    END
  END ra_read_cos_forwarded_result_out[248]
  PIN ra_read_cos_forwarded_result_out[249]
    DIRECTION OUTPUT ;
    USE SIGNAL ;
    PORT
      LAYER met3 ;
        RECT  2999.2 196.03 3000 196.33 ;
    END
  END ra_read_cos_forwarded_result_out[249]
  PIN ra_read_cos_forwarded_result_out[24]
    DIRECTION OUTPUT ;
    USE SIGNAL ;
    PORT
      LAYER met3 ;
        RECT  2999.2 329.31 3000 329.61 ;
    END
  END ra_read_cos_forwarded_result_out[24]
  PIN ra_read_cos_forwarded_result_out[250]
    DIRECTION OUTPUT ;
    USE SIGNAL ;
    PORT
      LAYER met3 ;
        RECT  2999.2 1184.75 3000 1185.05 ;
    END
  END ra_read_cos_forwarded_result_out[250]
  PIN ra_read_cos_forwarded_result_out[251]
    DIRECTION OUTPUT ;
    USE SIGNAL ;
    PORT
      LAYER met3 ;
        RECT  2999.2 670.67 3000 670.97 ;
    END
  END ra_read_cos_forwarded_result_out[251]
  PIN ra_read_cos_forwarded_result_out[252]
    DIRECTION OUTPUT ;
    USE SIGNAL ;
    PORT
      LAYER met3 ;
        RECT  2999.2 1141.23 3000 1141.53 ;
    END
  END ra_read_cos_forwarded_result_out[252]
  PIN ra_read_cos_forwarded_result_out[253]
    DIRECTION OUTPUT ;
    USE SIGNAL ;
    PORT
      LAYER met3 ;
        RECT  2999.2 162.03 3000 162.33 ;
    END
  END ra_read_cos_forwarded_result_out[253]
  PIN ra_read_cos_forwarded_result_out[254]
    DIRECTION OUTPUT ;
    USE SIGNAL ;
    PORT
      LAYER met3 ;
        RECT  2999.2 854.27 3000 854.57 ;
    END
  END ra_read_cos_forwarded_result_out[254]
  PIN ra_read_cos_forwarded_result_out[255]
    DIRECTION OUTPUT ;
    USE SIGNAL ;
    PORT
      LAYER met3 ;
        RECT  2999.2 198.75 3000 199.05 ;
    END
  END ra_read_cos_forwarded_result_out[255]
  PIN ra_read_cos_forwarded_result_out[25]
    DIRECTION OUTPUT ;
    USE SIGNAL ;
    PORT
      LAYER met3 ;
        RECT  2999.2 810.75 3000 811.05 ;
    END
  END ra_read_cos_forwarded_result_out[25]
  PIN ra_read_cos_forwarded_result_out[26]
    DIRECTION OUTPUT ;
    USE SIGNAL ;
    PORT
      LAYER met3 ;
        RECT  2999.2 266.75 3000 267.05 ;
    END
  END ra_read_cos_forwarded_result_out[26]
  PIN ra_read_cos_forwarded_result_out[27]
    DIRECTION OUTPUT ;
    USE SIGNAL ;
    PORT
      LAYER met3 ;
        RECT  2999.2 364.67 3000 364.97 ;
    END
  END ra_read_cos_forwarded_result_out[27]
  PIN ra_read_cos_forwarded_result_out[28]
    DIRECTION OUTPUT ;
    USE SIGNAL ;
    PORT
      LAYER met3 ;
        RECT  2999.2 918.19 3000 918.49 ;
    END
  END ra_read_cos_forwarded_result_out[28]
  PIN ra_read_cos_forwarded_result_out[29]
    DIRECTION OUTPUT ;
    USE SIGNAL ;
    PORT
      LAYER met3 ;
        RECT  2999.2 187.87 3000 188.17 ;
    END
  END ra_read_cos_forwarded_result_out[29]
  PIN ra_read_cos_forwarded_result_out[2]
    DIRECTION OUTPUT ;
    USE SIGNAL ;
    PORT
      LAYER met3 ;
        RECT  2999.2 729.15 3000 729.45 ;
    END
  END ra_read_cos_forwarded_result_out[2]
  PIN ra_read_cos_forwarded_result_out[30]
    DIRECTION OUTPUT ;
    USE SIGNAL ;
    PORT
      LAYER met3 ;
        RECT  2999.2 1222.83 3000 1223.13 ;
    END
  END ra_read_cos_forwarded_result_out[30]
  PIN ra_read_cos_forwarded_result_out[31]
    DIRECTION OUTPUT ;
    USE SIGNAL ;
    PORT
      LAYER met3 ;
        RECT  2999.2 912.75 3000 913.05 ;
    END
  END ra_read_cos_forwarded_result_out[31]
  PIN ra_read_cos_forwarded_result_out[32]
    DIRECTION OUTPUT ;
    USE SIGNAL ;
    PORT
      LAYER met3 ;
        RECT  2999.2 1097.71 3000 1098.01 ;
    END
  END ra_read_cos_forwarded_result_out[32]
  PIN ra_read_cos_forwarded_result_out[33]
    DIRECTION OUTPUT ;
    USE SIGNAL ;
    PORT
      LAYER met3 ;
        RECT  2999.2 658.43 3000 658.73 ;
    END
  END ra_read_cos_forwarded_result_out[33]
  PIN ra_read_cos_forwarded_result_out[34]
    DIRECTION OUTPUT ;
    USE SIGNAL ;
    PORT
      LAYER met3 ;
        RECT  2999.2 963.07 3000 963.37 ;
    END
  END ra_read_cos_forwarded_result_out[34]
  PIN ra_read_cos_forwarded_result_out[35]
    DIRECTION OUTPUT ;
    USE SIGNAL ;
    PORT
      LAYER met3 ;
        RECT  2999.2 1060.99 3000 1061.29 ;
    END
  END ra_read_cos_forwarded_result_out[35]
  PIN ra_read_cos_forwarded_result_out[36]
    DIRECTION OUTPUT ;
    USE SIGNAL ;
    PORT
      LAYER met3 ;
        RECT  2999.2 682.91 3000 683.21 ;
    END
  END ra_read_cos_forwarded_result_out[36]
  PIN ra_read_cos_forwarded_result_out[37]
    DIRECTION OUTPUT ;
    USE SIGNAL ;
    PORT
      LAYER met3 ;
        RECT  2999.2 793.07 3000 793.37 ;
    END
  END ra_read_cos_forwarded_result_out[37]
  PIN ra_read_cos_forwarded_result_out[38]
    DIRECTION OUTPUT ;
    USE SIGNAL ;
    PORT
      LAYER met3 ;
        RECT  2999.2 410.91 3000 411.21 ;
    END
  END ra_read_cos_forwarded_result_out[38]
  PIN ra_read_cos_forwarded_result_out[39]
    DIRECTION OUTPUT ;
    USE SIGNAL ;
    PORT
      LAYER met3 ;
        RECT  2999.2 726.43 3000 726.73 ;
    END
  END ra_read_cos_forwarded_result_out[39]
  PIN ra_read_cos_forwarded_result_out[3]
    DIRECTION OUTPUT ;
    USE SIGNAL ;
    PORT
      LAYER met3 ;
        RECT  2999.2 500.67 3000 500.97 ;
    END
  END ra_read_cos_forwarded_result_out[3]
  PIN ra_read_cos_forwarded_result_out[40]
    DIRECTION OUTPUT ;
    USE SIGNAL ;
    PORT
      LAYER met3 ;
        RECT  2999.2 402.75 3000 403.05 ;
    END
  END ra_read_cos_forwarded_result_out[40]
  PIN ra_read_cos_forwarded_result_out[41]
    DIRECTION OUTPUT ;
    USE SIGNAL ;
    PORT
      LAYER met3 ;
        RECT  2999.2 1463.55 3000 1463.85 ;
    END
  END ra_read_cos_forwarded_result_out[41]
  PIN ra_read_cos_forwarded_result_out[42]
    DIRECTION OUTPUT ;
    USE SIGNAL ;
    PORT
      LAYER met3 ;
        RECT  2999.2 337.47 3000 337.77 ;
    END
  END ra_read_cos_forwarded_result_out[42]
  PIN ra_read_cos_forwarded_result_out[43]
    DIRECTION OUTPUT ;
    USE SIGNAL ;
    PORT
      LAYER met3 ;
        RECT  2999.2 507.47 3000 507.77 ;
    END
  END ra_read_cos_forwarded_result_out[43]
  PIN ra_read_cos_forwarded_result_out[44]
    DIRECTION OUTPUT ;
    USE SIGNAL ;
    PORT
      LAYER met3 ;
        RECT  2999.2 684.27 3000 684.57 ;
    END
  END ra_read_cos_forwarded_result_out[44]
  PIN ra_read_cos_forwarded_result_out[45]
    DIRECTION OUTPUT ;
    USE SIGNAL ;
    PORT
      LAYER met3 ;
        RECT  2999.2 510.19 3000 510.49 ;
    END
  END ra_read_cos_forwarded_result_out[45]
  PIN ra_read_cos_forwarded_result_out[46]
    DIRECTION OUTPUT ;
    USE SIGNAL ;
    PORT
      LAYER met3 ;
        RECT  2999.2 153.87 3000 154.17 ;
    END
  END ra_read_cos_forwarded_result_out[46]
  PIN ra_read_cos_forwarded_result_out[47]
    DIRECTION OUTPUT ;
    USE SIGNAL ;
    PORT
      LAYER met3 ;
        RECT  2999.2 1119.47 3000 1119.77 ;
    END
  END ra_read_cos_forwarded_result_out[47]
  PIN ra_read_cos_forwarded_result_out[48]
    DIRECTION OUTPUT ;
    USE SIGNAL ;
    PORT
      LAYER met3 ;
        RECT  2999.2 311.63 3000 311.93 ;
    END
  END ra_read_cos_forwarded_result_out[48]
  PIN ra_read_cos_forwarded_result_out[49]
    DIRECTION OUTPUT ;
    USE SIGNAL ;
    PORT
      LAYER met3 ;
        RECT  2999.2 417.71 3000 418.01 ;
    END
  END ra_read_cos_forwarded_result_out[49]
  PIN ra_read_cos_forwarded_result_out[4]
    DIRECTION OUTPUT ;
    USE SIGNAL ;
    PORT
      LAYER met3 ;
        RECT  2999.2 556.43 3000 556.73 ;
    END
  END ra_read_cos_forwarded_result_out[4]
  PIN ra_read_cos_forwarded_result_out[50]
    DIRECTION OUTPUT ;
    USE SIGNAL ;
    PORT
      LAYER met3 ;
        RECT  2999.2 827.07 3000 827.37 ;
    END
  END ra_read_cos_forwarded_result_out[50]
  PIN ra_read_cos_forwarded_result_out[51]
    DIRECTION OUTPUT ;
    USE SIGNAL ;
    PORT
      LAYER met3 ;
        RECT  2999.2 209.63 3000 209.93 ;
    END
  END ra_read_cos_forwarded_result_out[51]
  PIN ra_read_cos_forwarded_result_out[52]
    DIRECTION OUTPUT ;
    USE SIGNAL ;
    PORT
      LAYER met3 ;
        RECT  2999.2 434.03 3000 434.33 ;
    END
  END ra_read_cos_forwarded_result_out[52]
  PIN ra_read_cos_forwarded_result_out[53]
    DIRECTION OUTPUT ;
    USE SIGNAL ;
    PORT
      LAYER met3 ;
        RECT  2999.2 502.03 3000 502.33 ;
    END
  END ra_read_cos_forwarded_result_out[53]
  PIN ra_read_cos_forwarded_result_out[54]
    DIRECTION OUTPUT ;
    USE SIGNAL ;
    PORT
      LAYER met3 ;
        RECT  2999.2 812.11 3000 812.41 ;
    END
  END ra_read_cos_forwarded_result_out[54]
  PIN ra_read_cos_forwarded_result_out[55]
    DIRECTION OUTPUT ;
    USE SIGNAL ;
    PORT
      LAYER met3 ;
        RECT  2999.2 341.55 3000 341.85 ;
    END
  END ra_read_cos_forwarded_result_out[55]
  PIN ra_read_cos_forwarded_result_out[56]
    DIRECTION OUTPUT ;
    USE SIGNAL ;
    PORT
      LAYER met3 ;
        RECT  2999.2 1312.59 3000 1312.89 ;
    END
  END ra_read_cos_forwarded_result_out[56]
  PIN ra_read_cos_forwarded_result_out[57]
    DIRECTION OUTPUT ;
    USE SIGNAL ;
    PORT
      LAYER met3 ;
        RECT  2999.2 1046.03 3000 1046.33 ;
    END
  END ra_read_cos_forwarded_result_out[57]
  PIN ra_read_cos_forwarded_result_out[58]
    DIRECTION OUTPUT ;
    USE SIGNAL ;
    PORT
      LAYER met3 ;
        RECT  2999.2 1320.75 3000 1321.05 ;
    END
  END ra_read_cos_forwarded_result_out[58]
  PIN ra_read_cos_forwarded_result_out[59]
    DIRECTION OUTPUT ;
    USE SIGNAL ;
    PORT
      LAYER met3 ;
        RECT  2999.2 259.95 3000 260.25 ;
    END
  END ra_read_cos_forwarded_result_out[59]
  PIN ra_read_cos_forwarded_result_out[5]
    DIRECTION OUTPUT ;
    USE SIGNAL ;
    PORT
      LAYER met3 ;
        RECT  2999.2 1488.03 3000 1488.33 ;
    END
  END ra_read_cos_forwarded_result_out[5]
  PIN ra_read_cos_forwarded_result_out[60]
    DIRECTION OUTPUT ;
    USE SIGNAL ;
    PORT
      LAYER met3 ;
        RECT  2999.2 495.23 3000 495.53 ;
    END
  END ra_read_cos_forwarded_result_out[60]
  PIN ra_read_cos_forwarded_result_out[61]
    DIRECTION OUTPUT ;
    USE SIGNAL ;
    PORT
      LAYER met3 ;
        RECT  2999.2 1371.07 3000 1371.37 ;
    END
  END ra_read_cos_forwarded_result_out[61]
  PIN ra_read_cos_forwarded_result_out[62]
    DIRECTION OUTPUT ;
    USE SIGNAL ;
    PORT
      LAYER met3 ;
        RECT  2999.2 538.75 3000 539.05 ;
    END
  END ra_read_cos_forwarded_result_out[62]
  PIN ra_read_cos_forwarded_result_out[63]
    DIRECTION OUTPUT ;
    USE SIGNAL ;
    PORT
      LAYER met3 ;
        RECT  2999.2 172.91 3000 173.21 ;
    END
  END ra_read_cos_forwarded_result_out[63]
  PIN ra_read_cos_forwarded_result_out[64]
    DIRECTION OUTPUT ;
    USE SIGNAL ;
    PORT
      LAYER met3 ;
        RECT  2999.2 1120.83 3000 1121.13 ;
    END
  END ra_read_cos_forwarded_result_out[64]
  PIN ra_read_cos_forwarded_result_out[65]
    DIRECTION OUTPUT ;
    USE SIGNAL ;
    PORT
      LAYER met3 ;
        RECT  2999.2 858.35 3000 858.65 ;
    END
  END ra_read_cos_forwarded_result_out[65]
  PIN ra_read_cos_forwarded_result_out[66]
    DIRECTION OUTPUT ;
    USE SIGNAL ;
    PORT
      LAYER met3 ;
        RECT  2999.2 1148.03 3000 1148.33 ;
    END
  END ra_read_cos_forwarded_result_out[66]
  PIN ra_read_cos_forwarded_result_out[67]
    DIRECTION OUTPUT ;
    USE SIGNAL ;
    PORT
      LAYER met3 ;
        RECT  2999.2 911.39 3000 911.69 ;
    END
  END ra_read_cos_forwarded_result_out[67]
  PIN ra_read_cos_forwarded_result_out[68]
    DIRECTION OUTPUT ;
    USE SIGNAL ;
    PORT
      LAYER met3 ;
        RECT  2999.2 163.39 3000 163.69 ;
    END
  END ra_read_cos_forwarded_result_out[68]
  PIN ra_read_cos_forwarded_result_out[69]
    DIRECTION OUTPUT ;
    USE SIGNAL ;
    PORT
      LAYER met3 ;
        RECT  2999.2 412.27 3000 412.57 ;
    END
  END ra_read_cos_forwarded_result_out[69]
  PIN ra_read_cos_forwarded_result_out[6]
    DIRECTION OUTPUT ;
    USE SIGNAL ;
    PORT
      LAYER met3 ;
        RECT  2999.2 429.95 3000 430.25 ;
    END
  END ra_read_cos_forwarded_result_out[6]
  PIN ra_read_cos_forwarded_result_out[70]
    DIRECTION OUTPUT ;
    USE SIGNAL ;
    PORT
      LAYER met3 ;
        RECT  2999.2 1293.55 3000 1293.85 ;
    END
  END ra_read_cos_forwarded_result_out[70]
  PIN ra_read_cos_forwarded_result_out[71]
    DIRECTION OUTPUT ;
    USE SIGNAL ;
    PORT
      LAYER met3 ;
        RECT  2999.2 1190.19 3000 1190.49 ;
    END
  END ra_read_cos_forwarded_result_out[71]
  PIN ra_read_cos_forwarded_result_out[72]
    DIRECTION OUTPUT ;
    USE SIGNAL ;
    PORT
      LAYER met3 ;
        RECT  2999.2 1016.11 3000 1016.41 ;
    END
  END ra_read_cos_forwarded_result_out[72]
  PIN ra_read_cos_forwarded_result_out[73]
    DIRECTION OUTPUT ;
    USE SIGNAL ;
    PORT
      LAYER met3 ;
        RECT  2999.2 776.75 3000 777.05 ;
    END
  END ra_read_cos_forwarded_result_out[73]
  PIN ra_read_cos_forwarded_result_out[74]
    DIRECTION OUTPUT ;
    USE SIGNAL ;
    PORT
      LAYER met3 ;
        RECT  2999.2 1073.23 3000 1073.53 ;
    END
  END ra_read_cos_forwarded_result_out[74]
  PIN ra_read_cos_forwarded_result_out[75]
    DIRECTION OUTPUT ;
    USE SIGNAL ;
    PORT
      LAYER met3 ;
        RECT  2999.2 701.95 3000 702.25 ;
    END
  END ra_read_cos_forwarded_result_out[75]
  PIN ra_read_cos_forwarded_result_out[76]
    DIRECTION OUTPUT ;
    USE SIGNAL ;
    PORT
      LAYER met3 ;
        RECT  2999.2 991.63 3000 991.93 ;
    END
  END ra_read_cos_forwarded_result_out[76]
  PIN ra_read_cos_forwarded_result_out[77]
    DIRECTION OUTPUT ;
    USE SIGNAL ;
    PORT
      LAYER met3 ;
        RECT  2999.2 691.07 3000 691.37 ;
    END
  END ra_read_cos_forwarded_result_out[77]
  PIN ra_read_cos_forwarded_result_out[78]
    DIRECTION OUTPUT ;
    USE SIGNAL ;
    PORT
      LAYER met3 ;
        RECT  2999.2 922.27 3000 922.57 ;
    END
  END ra_read_cos_forwarded_result_out[78]
  PIN ra_read_cos_forwarded_result_out[79]
    DIRECTION OUTPUT ;
    USE SIGNAL ;
    PORT
      LAYER met3 ;
        RECT  2999.2 633.95 3000 634.25 ;
    END
  END ra_read_cos_forwarded_result_out[79]
  PIN ra_read_cos_forwarded_result_out[7]
    DIRECTION OUTPUT ;
    USE SIGNAL ;
    PORT
      LAYER met3 ;
        RECT  2999.2 730.51 3000 730.81 ;
    END
  END ra_read_cos_forwarded_result_out[7]
  PIN ra_read_cos_forwarded_result_out[80]
    DIRECTION OUTPUT ;
    USE SIGNAL ;
    PORT
      LAYER met3 ;
        RECT  2999.2 155.23 3000 155.53 ;
    END
  END ra_read_cos_forwarded_result_out[80]
  PIN ra_read_cos_forwarded_result_out[81]
    DIRECTION OUTPUT ;
    USE SIGNAL ;
    PORT
      LAYER met3 ;
        RECT  2999.2 1214.67 3000 1214.97 ;
    END
  END ra_read_cos_forwarded_result_out[81]
  PIN ra_read_cos_forwarded_result_out[82]
    DIRECTION OUTPUT ;
    USE SIGNAL ;
    PORT
      LAYER met3 ;
        RECT  2999.2 485.71 3000 486.01 ;
    END
  END ra_read_cos_forwarded_result_out[82]
  PIN ra_read_cos_forwarded_result_out[83]
    DIRECTION OUTPUT ;
    USE SIGNAL ;
    PORT
      LAYER met3 ;
        RECT  2999.2 265.39 3000 265.69 ;
    END
  END ra_read_cos_forwarded_result_out[83]
  PIN ra_read_cos_forwarded_result_out[84]
    DIRECTION OUTPUT ;
    USE SIGNAL ;
    PORT
      LAYER met3 ;
        RECT  2999.2 1051.47 3000 1051.77 ;
    END
  END ra_read_cos_forwarded_result_out[84]
  PIN ra_read_cos_forwarded_result_out[85]
    DIRECTION OUTPUT ;
    USE SIGNAL ;
    PORT
      LAYER met3 ;
        RECT  2999.2 731.87 3000 732.17 ;
    END
  END ra_read_cos_forwarded_result_out[85]
  PIN ra_read_cos_forwarded_result_out[86]
    DIRECTION OUTPUT ;
    USE SIGNAL ;
    PORT
      LAYER met3 ;
        RECT  2999.2 696.51 3000 696.81 ;
    END
  END ra_read_cos_forwarded_result_out[86]
  PIN ra_read_cos_forwarded_result_out[87]
    DIRECTION OUTPUT ;
    USE SIGNAL ;
    PORT
      LAYER met3 ;
        RECT  2999.2 1127.63 3000 1127.93 ;
    END
  END ra_read_cos_forwarded_result_out[87]
  PIN ra_read_cos_forwarded_result_out[88]
    DIRECTION OUTPUT ;
    USE SIGNAL ;
    PORT
      LAYER met3 ;
        RECT  2999.2 436.75 3000 437.05 ;
    END
  END ra_read_cos_forwarded_result_out[88]
  PIN ra_read_cos_forwarded_result_out[89]
    DIRECTION OUTPUT ;
    USE SIGNAL ;
    PORT
      LAYER met3 ;
        RECT  2999.2 342.91 3000 343.21 ;
    END
  END ra_read_cos_forwarded_result_out[89]
  PIN ra_read_cos_forwarded_result_out[8]
    DIRECTION OUTPUT ;
    USE SIGNAL ;
    PORT
      LAYER met3 ;
        RECT  2999.2 583.63 3000 583.93 ;
    END
  END ra_read_cos_forwarded_result_out[8]
  PIN ra_read_cos_forwarded_result_out[90]
    DIRECTION OUTPUT ;
    USE SIGNAL ;
    PORT
      LAYER met3 ;
        RECT  2999.2 579.55 3000 579.85 ;
    END
  END ra_read_cos_forwarded_result_out[90]
  PIN ra_read_cos_forwarded_result_out[91]
    DIRECTION OUTPUT ;
    USE SIGNAL ;
    PORT
      LAYER met3 ;
        RECT  2999.2 159.31 3000 159.61 ;
    END
  END ra_read_cos_forwarded_result_out[91]
  PIN ra_read_cos_forwarded_result_out[92]
    DIRECTION OUTPUT ;
    USE SIGNAL ;
    PORT
      LAYER met3 ;
        RECT  2999.2 1122.19 3000 1122.49 ;
    END
  END ra_read_cos_forwarded_result_out[92]
  PIN ra_read_cos_forwarded_result_out[93]
    DIRECTION OUTPUT ;
    USE SIGNAL ;
    PORT
      LAYER met3 ;
        RECT  2999.2 982.11 3000 982.41 ;
    END
  END ra_read_cos_forwarded_result_out[93]
  PIN ra_read_cos_forwarded_result_out[94]
    DIRECTION OUTPUT ;
    USE SIGNAL ;
    PORT
      LAYER met3 ;
        RECT  2999.2 1464.91 3000 1465.21 ;
    END
  END ra_read_cos_forwarded_result_out[94]
  PIN ra_read_cos_forwarded_result_out[95]
    DIRECTION OUTPUT ;
    USE SIGNAL ;
    PORT
      LAYER met3 ;
        RECT  2999.2 1164.35 3000 1164.65 ;
    END
  END ra_read_cos_forwarded_result_out[95]
  PIN ra_read_cos_forwarded_result_out[96]
    DIRECTION OUTPUT ;
    USE SIGNAL ;
    PORT
      LAYER met3 ;
        RECT  2999.2 1108.59 3000 1108.89 ;
    END
  END ra_read_cos_forwarded_result_out[96]
  PIN ra_read_cos_forwarded_result_out[97]
    DIRECTION OUTPUT ;
    USE SIGNAL ;
    PORT
      LAYER met3 ;
        RECT  2999.2 1479.87 3000 1480.17 ;
    END
  END ra_read_cos_forwarded_result_out[97]
  PIN ra_read_cos_forwarded_result_out[98]
    DIRECTION OUTPUT ;
    USE SIGNAL ;
    PORT
      LAYER met3 ;
        RECT  2999.2 780.83 3000 781.13 ;
    END
  END ra_read_cos_forwarded_result_out[98]
  PIN ra_read_cos_forwarded_result_out[99]
    DIRECTION OUTPUT ;
    USE SIGNAL ;
    PORT
      LAYER met3 ;
        RECT  2999.2 508.83 3000 509.13 ;
    END
  END ra_read_cos_forwarded_result_out[99]
  PIN ra_read_cos_forwarded_result_out[9]
    DIRECTION OUTPUT ;
    USE SIGNAL ;
    PORT
      LAYER met3 ;
        RECT  2999.2 1186.11 3000 1186.41 ;
    END
  END ra_read_cos_forwarded_result_out[9]
  PIN ra_read_cos_forwarded_valid_in
    DIRECTION INPUT ;
    USE SIGNAL ;
    PORT
      LAYER met3 ;
        RECT  2999.2 1560.11 3000 1560.41 ;
    END
  END ra_read_cos_forwarded_valid_in
  PIN ra_read_sin_forwarded_empty_out
    DIRECTION OUTPUT ;
    USE SIGNAL ;
    PORT
      LAYER met3 ;
        RECT  2999.2 1792.67 3000 1792.97 ;
    END
  END ra_read_sin_forwarded_empty_out
  PIN ra_read_sin_forwarded_phase_in[0]
    DIRECTION INPUT ;
    USE SIGNAL ;
    PORT
      LAYER met3 ;
        RECT  2999.2 2883.39 3000 2883.69 ;
    END
  END ra_read_sin_forwarded_phase_in[0]
  PIN ra_read_sin_forwarded_phase_in[1]
    DIRECTION INPUT ;
    USE SIGNAL ;
    PORT
      LAYER met3 ;
        RECT  2999.2 2913.31 3000 2913.61 ;
    END
  END ra_read_sin_forwarded_phase_in[1]
  PIN ra_read_sin_forwarded_rden_in
    DIRECTION INPUT ;
    USE SIGNAL ;
    PORT
      LAYER met3 ;
        RECT  2999.2 1818.51 3000 1818.81 ;
    END
  END ra_read_sin_forwarded_rden_in
  PIN ra_read_sin_forwarded_rdy_out
    DIRECTION OUTPUT ;
    USE SIGNAL ;
    PORT
      LAYER met3 ;
        RECT  2999.2 1811.71 3000 1812.01 ;
    END
  END ra_read_sin_forwarded_rdy_out
  PIN ra_read_sin_forwarded_result_out[0]
    DIRECTION OUTPUT ;
    USE SIGNAL ;
    PORT
      LAYER met3 ;
        RECT  2999.2 2891.55 3000 2891.85 ;
    END
  END ra_read_sin_forwarded_result_out[0]
  PIN ra_read_sin_forwarded_result_out[100]
    DIRECTION OUTPUT ;
    USE SIGNAL ;
    PORT
      LAYER met3 ;
        RECT  2999.2 2781.39 3000 2781.69 ;
    END
  END ra_read_sin_forwarded_result_out[100]
  PIN ra_read_sin_forwarded_result_out[101]
    DIRECTION OUTPUT ;
    USE SIGNAL ;
    PORT
      LAYER met3 ;
        RECT  2999.2 3072.43 3000 3072.73 ;
    END
  END ra_read_sin_forwarded_result_out[101]
  PIN ra_read_sin_forwarded_result_out[102]
    DIRECTION OUTPUT ;
    USE SIGNAL ;
    PORT
      LAYER met3 ;
        RECT  2999.2 3171.71 3000 3172.01 ;
    END
  END ra_read_sin_forwarded_result_out[102]
  PIN ra_read_sin_forwarded_result_out[103]
    DIRECTION OUTPUT ;
    USE SIGNAL ;
    PORT
      LAYER met3 ;
        RECT  2999.2 3168.99 3000 3169.29 ;
    END
  END ra_read_sin_forwarded_result_out[103]
  PIN ra_read_sin_forwarded_result_out[104]
    DIRECTION OUTPUT ;
    USE SIGNAL ;
    PORT
      LAYER met3 ;
        RECT  2999.2 2997.63 3000 2997.93 ;
    END
  END ra_read_sin_forwarded_result_out[104]
  PIN ra_read_sin_forwarded_result_out[105]
    DIRECTION OUTPUT ;
    USE SIGNAL ;
    PORT
      LAYER met3 ;
        RECT  2999.2 2750.11 3000 2750.41 ;
    END
  END ra_read_sin_forwarded_result_out[105]
  PIN ra_read_sin_forwarded_result_out[106]
    DIRECTION OUTPUT ;
    USE SIGNAL ;
    PORT
      LAYER met3 ;
        RECT  2999.2 2025.23 3000 2025.53 ;
    END
  END ra_read_sin_forwarded_result_out[106]
  PIN ra_read_sin_forwarded_result_out[107]
    DIRECTION OUTPUT ;
    USE SIGNAL ;
    PORT
      LAYER met3 ;
        RECT  2999.2 2444.11 3000 2444.41 ;
    END
  END ra_read_sin_forwarded_result_out[107]
  PIN ra_read_sin_forwarded_result_out[108]
    DIRECTION OUTPUT ;
    USE SIGNAL ;
    PORT
      LAYER met3 ;
        RECT  2999.2 3170.35 3000 3170.65 ;
    END
  END ra_read_sin_forwarded_result_out[108]
  PIN ra_read_sin_forwarded_result_out[109]
    DIRECTION OUTPUT ;
    USE SIGNAL ;
    PORT
      LAYER met3 ;
        RECT  2999.2 3276.43 3000 3276.73 ;
    END
  END ra_read_sin_forwarded_result_out[109]
  PIN ra_read_sin_forwarded_result_out[10]
    DIRECTION OUTPUT ;
    USE SIGNAL ;
    PORT
      LAYER met3 ;
        RECT  2999.2 2550.19 3000 2550.49 ;
    END
  END ra_read_sin_forwarded_result_out[10]
  PIN ra_read_sin_forwarded_result_out[110]
    DIRECTION OUTPUT ;
    USE SIGNAL ;
    PORT
      LAYER met3 ;
        RECT  2999.2 2925.55 3000 2925.85 ;
    END
  END ra_read_sin_forwarded_result_out[110]
  PIN ra_read_sin_forwarded_result_out[111]
    DIRECTION OUTPUT ;
    USE SIGNAL ;
    PORT
      LAYER met3 ;
        RECT  2999.2 3296.83 3000 3297.13 ;
    END
  END ra_read_sin_forwarded_result_out[111]
  PIN ra_read_sin_forwarded_result_out[112]
    DIRECTION OUTPUT ;
    USE SIGNAL ;
    PORT
      LAYER met3 ;
        RECT  2999.2 3249.23 3000 3249.53 ;
    END
  END ra_read_sin_forwarded_result_out[112]
  PIN ra_read_sin_forwarded_result_out[113]
    DIRECTION OUTPUT ;
    USE SIGNAL ;
    PORT
      LAYER met3 ;
        RECT  2999.2 2158.51 3000 2158.81 ;
    END
  END ra_read_sin_forwarded_result_out[113]
  PIN ra_read_sin_forwarded_result_out[114]
    DIRECTION OUTPUT ;
    USE SIGNAL ;
    PORT
      LAYER met3 ;
        RECT  2999.2 1999.39 3000 1999.69 ;
    END
  END ra_read_sin_forwarded_result_out[114]
  PIN ra_read_sin_forwarded_result_out[115]
    DIRECTION OUTPUT ;
    USE SIGNAL ;
    PORT
      LAYER met3 ;
        RECT  2999.2 2318.99 3000 2319.29 ;
    END
  END ra_read_sin_forwarded_result_out[115]
  PIN ra_read_sin_forwarded_result_out[116]
    DIRECTION OUTPUT ;
    USE SIGNAL ;
    PORT
      LAYER met3 ;
        RECT  2999.2 2090.51 3000 2090.81 ;
    END
  END ra_read_sin_forwarded_result_out[116]
  PIN ra_read_sin_forwarded_result_out[117]
    DIRECTION OUTPUT ;
    USE SIGNAL ;
    PORT
      LAYER met3 ;
        RECT  2999.2 2117.71 3000 2118.01 ;
    END
  END ra_read_sin_forwarded_result_out[117]
  PIN ra_read_sin_forwarded_result_out[118]
    DIRECTION OUTPUT ;
    USE SIGNAL ;
    PORT
      LAYER met3 ;
        RECT  2999.2 2800.43 3000 2800.73 ;
    END
  END ra_read_sin_forwarded_result_out[118]
  PIN ra_read_sin_forwarded_result_out[119]
    DIRECTION OUTPUT ;
    USE SIGNAL ;
    PORT
      LAYER met3 ;
        RECT  2999.2 2284.99 3000 2285.29 ;
    END
  END ra_read_sin_forwarded_result_out[119]
  PIN ra_read_sin_forwarded_result_out[11]
    DIRECTION OUTPUT ;
    USE SIGNAL ;
    PORT
      LAYER met3 ;
        RECT  2999.2 2876.59 3000 2876.89 ;
    END
  END ra_read_sin_forwarded_result_out[11]
  PIN ra_read_sin_forwarded_result_out[120]
    DIRECTION OUTPUT ;
    USE SIGNAL ;
    PORT
      LAYER met3 ;
        RECT  2999.2 2688.91 3000 2689.21 ;
    END
  END ra_read_sin_forwarded_result_out[120]
  PIN ra_read_sin_forwarded_result_out[121]
    DIRECTION OUTPUT ;
    USE SIGNAL ;
    PORT
      LAYER met3 ;
        RECT  2999.2 2804.51 3000 2804.81 ;
    END
  END ra_read_sin_forwarded_result_out[121]
  PIN ra_read_sin_forwarded_result_out[122]
    DIRECTION OUTPUT ;
    USE SIGNAL ;
    PORT
      LAYER met3 ;
        RECT  2999.2 3151.31 3000 3151.61 ;
    END
  END ra_read_sin_forwarded_result_out[122]
  PIN ra_read_sin_forwarded_result_out[123]
    DIRECTION OUTPUT ;
    USE SIGNAL ;
    PORT
      LAYER met3 ;
        RECT  2999.2 2109.55 3000 2109.85 ;
    END
  END ra_read_sin_forwarded_result_out[123]
  PIN ra_read_sin_forwarded_result_out[124]
    DIRECTION OUTPUT ;
    USE SIGNAL ;
    PORT
      LAYER met3 ;
        RECT  2999.2 3266.91 3000 3267.21 ;
    END
  END ra_read_sin_forwarded_result_out[124]
  PIN ra_read_sin_forwarded_result_out[125]
    DIRECTION OUTPUT ;
    USE SIGNAL ;
    PORT
      LAYER met3 ;
        RECT  2999.2 3162.19 3000 3162.49 ;
    END
  END ra_read_sin_forwarded_result_out[125]
  PIN ra_read_sin_forwarded_result_out[126]
    DIRECTION OUTPUT ;
    USE SIGNAL ;
    PORT
      LAYER met3 ;
        RECT  2999.2 2694.35 3000 2694.65 ;
    END
  END ra_read_sin_forwarded_result_out[126]
  PIN ra_read_sin_forwarded_result_out[127]
    DIRECTION OUTPUT ;
    USE SIGNAL ;
    PORT
      LAYER met3 ;
        RECT  2999.2 2654.91 3000 2655.21 ;
    END
  END ra_read_sin_forwarded_result_out[127]
  PIN ra_read_sin_forwarded_result_out[128]
    DIRECTION OUTPUT ;
    USE SIGNAL ;
    PORT
      LAYER met3 ;
        RECT  2999.2 3188.03 3000 3188.33 ;
    END
  END ra_read_sin_forwarded_result_out[128]
  PIN ra_read_sin_forwarded_result_out[129]
    DIRECTION OUTPUT ;
    USE SIGNAL ;
    PORT
      LAYER met3 ;
        RECT  2999.2 3090.11 3000 3090.41 ;
    END
  END ra_read_sin_forwarded_result_out[129]
  PIN ra_read_sin_forwarded_result_out[12]
    DIRECTION OUTPUT ;
    USE SIGNAL ;
    PORT
      LAYER met3 ;
        RECT  2999.2 2244.19 3000 2244.49 ;
    END
  END ra_read_sin_forwarded_result_out[12]
  PIN ra_read_sin_forwarded_result_out[130]
    DIRECTION OUTPUT ;
    USE SIGNAL ;
    PORT
      LAYER met3 ;
        RECT  2999.2 2304.03 3000 2304.33 ;
    END
  END ra_read_sin_forwarded_result_out[130]
  PIN ra_read_sin_forwarded_result_out[131]
    DIRECTION OUTPUT ;
    USE SIGNAL ;
    PORT
      LAYER met3 ;
        RECT  2999.2 2381.55 3000 2381.85 ;
    END
  END ra_read_sin_forwarded_result_out[131]
  PIN ra_read_sin_forwarded_result_out[132]
    DIRECTION OUTPUT ;
    USE SIGNAL ;
    PORT
      LAYER met3 ;
        RECT  2999.2 2324.43 3000 2324.73 ;
    END
  END ra_read_sin_forwarded_result_out[132]
  PIN ra_read_sin_forwarded_result_out[133]
    DIRECTION OUTPUT ;
    USE SIGNAL ;
    PORT
      LAYER met3 ;
        RECT  2999.2 2561.07 3000 2561.37 ;
    END
  END ra_read_sin_forwarded_result_out[133]
  PIN ra_read_sin_forwarded_result_out[134]
    DIRECTION OUTPUT ;
    USE SIGNAL ;
    PORT
      LAYER met3 ;
        RECT  2999.2 2237.39 3000 2237.69 ;
    END
  END ra_read_sin_forwarded_result_out[134]
  PIN ra_read_sin_forwarded_result_out[135]
    DIRECTION OUTPUT ;
    USE SIGNAL ;
    PORT
      LAYER met3 ;
        RECT  2999.2 3280.51 3000 3280.81 ;
    END
  END ra_read_sin_forwarded_result_out[135]
  PIN ra_read_sin_forwarded_result_out[136]
    DIRECTION OUTPUT ;
    USE SIGNAL ;
    PORT
      LAYER met3 ;
        RECT  2999.2 2850.75 3000 2851.05 ;
    END
  END ra_read_sin_forwarded_result_out[136]
  PIN ra_read_sin_forwarded_result_out[137]
    DIRECTION OUTPUT ;
    USE SIGNAL ;
    PORT
      LAYER met3 ;
        RECT  2999.2 2108.19 3000 2108.49 ;
    END
  END ra_read_sin_forwarded_result_out[137]
  PIN ra_read_sin_forwarded_result_out[138]
    DIRECTION OUTPUT ;
    USE SIGNAL ;
    PORT
      LAYER met3 ;
        RECT  2999.2 2395.15 3000 2395.45 ;
    END
  END ra_read_sin_forwarded_result_out[138]
  PIN ra_read_sin_forwarded_result_out[139]
    DIRECTION OUTPUT ;
    USE SIGNAL ;
    PORT
      LAYER met3 ;
        RECT  2999.2 2139.47 3000 2139.77 ;
    END
  END ra_read_sin_forwarded_result_out[139]
  PIN ra_read_sin_forwarded_result_out[13]
    DIRECTION OUTPUT ;
    USE SIGNAL ;
    PORT
      LAYER met3 ;
        RECT  2999.2 2816.75 3000 2817.05 ;
    END
  END ra_read_sin_forwarded_result_out[13]
  PIN ra_read_sin_forwarded_result_out[140]
    DIRECTION OUTPUT ;
    USE SIGNAL ;
    PORT
      LAYER met3 ;
        RECT  2999.2 3016.67 3000 3016.97 ;
    END
  END ra_read_sin_forwarded_result_out[140]
  PIN ra_read_sin_forwarded_result_out[141]
    DIRECTION OUTPUT ;
    USE SIGNAL ;
    PORT
      LAYER met3 ;
        RECT  2999.2 2849.39 3000 2849.69 ;
    END
  END ra_read_sin_forwarded_result_out[141]
  PIN ra_read_sin_forwarded_result_out[142]
    DIRECTION OUTPUT ;
    USE SIGNAL ;
    PORT
      LAYER met3 ;
        RECT  2999.2 2010.27 3000 2010.57 ;
    END
  END ra_read_sin_forwarded_result_out[142]
  PIN ra_read_sin_forwarded_result_out[143]
    DIRECTION OUTPUT ;
    USE SIGNAL ;
    PORT
      LAYER met3 ;
        RECT  2999.2 2333.95 3000 2334.25 ;
    END
  END ra_read_sin_forwarded_result_out[143]
  PIN ra_read_sin_forwarded_result_out[144]
    DIRECTION OUTPUT ;
    USE SIGNAL ;
    PORT
      LAYER met3 ;
        RECT  2999.2 3284.59 3000 3284.89 ;
    END
  END ra_read_sin_forwarded_result_out[144]
  PIN ra_read_sin_forwarded_result_out[145]
    DIRECTION OUTPUT ;
    USE SIGNAL ;
    PORT
      LAYER met3 ;
        RECT  2999.2 2501.23 3000 2501.53 ;
    END
  END ra_read_sin_forwarded_result_out[145]
  PIN ra_read_sin_forwarded_result_out[146]
    DIRECTION OUTPUT ;
    USE SIGNAL ;
    PORT
      LAYER met3 ;
        RECT  2999.2 2988.11 3000 2988.41 ;
    END
  END ra_read_sin_forwarded_result_out[146]
  PIN ra_read_sin_forwarded_result_out[147]
    DIRECTION OUTPUT ;
    USE SIGNAL ;
    PORT
      LAYER met3 ;
        RECT  2999.2 3273.71 3000 3274.01 ;
    END
  END ra_read_sin_forwarded_result_out[147]
  PIN ra_read_sin_forwarded_result_out[148]
    DIRECTION OUTPUT ;
    USE SIGNAL ;
    PORT
      LAYER met3 ;
        RECT  2999.2 2952.75 3000 2953.05 ;
    END
  END ra_read_sin_forwarded_result_out[148]
  PIN ra_read_sin_forwarded_result_out[149]
    DIRECTION OUTPUT ;
    USE SIGNAL ;
    PORT
      LAYER met3 ;
        RECT  2999.2 2585.55 3000 2585.85 ;
    END
  END ra_read_sin_forwarded_result_out[149]
  PIN ra_read_sin_forwarded_result_out[14]
    DIRECTION OUTPUT ;
    USE SIGNAL ;
    PORT
      LAYER met3 ;
        RECT  2999.2 2361.15 3000 2361.45 ;
    END
  END ra_read_sin_forwarded_result_out[14]
  PIN ra_read_sin_forwarded_result_out[150]
    DIRECTION OUTPUT ;
    USE SIGNAL ;
    PORT
      LAYER met3 ;
        RECT  2999.2 2668.51 3000 2668.81 ;
    END
  END ra_read_sin_forwarded_result_out[150]
  PIN ra_read_sin_forwarded_result_out[151]
    DIRECTION OUTPUT ;
    USE SIGNAL ;
    PORT
      LAYER met3 ;
        RECT  2999.2 3122.75 3000 3123.05 ;
    END
  END ra_read_sin_forwarded_result_out[151]
  PIN ra_read_sin_forwarded_result_out[152]
    DIRECTION OUTPUT ;
    USE SIGNAL ;
    PORT
      LAYER met3 ;
        RECT  2999.2 2453.63 3000 2453.93 ;
    END
  END ra_read_sin_forwarded_result_out[152]
  PIN ra_read_sin_forwarded_result_out[153]
    DIRECTION OUTPUT ;
    USE SIGNAL ;
    PORT
      LAYER met3 ;
        RECT  2999.2 3071.07 3000 3071.37 ;
    END
  END ra_read_sin_forwarded_result_out[153]
  PIN ra_read_sin_forwarded_result_out[154]
    DIRECTION OUTPUT ;
    USE SIGNAL ;
    PORT
      LAYER met3 ;
        RECT  2999.2 2019.79 3000 2020.09 ;
    END
  END ra_read_sin_forwarded_result_out[154]
  PIN ra_read_sin_forwarded_result_out[155]
    DIRECTION OUTPUT ;
    USE SIGNAL ;
    PORT
      LAYER met3 ;
        RECT  2999.2 2465.87 3000 2466.17 ;
    END
  END ra_read_sin_forwarded_result_out[155]
  PIN ra_read_sin_forwarded_result_out[156]
    DIRECTION OUTPUT ;
    USE SIGNAL ;
    PORT
      LAYER met3 ;
        RECT  2999.2 3192.11 3000 3192.41 ;
    END
  END ra_read_sin_forwarded_result_out[156]
  PIN ra_read_sin_forwarded_result_out[157]
    DIRECTION OUTPUT ;
    USE SIGNAL ;
    PORT
      LAYER met3 ;
        RECT  2999.2 2937.79 3000 2938.09 ;
    END
  END ra_read_sin_forwarded_result_out[157]
  PIN ra_read_sin_forwarded_result_out[158]
    DIRECTION OUTPUT ;
    USE SIGNAL ;
    PORT
      LAYER met3 ;
        RECT  2999.2 2187.07 3000 2187.37 ;
    END
  END ra_read_sin_forwarded_result_out[158]
  PIN ra_read_sin_forwarded_result_out[159]
    DIRECTION OUTPUT ;
    USE SIGNAL ;
    PORT
      LAYER met3 ;
        RECT  2999.2 2335.31 3000 2335.61 ;
    END
  END ra_read_sin_forwarded_result_out[159]
  PIN ra_read_sin_forwarded_result_out[15]
    DIRECTION OUTPUT ;
    USE SIGNAL ;
    PORT
      LAYER met3 ;
        RECT  2999.2 3272.35 3000 3272.65 ;
    END
  END ra_read_sin_forwarded_result_out[15]
  PIN ra_read_sin_forwarded_result_out[160]
    DIRECTION OUTPUT ;
    USE SIGNAL ;
    PORT
      LAYER met3 ;
        RECT  2999.2 2566.51 3000 2566.81 ;
    END
  END ra_read_sin_forwarded_result_out[160]
  PIN ra_read_sin_forwarded_result_out[161]
    DIRECTION OUTPUT ;
    USE SIGNAL ;
    PORT
      LAYER met3 ;
        RECT  2999.2 2185.71 3000 2186.01 ;
    END
  END ra_read_sin_forwarded_result_out[161]
  PIN ra_read_sin_forwarded_result_out[162]
    DIRECTION OUTPUT ;
    USE SIGNAL ;
    PORT
      LAYER met3 ;
        RECT  2999.2 2559.71 3000 2560.01 ;
    END
  END ra_read_sin_forwarded_result_out[162]
  PIN ra_read_sin_forwarded_result_out[163]
    DIRECTION OUTPUT ;
    USE SIGNAL ;
    PORT
      LAYER met3 ;
        RECT  2999.2 3277.79 3000 3278.09 ;
    END
  END ra_read_sin_forwarded_result_out[163]
  PIN ra_read_sin_forwarded_result_out[164]
    DIRECTION OUTPUT ;
    USE SIGNAL ;
    PORT
      LAYER met3 ;
        RECT  2999.2 2012.99 3000 2013.29 ;
    END
  END ra_read_sin_forwarded_result_out[164]
  PIN ra_read_sin_forwarded_result_out[165]
    DIRECTION OUTPUT ;
    USE SIGNAL ;
    PORT
      LAYER met3 ;
        RECT  2999.2 2558.35 3000 2558.65 ;
    END
  END ra_read_sin_forwarded_result_out[165]
  PIN ra_read_sin_forwarded_result_out[166]
    DIRECTION OUTPUT ;
    USE SIGNAL ;
    PORT
      LAYER met3 ;
        RECT  2999.2 2658.99 3000 2659.29 ;
    END
  END ra_read_sin_forwarded_result_out[166]
  PIN ra_read_sin_forwarded_result_out[167]
    DIRECTION OUTPUT ;
    USE SIGNAL ;
    PORT
      LAYER met3 ;
        RECT  2999.2 2159.87 3000 2160.17 ;
    END
  END ra_read_sin_forwarded_result_out[167]
  PIN ra_read_sin_forwarded_result_out[168]
    DIRECTION OUTPUT ;
    USE SIGNAL ;
    PORT
      LAYER met3 ;
        RECT  2999.2 2747.39 3000 2747.69 ;
    END
  END ra_read_sin_forwarded_result_out[168]
  PIN ra_read_sin_forwarded_result_out[169]
    DIRECTION OUTPUT ;
    USE SIGNAL ;
    PORT
      LAYER met3 ;
        RECT  2999.2 2403.31 3000 2403.61 ;
    END
  END ra_read_sin_forwarded_result_out[169]
  PIN ra_read_sin_forwarded_result_out[16]
    DIRECTION OUTPUT ;
    USE SIGNAL ;
    PORT
      LAYER met3 ;
        RECT  2999.2 2932.35 3000 2932.65 ;
    END
  END ra_read_sin_forwarded_result_out[16]
  PIN ra_read_sin_forwarded_result_out[170]
    DIRECTION OUTPUT ;
    USE SIGNAL ;
    PORT
      LAYER met3 ;
        RECT  2999.2 3281.87 3000 3282.17 ;
    END
  END ra_read_sin_forwarded_result_out[170]
  PIN ra_read_sin_forwarded_result_out[171]
    DIRECTION OUTPUT ;
    USE SIGNAL ;
    PORT
      LAYER met3 ;
        RECT  2999.2 2238.75 3000 2239.05 ;
    END
  END ra_read_sin_forwarded_result_out[171]
  PIN ra_read_sin_forwarded_result_out[172]
    DIRECTION OUTPUT ;
    USE SIGNAL ;
    PORT
      LAYER met3 ;
        RECT  2999.2 2984.03 3000 2984.33 ;
    END
  END ra_read_sin_forwarded_result_out[172]
  PIN ra_read_sin_forwarded_result_out[173]
    DIRECTION OUTPUT ;
    USE SIGNAL ;
    PORT
      LAYER met3 ;
        RECT  2999.2 3288.67 3000 3288.97 ;
    END
  END ra_read_sin_forwarded_result_out[173]
  PIN ra_read_sin_forwarded_result_out[174]
    DIRECTION OUTPUT ;
    USE SIGNAL ;
    PORT
      LAYER met3 ;
        RECT  2999.2 3045.23 3000 3045.53 ;
    END
  END ra_read_sin_forwarded_result_out[174]
  PIN ra_read_sin_forwarded_result_out[175]
    DIRECTION OUTPUT ;
    USE SIGNAL ;
    PORT
      LAYER met3 ;
        RECT  2999.2 3011.23 3000 3011.53 ;
    END
  END ra_read_sin_forwarded_result_out[175]
  PIN ra_read_sin_forwarded_result_out[176]
    DIRECTION OUTPUT ;
    USE SIGNAL ;
    PORT
      LAYER met3 ;
        RECT  2999.2 2270.03 3000 2270.33 ;
    END
  END ra_read_sin_forwarded_result_out[176]
  PIN ra_read_sin_forwarded_result_out[177]
    DIRECTION OUTPUT ;
    USE SIGNAL ;
    PORT
      LAYER met3 ;
        RECT  2999.2 2630.43 3000 2630.73 ;
    END
  END ra_read_sin_forwarded_result_out[177]
  PIN ra_read_sin_forwarded_result_out[178]
    DIRECTION OUTPUT ;
    USE SIGNAL ;
    PORT
      LAYER met3 ;
        RECT  2999.2 2639.95 3000 2640.25 ;
    END
  END ra_read_sin_forwarded_result_out[178]
  PIN ra_read_sin_forwarded_result_out[179]
    DIRECTION OUTPUT ;
    USE SIGNAL ;
    PORT
      LAYER met3 ;
        RECT  2999.2 2104.11 3000 2104.41 ;
    END
  END ra_read_sin_forwarded_result_out[179]
  PIN ra_read_sin_forwarded_result_out[17]
    DIRECTION OUTPUT ;
    USE SIGNAL ;
    PORT
      LAYER met3 ;
        RECT  2999.2 2577.39 3000 2577.69 ;
    END
  END ra_read_sin_forwarded_result_out[17]
  PIN ra_read_sin_forwarded_result_out[180]
    DIRECTION OUTPUT ;
    USE SIGNAL ;
    PORT
      LAYER met3 ;
        RECT  2999.2 2351.63 3000 2351.93 ;
    END
  END ra_read_sin_forwarded_result_out[180]
  PIN ra_read_sin_forwarded_result_out[181]
    DIRECTION OUTPUT ;
    USE SIGNAL ;
    PORT
      LAYER met3 ;
        RECT  2999.2 2812.67 3000 2812.97 ;
    END
  END ra_read_sin_forwarded_result_out[181]
  PIN ra_read_sin_forwarded_result_out[182]
    DIRECTION OUTPUT ;
    USE SIGNAL ;
    PORT
      LAYER met3 ;
        RECT  2999.2 2127.23 3000 2127.53 ;
    END
  END ra_read_sin_forwarded_result_out[182]
  PIN ra_read_sin_forwarded_result_out[183]
    DIRECTION OUTPUT ;
    USE SIGNAL ;
    PORT
      LAYER met3 ;
        RECT  2999.2 2150.35 3000 2150.65 ;
    END
  END ra_read_sin_forwarded_result_out[183]
  PIN ra_read_sin_forwarded_result_out[184]
    DIRECTION OUTPUT ;
    USE SIGNAL ;
    PORT
      LAYER met3 ;
        RECT  2999.2 2199.31 3000 2199.61 ;
    END
  END ra_read_sin_forwarded_result_out[184]
  PIN ra_read_sin_forwarded_result_out[185]
    DIRECTION OUTPUT ;
    USE SIGNAL ;
    PORT
      LAYER met3 ;
        RECT  2999.2 3290.03 3000 3290.33 ;
    END
  END ra_read_sin_forwarded_result_out[185]
  PIN ra_read_sin_forwarded_result_out[186]
    DIRECTION OUTPUT ;
    USE SIGNAL ;
    PORT
      LAYER met3 ;
        RECT  2999.2 3113.23 3000 3113.53 ;
    END
  END ra_read_sin_forwarded_result_out[186]
  PIN ra_read_sin_forwarded_result_out[187]
    DIRECTION OUTPUT ;
    USE SIGNAL ;
    PORT
      LAYER met3 ;
        RECT  2999.2 2427.79 3000 2428.09 ;
    END
  END ra_read_sin_forwarded_result_out[187]
  PIN ra_read_sin_forwarded_result_out[188]
    DIRECTION OUTPUT ;
    USE SIGNAL ;
    PORT
      LAYER met3 ;
        RECT  2999.2 2246.91 3000 2247.21 ;
    END
  END ra_read_sin_forwarded_result_out[188]
  PIN ra_read_sin_forwarded_result_out[189]
    DIRECTION OUTPUT ;
    USE SIGNAL ;
    PORT
      LAYER met3 ;
        RECT  2999.2 2004.83 3000 2005.13 ;
    END
  END ra_read_sin_forwarded_result_out[189]
  PIN ra_read_sin_forwarded_result_out[18]
    DIRECTION OUTPUT ;
    USE SIGNAL ;
    PORT
      LAYER met3 ;
        RECT  2999.2 3283.23 3000 3283.53 ;
    END
  END ra_read_sin_forwarded_result_out[18]
  PIN ra_read_sin_forwarded_result_out[190]
    DIRECTION OUTPUT ;
    USE SIGNAL ;
    PORT
      LAYER met3 ;
        RECT  2999.2 2493.07 3000 2493.37 ;
    END
  END ra_read_sin_forwarded_result_out[190]
  PIN ra_read_sin_forwarded_result_out[191]
    DIRECTION OUTPUT ;
    USE SIGNAL ;
    PORT
      LAYER met3 ;
        RECT  2999.2 2801.79 3000 2802.09 ;
    END
  END ra_read_sin_forwarded_result_out[191]
  PIN ra_read_sin_forwarded_result_out[192]
    DIRECTION OUTPUT ;
    USE SIGNAL ;
    PORT
      LAYER met3 ;
        RECT  2999.2 2302.67 3000 2302.97 ;
    END
  END ra_read_sin_forwarded_result_out[192]
  PIN ra_read_sin_forwarded_result_out[193]
    DIRECTION OUTPUT ;
    USE SIGNAL ;
    PORT
      LAYER met3 ;
        RECT  2999.2 2416.91 3000 2417.21 ;
    END
  END ra_read_sin_forwarded_result_out[193]
  PIN ra_read_sin_forwarded_result_out[194]
    DIRECTION OUTPUT ;
    USE SIGNAL ;
    PORT
      LAYER met3 ;
        RECT  2999.2 2018.43 3000 2018.73 ;
    END
  END ra_read_sin_forwarded_result_out[194]
  PIN ra_read_sin_forwarded_result_out[195]
    DIRECTION OUTPUT ;
    USE SIGNAL ;
    PORT
      LAYER met3 ;
        RECT  2999.2 2002.11 3000 2002.41 ;
    END
  END ra_read_sin_forwarded_result_out[195]
  PIN ra_read_sin_forwarded_result_out[196]
    DIRECTION OUTPUT ;
    USE SIGNAL ;
    PORT
      LAYER met3 ;
        RECT  2999.2 2211.55 3000 2211.85 ;
    END
  END ra_read_sin_forwarded_result_out[196]
  PIN ra_read_sin_forwarded_result_out[197]
    DIRECTION OUTPUT ;
    USE SIGNAL ;
    PORT
      LAYER met3 ;
        RECT  2999.2 2385.63 3000 2385.93 ;
    END
  END ra_read_sin_forwarded_result_out[197]
  PIN ra_read_sin_forwarded_result_out[198]
    DIRECTION OUTPUT ;
    USE SIGNAL ;
    PORT
      LAYER met3 ;
        RECT  2999.2 3077.87 3000 3078.17 ;
    END
  END ra_read_sin_forwarded_result_out[198]
  PIN ra_read_sin_forwarded_result_out[199]
    DIRECTION OUTPUT ;
    USE SIGNAL ;
    PORT
      LAYER met3 ;
        RECT  2999.2 2299.95 3000 2300.25 ;
    END
  END ra_read_sin_forwarded_result_out[199]
  PIN ra_read_sin_forwarded_result_out[19]
    DIRECTION OUTPUT ;
    USE SIGNAL ;
    PORT
      LAYER met3 ;
        RECT  2999.2 2663.07 3000 2663.37 ;
    END
  END ra_read_sin_forwarded_result_out[19]
  PIN ra_read_sin_forwarded_result_out[1]
    DIRECTION OUTPUT ;
    USE SIGNAL ;
    PORT
      LAYER met3 ;
        RECT  2999.2 2661.71 3000 2662.01 ;
    END
  END ra_read_sin_forwarded_result_out[1]
  PIN ra_read_sin_forwarded_result_out[200]
    DIRECTION OUTPUT ;
    USE SIGNAL ;
    PORT
      LAYER met3 ;
        RECT  2999.2 2461.79 3000 2462.09 ;
    END
  END ra_read_sin_forwarded_result_out[200]
  PIN ra_read_sin_forwarded_result_out[201]
    DIRECTION OUTPUT ;
    USE SIGNAL ;
    PORT
      LAYER met3 ;
        RECT  2999.2 3291.39 3000 3291.69 ;
    END
  END ra_read_sin_forwarded_result_out[201]
  PIN ra_read_sin_forwarded_result_out[202]
    DIRECTION OUTPUT ;
    USE SIGNAL ;
    PORT
      LAYER met3 ;
        RECT  2999.2 2604.59 3000 2604.89 ;
    END
  END ra_read_sin_forwarded_result_out[202]
  PIN ra_read_sin_forwarded_result_out[203]
    DIRECTION OUTPUT ;
    USE SIGNAL ;
    PORT
      LAYER met3 ;
        RECT  2999.2 2264.59 3000 2264.89 ;
    END
  END ra_read_sin_forwarded_result_out[203]
  PIN ra_read_sin_forwarded_result_out[204]
    DIRECTION OUTPUT ;
    USE SIGNAL ;
    PORT
      LAYER met3 ;
        RECT  2999.2 3018.03 3000 3018.33 ;
    END
  END ra_read_sin_forwarded_result_out[204]
  PIN ra_read_sin_forwarded_result_out[205]
    DIRECTION OUTPUT ;
    USE SIGNAL ;
    PORT
      LAYER met3 ;
        RECT  2999.2 3155.39 3000 3155.69 ;
    END
  END ra_read_sin_forwarded_result_out[205]
  PIN ra_read_sin_forwarded_result_out[206]
    DIRECTION OUTPUT ;
    USE SIGNAL ;
    PORT
      LAYER met3 ;
        RECT  2999.2 2811.31 3000 2811.61 ;
    END
  END ra_read_sin_forwarded_result_out[206]
  PIN ra_read_sin_forwarded_result_out[207]
    DIRECTION OUTPUT ;
    USE SIGNAL ;
    PORT
      LAYER met3 ;
        RECT  2999.2 2724.27 3000 2724.57 ;
    END
  END ra_read_sin_forwarded_result_out[207]
  PIN ra_read_sin_forwarded_result_out[208]
    DIRECTION OUTPUT ;
    USE SIGNAL ;
    PORT
      LAYER met3 ;
        RECT  2999.2 2687.55 3000 2687.85 ;
    END
  END ra_read_sin_forwarded_result_out[208]
  PIN ra_read_sin_forwarded_result_out[209]
    DIRECTION OUTPUT ;
    USE SIGNAL ;
    PORT
      LAYER met3 ;
        RECT  2999.2 2837.15 3000 2837.45 ;
    END
  END ra_read_sin_forwarded_result_out[209]
  PIN ra_read_sin_forwarded_result_out[20]
    DIRECTION OUTPUT ;
    USE SIGNAL ;
    PORT
      LAYER met3 ;
        RECT  2999.2 2136.75 3000 2137.05 ;
    END
  END ra_read_sin_forwarded_result_out[20]
  PIN ra_read_sin_forwarded_result_out[210]
    DIRECTION OUTPUT ;
    USE SIGNAL ;
    PORT
      LAYER met3 ;
        RECT  2999.2 2524.35 3000 2524.65 ;
    END
  END ra_read_sin_forwarded_result_out[210]
  PIN ra_read_sin_forwarded_result_out[211]
    DIRECTION OUTPUT ;
    USE SIGNAL ;
    PORT
      LAYER met3 ;
        RECT  2999.2 2391.07 3000 2391.37 ;
    END
  END ra_read_sin_forwarded_result_out[211]
  PIN ra_read_sin_forwarded_result_out[212]
    DIRECTION OUTPUT ;
    USE SIGNAL ;
    PORT
      LAYER met3 ;
        RECT  2999.2 3287.31 3000 3287.61 ;
    END
  END ra_read_sin_forwarded_result_out[212]
  PIN ra_read_sin_forwarded_result_out[213]
    DIRECTION OUTPUT ;
    USE SIGNAL ;
    PORT
      LAYER met3 ;
        RECT  2999.2 2000.75 3000 2001.05 ;
    END
  END ra_read_sin_forwarded_result_out[213]
  PIN ra_read_sin_forwarded_result_out[214]
    DIRECTION OUTPUT ;
    USE SIGNAL ;
    PORT
      LAYER met3 ;
        RECT  2999.2 3298.19 3000 3298.49 ;
    END
  END ra_read_sin_forwarded_result_out[214]
  PIN ra_read_sin_forwarded_result_out[215]
    DIRECTION OUTPUT ;
    USE SIGNAL ;
    PORT
      LAYER met3 ;
        RECT  2999.2 2773.23 3000 2773.53 ;
    END
  END ra_read_sin_forwarded_result_out[215]
  PIN ra_read_sin_forwarded_result_out[216]
    DIRECTION OUTPUT ;
    USE SIGNAL ;
    PORT
      LAYER met3 ;
        RECT  2999.2 2580.11 3000 2580.41 ;
    END
  END ra_read_sin_forwarded_result_out[216]
  PIN ra_read_sin_forwarded_result_out[217]
    DIRECTION OUTPUT ;
    USE SIGNAL ;
    PORT
      LAYER met3 ;
        RECT  2999.2 2338.03 3000 2338.33 ;
    END
  END ra_read_sin_forwarded_result_out[217]
  PIN ra_read_sin_forwarded_result_out[218]
    DIRECTION OUTPUT ;
    USE SIGNAL ;
    PORT
      LAYER met3 ;
        RECT  2999.2 2713.39 3000 2713.69 ;
    END
  END ra_read_sin_forwarded_result_out[218]
  PIN ra_read_sin_forwarded_result_out[219]
    DIRECTION OUTPUT ;
    USE SIGNAL ;
    PORT
      LAYER met3 ;
        RECT  2999.2 2105.47 3000 2105.77 ;
    END
  END ra_read_sin_forwarded_result_out[219]
  PIN ra_read_sin_forwarded_result_out[21]
    DIRECTION OUTPUT ;
    USE SIGNAL ;
    PORT
      LAYER met3 ;
        RECT  2999.2 3270.99 3000 3271.29 ;
    END
  END ra_read_sin_forwarded_result_out[21]
  PIN ra_read_sin_forwarded_result_out[220]
    DIRECTION OUTPUT ;
    USE SIGNAL ;
    PORT
      LAYER met3 ;
        RECT  2999.2 3117.31 3000 3117.61 ;
    END
  END ra_read_sin_forwarded_result_out[220]
  PIN ra_read_sin_forwarded_result_out[221]
    DIRECTION OUTPUT ;
    USE SIGNAL ;
    PORT
      LAYER met3 ;
        RECT  2999.2 2967.71 3000 2968.01 ;
    END
  END ra_read_sin_forwarded_result_out[221]
  PIN ra_read_sin_forwarded_result_out[222]
    DIRECTION OUTPUT ;
    USE SIGNAL ;
    PORT
      LAYER met3 ;
        RECT  2999.2 2721.55 3000 2721.85 ;
    END
  END ra_read_sin_forwarded_result_out[222]
  PIN ra_read_sin_forwarded_result_out[223]
    DIRECTION OUTPUT ;
    USE SIGNAL ;
    PORT
      LAYER met3 ;
        RECT  2999.2 2731.07 3000 2731.37 ;
    END
  END ra_read_sin_forwarded_result_out[223]
  PIN ra_read_sin_forwarded_result_out[224]
    DIRECTION OUTPUT ;
    USE SIGNAL ;
    PORT
      LAYER met3 ;
        RECT  2999.2 2701.15 3000 2701.45 ;
    END
  END ra_read_sin_forwarded_result_out[224]
  PIN ra_read_sin_forwarded_result_out[225]
    DIRECTION OUTPUT ;
    USE SIGNAL ;
    PORT
      LAYER met3 ;
        RECT  2999.2 3030.27 3000 3030.57 ;
    END
  END ra_read_sin_forwarded_result_out[225]
  PIN ra_read_sin_forwarded_result_out[226]
    DIRECTION OUTPUT ;
    USE SIGNAL ;
    PORT
      LAYER met3 ;
        RECT  2999.2 3052.03 3000 3052.33 ;
    END
  END ra_read_sin_forwarded_result_out[226]
  PIN ra_read_sin_forwarded_result_out[227]
    DIRECTION OUTPUT ;
    USE SIGNAL ;
    PORT
      LAYER met3 ;
        RECT  2999.2 2650.83 3000 2651.13 ;
    END
  END ra_read_sin_forwarded_result_out[227]
  PIN ra_read_sin_forwarded_result_out[228]
    DIRECTION OUTPUT ;
    USE SIGNAL ;
    PORT
      LAYER met3 ;
        RECT  2999.2 3181.23 3000 3181.53 ;
    END
  END ra_read_sin_forwarded_result_out[228]
  PIN ra_read_sin_forwarded_result_out[229]
    DIRECTION OUTPUT ;
    USE SIGNAL ;
    PORT
      LAYER met3 ;
        RECT  2999.2 3103.71 3000 3104.01 ;
    END
  END ra_read_sin_forwarded_result_out[229]
  PIN ra_read_sin_forwarded_result_out[22]
    DIRECTION OUTPUT ;
    USE SIGNAL ;
    PORT
      LAYER met3 ;
        RECT  2999.2 2603.23 3000 2603.53 ;
    END
  END ra_read_sin_forwarded_result_out[22]
  PIN ra_read_sin_forwarded_result_out[230]
    DIRECTION OUTPUT ;
    USE SIGNAL ;
    PORT
      LAYER met3 ;
        RECT  2999.2 2998.99 3000 2999.29 ;
    END
  END ra_read_sin_forwarded_result_out[230]
  PIN ra_read_sin_forwarded_result_out[231]
    DIRECTION OUTPUT ;
    USE SIGNAL ;
    PORT
      LAYER met3 ;
        RECT  2999.2 2505.31 3000 2505.61 ;
    END
  END ra_read_sin_forwarded_result_out[231]
  PIN ra_read_sin_forwarded_result_out[232]
    DIRECTION OUTPUT ;
    USE SIGNAL ;
    PORT
      LAYER met3 ;
        RECT  2999.2 2892.91 3000 2893.21 ;
    END
  END ra_read_sin_forwarded_result_out[232]
  PIN ra_read_sin_forwarded_result_out[233]
    DIRECTION OUTPUT ;
    USE SIGNAL ;
    PORT
      LAYER met3 ;
        RECT  2999.2 2951.39 3000 2951.69 ;
    END
  END ra_read_sin_forwarded_result_out[233]
  PIN ra_read_sin_forwarded_result_out[234]
    DIRECTION OUTPUT ;
    USE SIGNAL ;
    PORT
      LAYER met3 ;
        RECT  2999.2 3185.31 3000 3185.61 ;
    END
  END ra_read_sin_forwarded_result_out[234]
  PIN ra_read_sin_forwarded_result_out[235]
    DIRECTION OUTPUT ;
    USE SIGNAL ;
    PORT
      LAYER met3 ;
        RECT  2999.2 2154.43 3000 2154.73 ;
    END
  END ra_read_sin_forwarded_result_out[235]
  PIN ra_read_sin_forwarded_result_out[236]
    DIRECTION OUTPUT ;
    USE SIGNAL ;
    PORT
      LAYER met3 ;
        RECT  2999.2 3174.43 3000 3174.73 ;
    END
  END ra_read_sin_forwarded_result_out[236]
  PIN ra_read_sin_forwarded_result_out[237]
    DIRECTION OUTPUT ;
    USE SIGNAL ;
    PORT
      LAYER met3 ;
        RECT  2999.2 2682.11 3000 2682.41 ;
    END
  END ra_read_sin_forwarded_result_out[237]
  PIN ra_read_sin_forwarded_result_out[238]
    DIRECTION OUTPUT ;
    USE SIGNAL ;
    PORT
      LAYER met3 ;
        RECT  2999.2 2008.91 3000 2009.21 ;
    END
  END ra_read_sin_forwarded_result_out[238]
  PIN ra_read_sin_forwarded_result_out[239]
    DIRECTION OUTPUT ;
    USE SIGNAL ;
    PORT
      LAYER met3 ;
        RECT  2999.2 2245.55 3000 2245.85 ;
    END
  END ra_read_sin_forwarded_result_out[239]
  PIN ra_read_sin_forwarded_result_out[23]
    DIRECTION OUTPUT ;
    USE SIGNAL ;
    PORT
      LAYER met3 ;
        RECT  2999.2 2924.19 3000 2924.49 ;
    END
  END ra_read_sin_forwarded_result_out[23]
  PIN ra_read_sin_forwarded_result_out[240]
    DIRECTION OUTPUT ;
    USE SIGNAL ;
    PORT
      LAYER met3 ;
        RECT  2999.2 2714.75 3000 2715.05 ;
    END
  END ra_read_sin_forwarded_result_out[240]
  PIN ra_read_sin_forwarded_result_out[241]
    DIRECTION OUTPUT ;
    USE SIGNAL ;
    PORT
      LAYER met3 ;
        RECT  2999.2 3220.67 3000 3220.97 ;
    END
  END ra_read_sin_forwarded_result_out[241]
  PIN ra_read_sin_forwarded_result_out[242]
    DIRECTION OUTPUT ;
    USE SIGNAL ;
    PORT
      LAYER met3 ;
        RECT  2999.2 2623.63 3000 2623.93 ;
    END
  END ra_read_sin_forwarded_result_out[242]
  PIN ra_read_sin_forwarded_result_out[243]
    DIRECTION OUTPUT ;
    USE SIGNAL ;
    PORT
      LAYER met3 ;
        RECT  2999.2 2352.99 3000 2353.29 ;
    END
  END ra_read_sin_forwarded_result_out[243]
  PIN ra_read_sin_forwarded_result_out[244]
    DIRECTION OUTPUT ;
    USE SIGNAL ;
    PORT
      LAYER met3 ;
        RECT  2999.2 2471.31 3000 2471.61 ;
    END
  END ra_read_sin_forwarded_result_out[244]
  PIN ra_read_sin_forwarded_result_out[245]
    DIRECTION OUTPUT ;
    USE SIGNAL ;
    PORT
      LAYER met3 ;
        RECT  2999.2 2411.47 3000 2411.77 ;
    END
  END ra_read_sin_forwarded_result_out[245]
  PIN ra_read_sin_forwarded_result_out[246]
    DIRECTION OUTPUT ;
    USE SIGNAL ;
    PORT
      LAYER met3 ;
        RECT  2999.2 3043.87 3000 3044.17 ;
    END
  END ra_read_sin_forwarded_result_out[246]
  PIN ra_read_sin_forwarded_result_out[247]
    DIRECTION OUTPUT ;
    USE SIGNAL ;
    PORT
      LAYER met3 ;
        RECT  2999.2 2415.55 3000 2415.85 ;
    END
  END ra_read_sin_forwarded_result_out[247]
  PIN ra_read_sin_forwarded_result_out[248]
    DIRECTION OUTPUT ;
    USE SIGNAL ;
    PORT
      LAYER met3 ;
        RECT  2999.2 2128.59 3000 2128.89 ;
    END
  END ra_read_sin_forwarded_result_out[248]
  PIN ra_read_sin_forwarded_result_out[249]
    DIRECTION OUTPUT ;
    USE SIGNAL ;
    PORT
      LAYER met3 ;
        RECT  2999.2 3105.07 3000 3105.37 ;
    END
  END ra_read_sin_forwarded_result_out[249]
  PIN ra_read_sin_forwarded_result_out[24]
    DIRECTION OUTPUT ;
    USE SIGNAL ;
    PORT
      LAYER met3 ;
        RECT  2999.2 2895.63 3000 2895.93 ;
    END
  END ra_read_sin_forwarded_result_out[24]
  PIN ra_read_sin_forwarded_result_out[250]
    DIRECTION OUTPUT ;
    USE SIGNAL ;
    PORT
      LAYER met3 ;
        RECT  2999.2 3069.71 3000 3070.01 ;
    END
  END ra_read_sin_forwarded_result_out[250]
  PIN ra_read_sin_forwarded_result_out[251]
    DIRECTION OUTPUT ;
    USE SIGNAL ;
    PORT
      LAYER met3 ;
        RECT  2999.2 2363.87 3000 2364.17 ;
    END
  END ra_read_sin_forwarded_result_out[251]
  PIN ra_read_sin_forwarded_result_out[252]
    DIRECTION OUTPUT ;
    USE SIGNAL ;
    PORT
      LAYER met3 ;
        RECT  2999.2 3020.75 3000 3021.05 ;
    END
  END ra_read_sin_forwarded_result_out[252]
  PIN ra_read_sin_forwarded_result_out[253]
    DIRECTION OUTPUT ;
    USE SIGNAL ;
    PORT
      LAYER met3 ;
        RECT  2999.2 2717.47 3000 2717.77 ;
    END
  END ra_read_sin_forwarded_result_out[253]
  PIN ra_read_sin_forwarded_result_out[254]
    DIRECTION OUTPUT ;
    USE SIGNAL ;
    PORT
      LAYER met3 ;
        RECT  2999.2 2767.79 3000 2768.09 ;
    END
  END ra_read_sin_forwarded_result_out[254]
  PIN ra_read_sin_forwarded_result_out[255]
    DIRECTION OUTPUT ;
    USE SIGNAL ;
    PORT
      LAYER met3 ;
        RECT  2999.2 2884.75 3000 2885.05 ;
    END
  END ra_read_sin_forwarded_result_out[255]
  PIN ra_read_sin_forwarded_result_out[25]
    DIRECTION OUTPUT ;
    USE SIGNAL ;
    PORT
      LAYER met3 ;
        RECT  2999.2 2399.23 3000 2399.53 ;
    END
  END ra_read_sin_forwarded_result_out[25]
  PIN ra_read_sin_forwarded_result_out[26]
    DIRECTION OUTPUT ;
    USE SIGNAL ;
    PORT
      LAYER met3 ;
        RECT  2999.2 2748.75 3000 2749.05 ;
    END
  END ra_read_sin_forwarded_result_out[26]
  PIN ra_read_sin_forwarded_result_out[27]
    DIRECTION OUTPUT ;
    USE SIGNAL ;
    PORT
      LAYER met3 ;
        RECT  2999.2 2138.11 3000 2138.41 ;
    END
  END ra_read_sin_forwarded_result_out[27]
  PIN ra_read_sin_forwarded_result_out[28]
    DIRECTION OUTPUT ;
    USE SIGNAL ;
    PORT
      LAYER met3 ;
        RECT  2999.2 2344.83 3000 2345.13 ;
    END
  END ra_read_sin_forwarded_result_out[28]
  PIN ra_read_sin_forwarded_result_out[29]
    DIRECTION OUTPUT ;
    USE SIGNAL ;
    PORT
      LAYER met3 ;
        RECT  2999.2 3100.99 3000 3101.29 ;
    END
  END ra_read_sin_forwarded_result_out[29]
  PIN ra_read_sin_forwarded_result_out[2]
    DIRECTION OUTPUT ;
    USE SIGNAL ;
    PORT
      LAYER met3 ;
        RECT  2999.2 2445.47 3000 2445.77 ;
    END
  END ra_read_sin_forwarded_result_out[2]
  PIN ra_read_sin_forwarded_result_out[30]
    DIRECTION OUTPUT ;
    USE SIGNAL ;
    PORT
      LAYER met3 ;
        RECT  2999.2 2903.79 3000 2904.09 ;
    END
  END ra_read_sin_forwarded_result_out[30]
  PIN ra_read_sin_forwarded_result_out[31]
    DIRECTION OUTPUT ;
    USE SIGNAL ;
    PORT
      LAYER met3 ;
        RECT  2999.2 2814.03 3000 2814.33 ;
    END
  END ra_read_sin_forwarded_result_out[31]
  PIN ra_read_sin_forwarded_result_out[32]
    DIRECTION OUTPUT ;
    USE SIGNAL ;
    PORT
      LAYER met3 ;
        RECT  2999.2 2370.67 3000 2370.97 ;
    END
  END ra_read_sin_forwarded_result_out[32]
  PIN ra_read_sin_forwarded_result_out[33]
    DIRECTION OUTPUT ;
    USE SIGNAL ;
    PORT
      LAYER met3 ;
        RECT  2999.2 3189.39 3000 3189.69 ;
    END
  END ra_read_sin_forwarded_result_out[33]
  PIN ra_read_sin_forwarded_result_out[34]
    DIRECTION OUTPUT ;
    USE SIGNAL ;
    PORT
      LAYER met3 ;
        RECT  2999.2 2003.47 3000 2003.77 ;
    END
  END ra_read_sin_forwarded_result_out[34]
  PIN ra_read_sin_forwarded_result_out[35]
    DIRECTION OUTPUT ;
    USE SIGNAL ;
    PORT
      LAYER met3 ;
        RECT  2999.2 2827.63 3000 2827.93 ;
    END
  END ra_read_sin_forwarded_result_out[35]
  PIN ra_read_sin_forwarded_result_out[36]
    DIRECTION OUTPUT ;
    USE SIGNAL ;
    PORT
      LAYER met3 ;
        RECT  2999.2 2525.71 3000 2526.01 ;
    END
  END ra_read_sin_forwarded_result_out[36]
  PIN ra_read_sin_forwarded_result_out[37]
    DIRECTION OUTPUT ;
    USE SIGNAL ;
    PORT
      LAYER met3 ;
        RECT  2999.2 2985.39 3000 2985.69 ;
    END
  END ra_read_sin_forwarded_result_out[37]
  PIN ra_read_sin_forwarded_result_out[38]
    DIRECTION OUTPUT ;
    USE SIGNAL ;
    PORT
      LAYER met3 ;
        RECT  2999.2 2871.15 3000 2871.45 ;
    END
  END ra_read_sin_forwarded_result_out[38]
  PIN ra_read_sin_forwarded_result_out[39]
    DIRECTION OUTPUT ;
    USE SIGNAL ;
    PORT
      LAYER met3 ;
        RECT  2999.2 3194.83 3000 3195.13 ;
    END
  END ra_read_sin_forwarded_result_out[39]
  PIN ra_read_sin_forwarded_result_out[3]
    DIRECTION OUTPUT ;
    USE SIGNAL ;
    PORT
      LAYER met3 ;
        RECT  2999.2 2023.87 3000 2024.17 ;
    END
  END ra_read_sin_forwarded_result_out[3]
  PIN ra_read_sin_forwarded_result_out[40]
    DIRECTION OUTPUT ;
    USE SIGNAL ;
    PORT
      LAYER met3 ;
        RECT  2999.2 3015.31 3000 3015.61 ;
    END
  END ra_read_sin_forwarded_result_out[40]
  PIN ra_read_sin_forwarded_result_out[41]
    DIRECTION OUTPUT ;
    USE SIGNAL ;
    PORT
      LAYER met3 ;
        RECT  2999.2 2074.19 3000 2074.49 ;
    END
  END ra_read_sin_forwarded_result_out[41]
  PIN ra_read_sin_forwarded_result_out[42]
    DIRECTION OUTPUT ;
    USE SIGNAL ;
    PORT
      LAYER met3 ;
        RECT  2999.2 3193.47 3000 3193.77 ;
    END
  END ra_read_sin_forwarded_result_out[42]
  PIN ra_read_sin_forwarded_result_out[43]
    DIRECTION OUTPUT ;
    USE SIGNAL ;
    PORT
      LAYER met3 ;
        RECT  2999.2 2248.27 3000 2248.57 ;
    END
  END ra_read_sin_forwarded_result_out[43]
  PIN ra_read_sin_forwarded_result_out[44]
    DIRECTION OUTPUT ;
    USE SIGNAL ;
    PORT
      LAYER met3 ;
        RECT  2999.2 3164.91 3000 3165.21 ;
    END
  END ra_read_sin_forwarded_result_out[44]
  PIN ra_read_sin_forwarded_result_out[45]
    DIRECTION OUTPUT ;
    USE SIGNAL ;
    PORT
      LAYER met3 ;
        RECT  2999.2 2556.99 3000 2557.29 ;
    END
  END ra_read_sin_forwarded_result_out[45]
  PIN ra_read_sin_forwarded_result_out[46]
    DIRECTION OUTPUT ;
    USE SIGNAL ;
    PORT
      LAYER met3 ;
        RECT  2999.2 3058.83 3000 3059.13 ;
    END
  END ra_read_sin_forwarded_result_out[46]
  PIN ra_read_sin_forwarded_result_out[47]
    DIRECTION OUTPUT ;
    USE SIGNAL ;
    PORT
      LAYER met3 ;
        RECT  2999.2 2347.55 3000 2347.85 ;
    END
  END ra_read_sin_forwarded_result_out[47]
  PIN ra_read_sin_forwarded_result_out[48]
    DIRECTION OUTPUT ;
    USE SIGNAL ;
    PORT
      LAYER met3 ;
        RECT  2999.2 2015.71 3000 2016.01 ;
    END
  END ra_read_sin_forwarded_result_out[48]
  PIN ra_read_sin_forwarded_result_out[49]
    DIRECTION OUTPUT ;
    USE SIGNAL ;
    PORT
      LAYER met3 ;
        RECT  2999.2 2497.15 3000 2497.45 ;
    END
  END ra_read_sin_forwarded_result_out[49]
  PIN ra_read_sin_forwarded_result_out[4]
    DIRECTION OUTPUT ;
    USE SIGNAL ;
    PORT
      LAYER met3 ;
        RECT  2999.2 2716.11 3000 2716.41 ;
    END
  END ra_read_sin_forwarded_result_out[4]
  PIN ra_read_sin_forwarded_result_out[50]
    DIRECTION OUTPUT ;
    USE SIGNAL ;
    PORT
      LAYER met3 ;
        RECT  2999.2 2242.83 3000 2243.13 ;
    END
  END ra_read_sin_forwarded_result_out[50]
  PIN ra_read_sin_forwarded_result_out[51]
    DIRECTION OUTPUT ;
    USE SIGNAL ;
    PORT
      LAYER met3 ;
        RECT  2999.2 2799.07 3000 2799.37 ;
    END
  END ra_read_sin_forwarded_result_out[51]
  PIN ra_read_sin_forwarded_result_out[52]
    DIRECTION OUTPUT ;
    USE SIGNAL ;
    PORT
      LAYER met3 ;
        RECT  2999.2 2265.95 3000 2266.25 ;
    END
  END ra_read_sin_forwarded_result_out[52]
  PIN ra_read_sin_forwarded_result_out[53]
    DIRECTION OUTPUT ;
    USE SIGNAL ;
    PORT
      LAYER met3 ;
        RECT  2999.2 2862.99 3000 2863.29 ;
    END
  END ra_read_sin_forwarded_result_out[53]
  PIN ra_read_sin_forwarded_result_out[54]
    DIRECTION OUTPUT ;
    USE SIGNAL ;
    PORT
      LAYER met3 ;
        RECT  2999.2 2011.63 3000 2011.93 ;
    END
  END ra_read_sin_forwarded_result_out[54]
  PIN ra_read_sin_forwarded_result_out[55]
    DIRECTION OUTPUT ;
    USE SIGNAL ;
    PORT
      LAYER met3 ;
        RECT  2999.2 2926.91 3000 2927.21 ;
    END
  END ra_read_sin_forwarded_result_out[55]
  PIN ra_read_sin_forwarded_result_out[56]
    DIRECTION OUTPUT ;
    USE SIGNAL ;
    PORT
      LAYER met3 ;
        RECT  2999.2 2146.27 3000 2146.57 ;
    END
  END ra_read_sin_forwarded_result_out[56]
  PIN ra_read_sin_forwarded_result_out[57]
    DIRECTION OUTPUT ;
    USE SIGNAL ;
    PORT
      LAYER met3 ;
        RECT  2999.2 2656.27 3000 2656.57 ;
    END
  END ra_read_sin_forwarded_result_out[57]
  PIN ra_read_sin_forwarded_result_out[58]
    DIRECTION OUTPUT ;
    USE SIGNAL ;
    PORT
      LAYER met3 ;
        RECT  2999.2 3095.55 3000 3095.85 ;
    END
  END ra_read_sin_forwarded_result_out[58]
  PIN ra_read_sin_forwarded_result_out[59]
    DIRECTION OUTPUT ;
    USE SIGNAL ;
    PORT
      LAYER met3 ;
        RECT  2999.2 2388.35 3000 2388.65 ;
    END
  END ra_read_sin_forwarded_result_out[59]
  PIN ra_read_sin_forwarded_result_out[5]
    DIRECTION OUTPUT ;
    USE SIGNAL ;
    PORT
      LAYER met3 ;
        RECT  2999.2 2343.47 3000 2343.77 ;
    END
  END ra_read_sin_forwarded_result_out[5]
  PIN ra_read_sin_forwarded_result_out[60]
    DIRECTION OUTPUT ;
    USE SIGNAL ;
    PORT
      LAYER met3 ;
        RECT  2999.2 2157.15 3000 2157.45 ;
    END
  END ra_read_sin_forwarded_result_out[60]
  PIN ra_read_sin_forwarded_result_out[61]
    DIRECTION OUTPUT ;
    USE SIGNAL ;
    PORT
      LAYER met3 ;
        RECT  2999.2 2894.27 3000 2894.57 ;
    END
  END ra_read_sin_forwarded_result_out[61]
  PIN ra_read_sin_forwarded_result_out[62]
    DIRECTION OUTPUT ;
    USE SIGNAL ;
    PORT
      LAYER met3 ;
        RECT  2999.2 2531.15 3000 2531.45 ;
    END
  END ra_read_sin_forwarded_result_out[62]
  PIN ra_read_sin_forwarded_result_out[63]
    DIRECTION OUTPUT ;
    USE SIGNAL ;
    PORT
      LAYER met3 ;
        RECT  2999.2 2510.75 3000 2511.05 ;
    END
  END ra_read_sin_forwarded_result_out[63]
  PIN ra_read_sin_forwarded_result_out[64]
    DIRECTION OUTPUT ;
    USE SIGNAL ;
    PORT
      LAYER met3 ;
        RECT  2999.2 2490.35 3000 2490.65 ;
    END
  END ra_read_sin_forwarded_result_out[64]
  PIN ra_read_sin_forwarded_result_out[65]
    DIRECTION OUTPUT ;
    USE SIGNAL ;
    PORT
      LAYER met3 ;
        RECT  2999.2 3094.19 3000 3094.49 ;
    END
  END ra_read_sin_forwarded_result_out[65]
  PIN ra_read_sin_forwarded_result_out[66]
    DIRECTION OUTPUT ;
    USE SIGNAL ;
    PORT
      LAYER met3 ;
        RECT  2999.2 3060.19 3000 3060.49 ;
    END
  END ra_read_sin_forwarded_result_out[66]
  PIN ra_read_sin_forwarded_result_out[67]
    DIRECTION OUTPUT ;
    USE SIGNAL ;
    PORT
      LAYER met3 ;
        RECT  2999.2 2746.03 3000 2746.33 ;
    END
  END ra_read_sin_forwarded_result_out[67]
  PIN ra_read_sin_forwarded_result_out[68]
    DIRECTION OUTPUT ;
    USE SIGNAL ;
    PORT
      LAYER met3 ;
        RECT  2999.2 2555.63 3000 2555.93 ;
    END
  END ra_read_sin_forwarded_result_out[68]
  PIN ra_read_sin_forwarded_result_out[69]
    DIRECTION OUTPUT ;
    USE SIGNAL ;
    PORT
      LAYER met3 ;
        RECT  2999.2 3294.11 3000 3294.41 ;
    END
  END ra_read_sin_forwarded_result_out[69]
  PIN ra_read_sin_forwarded_result_out[6]
    DIRECTION OUTPUT ;
    USE SIGNAL ;
    PORT
      LAYER met3 ;
        RECT  2999.2 2240.11 3000 2240.41 ;
    END
  END ra_read_sin_forwarded_result_out[6]
  PIN ra_read_sin_forwarded_result_out[70]
    DIRECTION OUTPUT ;
    USE SIGNAL ;
    PORT
      LAYER met3 ;
        RECT  2999.2 2911.95 3000 2912.25 ;
    END
  END ra_read_sin_forwarded_result_out[70]
  PIN ra_read_sin_forwarded_result_out[71]
    DIRECTION OUTPUT ;
    USE SIGNAL ;
    PORT
      LAYER met3 ;
        RECT  2999.2 3279.15 3000 3279.45 ;
    END
  END ra_read_sin_forwarded_result_out[71]
  PIN ra_read_sin_forwarded_result_out[72]
    DIRECTION OUTPUT ;
    USE SIGNAL ;
    PORT
      LAYER met3 ;
        RECT  2999.2 2653.55 3000 2653.85 ;
    END
  END ra_read_sin_forwarded_result_out[72]
  PIN ra_read_sin_forwarded_result_out[73]
    DIRECTION OUTPUT ;
    USE SIGNAL ;
    PORT
      LAYER met3 ;
        RECT  2999.2 2495.79 3000 2496.09 ;
    END
  END ra_read_sin_forwarded_result_out[73]
  PIN ra_read_sin_forwarded_result_out[74]
    DIRECTION OUTPUT ;
    USE SIGNAL ;
    PORT
      LAYER met3 ;
        RECT  2999.2 2498.51 3000 2498.81 ;
    END
  END ra_read_sin_forwarded_result_out[74]
  PIN ra_read_sin_forwarded_result_out[75]
    DIRECTION OUTPUT ;
    USE SIGNAL ;
    PORT
      LAYER met3 ;
        RECT  2999.2 2389.71 3000 2390.01 ;
    END
  END ra_read_sin_forwarded_result_out[75]
  PIN ra_read_sin_forwarded_result_out[76]
    DIRECTION OUTPUT ;
    USE SIGNAL ;
    PORT
      LAYER met3 ;
        RECT  2999.2 2880.67 3000 2880.97 ;
    END
  END ra_read_sin_forwarded_result_out[76]
  PIN ra_read_sin_forwarded_result_out[77]
    DIRECTION OUTPUT ;
    USE SIGNAL ;
    PORT
      LAYER met3 ;
        RECT  2999.2 2208.83 3000 2209.13 ;
    END
  END ra_read_sin_forwarded_result_out[77]
  PIN ra_read_sin_forwarded_result_out[78]
    DIRECTION OUTPUT ;
    USE SIGNAL ;
    PORT
      LAYER met3 ;
        RECT  2999.2 3005.79 3000 3006.09 ;
    END
  END ra_read_sin_forwarded_result_out[78]
  PIN ra_read_sin_forwarded_result_out[79]
    DIRECTION OUTPUT ;
    USE SIGNAL ;
    PORT
      LAYER met3 ;
        RECT  2999.2 2879.31 3000 2879.61 ;
    END
  END ra_read_sin_forwarded_result_out[79]
  PIN ra_read_sin_forwarded_result_out[7]
    DIRECTION OUTPUT ;
    USE SIGNAL ;
    PORT
      LAYER met3 ;
        RECT  2999.2 2964.99 3000 2965.29 ;
    END
  END ra_read_sin_forwarded_result_out[7]
  PIN ra_read_sin_forwarded_result_out[80]
    DIRECTION OUTPUT ;
    USE SIGNAL ;
    PORT
      LAYER met3 ;
        RECT  2999.2 2986.75 3000 2987.05 ;
    END
  END ra_read_sin_forwarded_result_out[80]
  PIN ra_read_sin_forwarded_result_out[81]
    DIRECTION OUTPUT ;
    USE SIGNAL ;
    PORT
      LAYER met3 ;
        RECT  2999.2 2759.63 3000 2759.93 ;
    END
  END ra_read_sin_forwarded_result_out[81]
  PIN ra_read_sin_forwarded_result_out[82]
    DIRECTION OUTPUT ;
    USE SIGNAL ;
    PORT
      LAYER met3 ;
        RECT  2999.2 2184.35 3000 2184.65 ;
    END
  END ra_read_sin_forwarded_result_out[82]
  PIN ra_read_sin_forwarded_result_out[83]
    DIRECTION OUTPUT ;
    USE SIGNAL ;
    PORT
      LAYER met3 ;
        RECT  2999.2 3269.63 3000 3269.93 ;
    END
  END ra_read_sin_forwarded_result_out[83]
  PIN ra_read_sin_forwarded_result_out[84]
    DIRECTION OUTPUT ;
    USE SIGNAL ;
    PORT
      LAYER met3 ;
        RECT  2999.2 2546.11 3000 2546.41 ;
    END
  END ra_read_sin_forwarded_result_out[84]
  PIN ra_read_sin_forwarded_result_out[85]
    DIRECTION OUTPUT ;
    USE SIGNAL ;
    PORT
      LAYER met3 ;
        RECT  2999.2 2699.79 3000 2700.09 ;
    END
  END ra_read_sin_forwarded_result_out[85]
  PIN ra_read_sin_forwarded_result_out[86]
    DIRECTION OUTPUT ;
    USE SIGNAL ;
    PORT
      LAYER met3 ;
        RECT  2999.2 3065.63 3000 3065.93 ;
    END
  END ra_read_sin_forwarded_result_out[86]
  PIN ra_read_sin_forwarded_result_out[87]
    DIRECTION OUTPUT ;
    USE SIGNAL ;
    PORT
      LAYER met3 ;
        RECT  2999.2 2808.59 3000 2808.89 ;
    END
  END ra_read_sin_forwarded_result_out[87]
  PIN ra_read_sin_forwarded_result_out[88]
    DIRECTION OUTPUT ;
    USE SIGNAL ;
    PORT
      LAYER met3 ;
        RECT  2999.2 3265.55 3000 3265.85 ;
    END
  END ra_read_sin_forwarded_result_out[88]
  PIN ra_read_sin_forwarded_result_out[89]
    DIRECTION OUTPUT ;
    USE SIGNAL ;
    PORT
      LAYER met3 ;
        RECT  2999.2 3167.63 3000 3167.93 ;
    END
  END ra_read_sin_forwarded_result_out[89]
  PIN ra_read_sin_forwarded_result_out[8]
    DIRECTION OUTPUT ;
    USE SIGNAL ;
    PORT
      LAYER met3 ;
        RECT  2999.2 2267.31 3000 2267.61 ;
    END
  END ra_read_sin_forwarded_result_out[8]
  PIN ra_read_sin_forwarded_result_out[90]
    DIRECTION OUTPUT ;
    USE SIGNAL ;
    PORT
      LAYER met3 ;
        RECT  2999.2 2241.47 3000 2241.77 ;
    END
  END ra_read_sin_forwarded_result_out[90]
  PIN ra_read_sin_forwarded_result_out[91]
    DIRECTION OUTPUT ;
    USE SIGNAL ;
    PORT
      LAYER met3 ;
        RECT  2999.2 2578.75 3000 2579.05 ;
    END
  END ra_read_sin_forwarded_result_out[91]
  PIN ra_read_sin_forwarded_result_out[92]
    DIRECTION OUTPUT ;
    USE SIGNAL ;
    PORT
      LAYER met3 ;
        RECT  2999.2 2204.75 3000 2205.05 ;
    END
  END ra_read_sin_forwarded_result_out[92]
  PIN ra_read_sin_forwarded_result_out[93]
    DIRECTION OUTPUT ;
    USE SIGNAL ;
    PORT
      LAYER met3 ;
        RECT  2999.2 2075.55 3000 2075.85 ;
    END
  END ra_read_sin_forwarded_result_out[93]
  PIN ra_read_sin_forwarded_result_out[94]
    DIRECTION OUTPUT ;
    USE SIGNAL ;
    PORT
      LAYER met3 ;
        RECT  2999.2 2960.91 3000 2961.21 ;
    END
  END ra_read_sin_forwarded_result_out[94]
  PIN ra_read_sin_forwarded_result_out[95]
    DIRECTION OUTPUT ;
    USE SIGNAL ;
    PORT
      LAYER met3 ;
        RECT  2999.2 2820.83 3000 2821.13 ;
    END
  END ra_read_sin_forwarded_result_out[95]
  PIN ra_read_sin_forwarded_result_out[96]
    DIRECTION OUTPUT ;
    USE SIGNAL ;
    PORT
      LAYER met3 ;
        RECT  2999.2 2914.67 3000 2914.97 ;
    END
  END ra_read_sin_forwarded_result_out[96]
  PIN ra_read_sin_forwarded_result_out[97]
    DIRECTION OUTPUT ;
    USE SIGNAL ;
    PORT
      LAYER met3 ;
        RECT  2999.2 2017.07 3000 2017.37 ;
    END
  END ra_read_sin_forwarded_result_out[97]
  PIN ra_read_sin_forwarded_result_out[98]
    DIRECTION OUTPUT ;
    USE SIGNAL ;
    PORT
      LAYER met3 ;
        RECT  2999.2 2468.59 3000 2468.89 ;
    END
  END ra_read_sin_forwarded_result_out[98]
  PIN ra_read_sin_forwarded_result_out[99]
    DIRECTION OUTPUT ;
    USE SIGNAL ;
    PORT
      LAYER met3 ;
        RECT  2999.2 2589.63 3000 2589.93 ;
    END
  END ra_read_sin_forwarded_result_out[99]
  PIN ra_read_sin_forwarded_result_out[9]
    DIRECTION OUTPUT ;
    USE SIGNAL ;
    PORT
      LAYER met3 ;
        RECT  2999.2 2584.19 3000 2584.49 ;
    END
  END ra_read_sin_forwarded_result_out[9]
  PIN ra_read_sin_forwarded_valid_in
    DIRECTION INPUT ;
    USE SIGNAL ;
    PORT
      LAYER met3 ;
        RECT  2999.2 1814.43 3000 1814.73 ;
    END
  END ra_read_sin_forwarded_valid_in
  PIN ra_rotate_even_cos_val_in[0]
    DIRECTION INPUT ;
    USE SIGNAL ;
    PORT
      LAYER met2 ;
        RECT  1312.08 3499.515 1312.22 3500 ;
    END
  END ra_rotate_even_cos_val_in[0]
  PIN ra_rotate_even_cos_val_in[10]
    DIRECTION INPUT ;
    USE SIGNAL ;
    PORT
      LAYER met3 ;
        RECT  0 1925.95 0.8 1926.25 ;
    END
  END ra_rotate_even_cos_val_in[10]
  PIN ra_rotate_even_cos_val_in[11]
    DIRECTION INPUT ;
    USE SIGNAL ;
    PORT
      LAYER met3 ;
        RECT  0 1942.27 0.8 1942.57 ;
    END
  END ra_rotate_even_cos_val_in[11]
  PIN ra_rotate_even_cos_val_in[12]
    DIRECTION INPUT ;
    USE SIGNAL ;
    PORT
      LAYER met3 ;
        RECT  0 1946.35 0.8 1946.65 ;
    END
  END ra_rotate_even_cos_val_in[12]
  PIN ra_rotate_even_cos_val_in[13]
    DIRECTION INPUT ;
    USE SIGNAL ;
    PORT
      LAYER met3 ;
        RECT  0 1959.95 0.8 1960.25 ;
    END
  END ra_rotate_even_cos_val_in[13]
  PIN ra_rotate_even_cos_val_in[14]
    DIRECTION INPUT ;
    USE SIGNAL ;
    PORT
      LAYER met3 ;
        RECT  0 1968.11 0.8 1968.41 ;
    END
  END ra_rotate_even_cos_val_in[14]
  PIN ra_rotate_even_cos_val_in[15]
    DIRECTION INPUT ;
    USE SIGNAL ;
    PORT
      LAYER met3 ;
        RECT  0 2041.55 0.8 2041.85 ;
    END
  END ra_rotate_even_cos_val_in[15]
  PIN ra_rotate_even_cos_val_in[1]
    DIRECTION INPUT ;
    USE SIGNAL ;
    PORT
      LAYER met2 ;
        RECT  1313.92 3499.515 1314.06 3500 ;
    END
  END ra_rotate_even_cos_val_in[1]
  PIN ra_rotate_even_cos_val_in[2]
    DIRECTION INPUT ;
    USE SIGNAL ;
    PORT
      LAYER met2 ;
        RECT  1257.8 3499.515 1257.94 3500 ;
    END
  END ra_rotate_even_cos_val_in[2]
  PIN ra_rotate_even_cos_val_in[3]
    DIRECTION INPUT ;
    USE SIGNAL ;
    PORT
      LAYER met2 ;
        RECT  1324.04 3499.515 1324.18 3500 ;
    END
  END ra_rotate_even_cos_val_in[3]
  PIN ra_rotate_even_cos_val_in[4]
    DIRECTION INPUT ;
    USE SIGNAL ;
    PORT
      LAYER met2 ;
        RECT  1347.96 3499.515 1348.1 3500 ;
    END
  END ra_rotate_even_cos_val_in[4]
  PIN ra_rotate_even_cos_val_in[5]
    DIRECTION INPUT ;
    USE SIGNAL ;
    PORT
      LAYER met2 ;
        RECT  1351.64 3499.515 1351.78 3500 ;
    END
  END ra_rotate_even_cos_val_in[5]
  PIN ra_rotate_even_cos_val_in[6]
    DIRECTION INPUT ;
    USE SIGNAL ;
    PORT
      LAYER met2 ;
        RECT  1280.8 3499.515 1280.94 3500 ;
    END
  END ra_rotate_even_cos_val_in[6]
  PIN ra_rotate_even_cos_val_in[7]
    DIRECTION INPUT ;
    USE SIGNAL ;
    PORT
      LAYER met3 ;
        RECT  0 1920.51 0.8 1920.81 ;
    END
  END ra_rotate_even_cos_val_in[7]
  PIN ra_rotate_even_cos_val_in[8]
    DIRECTION INPUT ;
    USE SIGNAL ;
    PORT
      LAYER met3 ;
        RECT  0 1923.23 0.8 1923.53 ;
    END
  END ra_rotate_even_cos_val_in[8]
  PIN ra_rotate_even_cos_val_in[9]
    DIRECTION INPUT ;
    USE SIGNAL ;
    PORT
      LAYER met3 ;
        RECT  0 1913.71 0.8 1914.01 ;
    END
  END ra_rotate_even_cos_val_in[9]
  PIN ra_rotate_even_empty_out
    DIRECTION OUTPUT ;
    USE SIGNAL ;
    PORT
      LAYER met3 ;
        RECT  2999.2 1860.67 3000 1860.97 ;
    END
  END ra_rotate_even_empty_out
  PIN ra_rotate_even_rden_in
    DIRECTION INPUT ;
    USE SIGNAL ;
    PORT
      LAYER met3 ;
        RECT  2999.2 1857.95 3000 1858.25 ;
    END
  END ra_rotate_even_rden_in
  PIN ra_rotate_even_rdy_out
    DIRECTION OUTPUT ;
    USE SIGNAL ;
    PORT
      LAYER met3 ;
        RECT  2999.2 1833.47 3000 1833.77 ;
    END
  END ra_rotate_even_rdy_out
  PIN ra_rotate_even_result_out[0]
    DIRECTION OUTPUT ;
    USE SIGNAL ;
    PORT
      LAYER met3 ;
        RECT  2999.2 1889.23 3000 1889.53 ;
    END
  END ra_rotate_even_result_out[0]
  PIN ra_rotate_even_result_out[10]
    DIRECTION OUTPUT ;
    USE SIGNAL ;
    PORT
      LAYER met3 ;
        RECT  2999.2 2026.59 3000 2026.89 ;
    END
  END ra_rotate_even_result_out[10]
  PIN ra_rotate_even_result_out[11]
    DIRECTION OUTPUT ;
    USE SIGNAL ;
    PORT
      LAYER met3 ;
        RECT  2999.2 1856.59 3000 1856.89 ;
    END
  END ra_rotate_even_result_out[11]
  PIN ra_rotate_even_result_out[12]
    DIRECTION OUTPUT ;
    USE SIGNAL ;
    PORT
      LAYER met3 ;
        RECT  2999.2 1970.83 3000 1971.13 ;
    END
  END ra_rotate_even_result_out[12]
  PIN ra_rotate_even_result_out[13]
    DIRECTION OUTPUT ;
    USE SIGNAL ;
    PORT
      LAYER met3 ;
        RECT  2999.2 1913.71 3000 1914.01 ;
    END
  END ra_rotate_even_result_out[13]
  PIN ra_rotate_even_result_out[14]
    DIRECTION OUTPUT ;
    USE SIGNAL ;
    PORT
      LAYER met3 ;
        RECT  2999.2 2029.31 3000 2029.61 ;
    END
  END ra_rotate_even_result_out[14]
  PIN ra_rotate_even_result_out[15]
    DIRECTION OUTPUT ;
    USE SIGNAL ;
    PORT
      LAYER met3 ;
        RECT  2999.2 1940.91 3000 1941.21 ;
    END
  END ra_rotate_even_result_out[15]
  PIN ra_rotate_even_result_out[1]
    DIRECTION OUTPUT ;
    USE SIGNAL ;
    PORT
      LAYER met3 ;
        RECT  2999.2 1927.31 3000 1927.61 ;
    END
  END ra_rotate_even_result_out[1]
  PIN ra_rotate_even_result_out[2]
    DIRECTION OUTPUT ;
    USE SIGNAL ;
    PORT
      LAYER met3 ;
        RECT  2999.2 1849.79 3000 1850.09 ;
    END
  END ra_rotate_even_result_out[2]
  PIN ra_rotate_even_result_out[3]
    DIRECTION OUTPUT ;
    USE SIGNAL ;
    PORT
      LAYER met3 ;
        RECT  2999.2 1817.15 3000 1817.45 ;
    END
  END ra_rotate_even_result_out[3]
  PIN ra_rotate_even_result_out[4]
    DIRECTION OUTPUT ;
    USE SIGNAL ;
    PORT
      LAYER met3 ;
        RECT  2999.2 1887.87 3000 1888.17 ;
    END
  END ra_rotate_even_result_out[4]
  PIN ra_rotate_even_result_out[5]
    DIRECTION OUTPUT ;
    USE SIGNAL ;
    PORT
      LAYER met3 ;
        RECT  2999.2 1806.27 3000 1806.57 ;
    END
  END ra_rotate_even_result_out[5]
  PIN ra_rotate_even_result_out[6]
    DIRECTION OUTPUT ;
    USE SIGNAL ;
    PORT
      LAYER met3 ;
        RECT  2999.2 1807.63 3000 1807.93 ;
    END
  END ra_rotate_even_result_out[6]
  PIN ra_rotate_even_result_out[7]
    DIRECTION OUTPUT ;
    USE SIGNAL ;
    PORT
      LAYER met3 ;
        RECT  2999.2 1968.11 3000 1968.41 ;
    END
  END ra_rotate_even_result_out[7]
  PIN ra_rotate_even_result_out[8]
    DIRECTION OUTPUT ;
    USE SIGNAL ;
    PORT
      LAYER met3 ;
        RECT  2999.2 2027.95 3000 2028.25 ;
    END
  END ra_rotate_even_result_out[8]
  PIN ra_rotate_even_result_out[9]
    DIRECTION OUTPUT ;
    USE SIGNAL ;
    PORT
      LAYER met3 ;
        RECT  2999.2 2022.51 3000 2022.81 ;
    END
  END ra_rotate_even_result_out[9]
  PIN ra_rotate_even_sin_val_in[0]
    DIRECTION INPUT ;
    USE SIGNAL ;
    PORT
      LAYER met3 ;
        RECT  0 2091.87 0.8 2092.17 ;
    END
  END ra_rotate_even_sin_val_in[0]
  PIN ra_rotate_even_sin_val_in[10]
    DIRECTION INPUT ;
    USE SIGNAL ;
    PORT
      LAYER met3 ;
        RECT  0 1876.99 0.8 1877.29 ;
    END
  END ra_rotate_even_sin_val_in[10]
  PIN ra_rotate_even_sin_val_in[11]
    DIRECTION INPUT ;
    USE SIGNAL ;
    PORT
      LAYER met3 ;
        RECT  0 1890.59 0.8 1890.89 ;
    END
  END ra_rotate_even_sin_val_in[11]
  PIN ra_rotate_even_sin_val_in[12]
    DIRECTION INPUT ;
    USE SIGNAL ;
    PORT
      LAYER met3 ;
        RECT  0 1898.75 0.8 1899.05 ;
    END
  END ra_rotate_even_sin_val_in[12]
  PIN ra_rotate_even_sin_val_in[13]
    DIRECTION INPUT ;
    USE SIGNAL ;
    PORT
      LAYER met3 ;
        RECT  0 1905.55 0.8 1905.85 ;
    END
  END ra_rotate_even_sin_val_in[13]
  PIN ra_rotate_even_sin_val_in[14]
    DIRECTION INPUT ;
    USE SIGNAL ;
    PORT
      LAYER met3 ;
        RECT  0 1916.43 0.8 1916.73 ;
    END
  END ra_rotate_even_sin_val_in[14]
  PIN ra_rotate_even_sin_val_in[15]
    DIRECTION INPUT ;
    USE SIGNAL ;
    PORT
      LAYER met3 ;
        RECT  0 1958.59 0.8 1958.89 ;
    END
  END ra_rotate_even_sin_val_in[15]
  PIN ra_rotate_even_sin_val_in[1]
    DIRECTION INPUT ;
    USE SIGNAL ;
    PORT
      LAYER met3 ;
        RECT  0 2090.51 0.8 2090.81 ;
    END
  END ra_rotate_even_sin_val_in[1]
  PIN ra_rotate_even_sin_val_in[2]
    DIRECTION INPUT ;
    USE SIGNAL ;
    PORT
      LAYER met3 ;
        RECT  0 2102.75 0.8 2103.05 ;
    END
  END ra_rotate_even_sin_val_in[2]
  PIN ra_rotate_even_sin_val_in[3]
    DIRECTION INPUT ;
    USE SIGNAL ;
    PORT
      LAYER met3 ;
        RECT  0 2105.47 0.8 2105.77 ;
    END
  END ra_rotate_even_sin_val_in[3]
  PIN ra_rotate_even_sin_val_in[4]
    DIRECTION INPUT ;
    USE SIGNAL ;
    PORT
      LAYER met2 ;
        RECT  1308.4 3499.515 1308.54 3500 ;
    END
  END ra_rotate_even_sin_val_in[4]
  PIN ra_rotate_even_sin_val_in[5]
    DIRECTION INPUT ;
    USE SIGNAL ;
    PORT
      LAYER met3 ;
        RECT  0 2119.07 0.8 2119.37 ;
    END
  END ra_rotate_even_sin_val_in[5]
  PIN ra_rotate_even_sin_val_in[6]
    DIRECTION INPUT ;
    USE SIGNAL ;
    PORT
      LAYER met3 ;
        RECT  0 2121.79 0.8 2122.09 ;
    END
  END ra_rotate_even_sin_val_in[6]
  PIN ra_rotate_even_sin_val_in[7]
    DIRECTION INPUT ;
    USE SIGNAL ;
    PORT
      LAYER met3 ;
        RECT  0 1872.91 0.8 1873.21 ;
    END
  END ra_rotate_even_sin_val_in[7]
  PIN ra_rotate_even_sin_val_in[8]
    DIRECTION INPUT ;
    USE SIGNAL ;
    PORT
      LAYER met3 ;
        RECT  0 1859.31 0.8 1859.61 ;
    END
  END ra_rotate_even_sin_val_in[8]
  PIN ra_rotate_even_sin_val_in[9]
    DIRECTION INPUT ;
    USE SIGNAL ;
    PORT
      LAYER met3 ;
        RECT  0 1867.47 0.8 1867.77 ;
    END
  END ra_rotate_even_sin_val_in[9]
  PIN ra_rotate_even_valid_in
    DIRECTION INPUT ;
    USE SIGNAL ;
    PORT
      LAYER met3 ;
        RECT  2999.2 1832.11 3000 1832.41 ;
    END
  END ra_rotate_even_valid_in
  PIN ra_rotate_even_x_even_in[0]
    DIRECTION INPUT ;
    USE SIGNAL ;
    PORT
      LAYER met2 ;
        RECT  1265.16 3499.515 1265.3 3500 ;
    END
  END ra_rotate_even_x_even_in[0]
  PIN ra_rotate_even_x_even_in[10]
    DIRECTION INPUT ;
    USE SIGNAL ;
    PORT
      LAYER met3 ;
        RECT  0 1924.59 0.8 1924.89 ;
    END
  END ra_rotate_even_x_even_in[10]
  PIN ra_rotate_even_x_even_in[11]
    DIRECTION INPUT ;
    USE SIGNAL ;
    PORT
      LAYER met3 ;
        RECT  0 1940.91 0.8 1941.21 ;
    END
  END ra_rotate_even_x_even_in[11]
  PIN ra_rotate_even_x_even_in[12]
    DIRECTION INPUT ;
    USE SIGNAL ;
    PORT
      LAYER met3 ;
        RECT  0 1943.63 0.8 1943.93 ;
    END
  END ra_rotate_even_x_even_in[12]
  PIN ra_rotate_even_x_even_in[13]
    DIRECTION INPUT ;
    USE SIGNAL ;
    PORT
      LAYER met3 ;
        RECT  0 1955.87 0.8 1956.17 ;
    END
  END ra_rotate_even_x_even_in[13]
  PIN ra_rotate_even_x_even_in[14]
    DIRECTION INPUT ;
    USE SIGNAL ;
    PORT
      LAYER met3 ;
        RECT  0 1966.75 0.8 1967.05 ;
    END
  END ra_rotate_even_x_even_in[14]
  PIN ra_rotate_even_x_even_in[15]
    DIRECTION INPUT ;
    USE SIGNAL ;
    PORT
      LAYER met3 ;
        RECT  0 2040.19 0.8 2040.49 ;
    END
  END ra_rotate_even_x_even_in[15]
  PIN ra_rotate_even_x_even_in[1]
    DIRECTION INPUT ;
    USE SIGNAL ;
    PORT
      LAYER met2 ;
        RECT  1264.24 3499.515 1264.38 3500 ;
    END
  END ra_rotate_even_x_even_in[1]
  PIN ra_rotate_even_x_even_in[2]
    DIRECTION INPUT ;
    USE SIGNAL ;
    PORT
      LAYER met2 ;
        RECT  1260.56 3499.515 1260.7 3500 ;
    END
  END ra_rotate_even_x_even_in[2]
  PIN ra_rotate_even_x_even_in[3]
    DIRECTION INPUT ;
    USE SIGNAL ;
    PORT
      LAYER met2 ;
        RECT  1270.68 3499.515 1270.82 3500 ;
    END
  END ra_rotate_even_x_even_in[3]
  PIN ra_rotate_even_x_even_in[4]
    DIRECTION INPUT ;
    USE SIGNAL ;
    PORT
      LAYER met2 ;
        RECT  1294.6 3499.515 1294.74 3500 ;
    END
  END ra_rotate_even_x_even_in[4]
  PIN ra_rotate_even_x_even_in[5]
    DIRECTION INPUT ;
    USE SIGNAL ;
    PORT
      LAYER met2 ;
        RECT  1323.12 3499.515 1323.26 3500 ;
    END
  END ra_rotate_even_x_even_in[5]
  PIN ra_rotate_even_x_even_in[6]
    DIRECTION INPUT ;
    USE SIGNAL ;
    PORT
      LAYER met2 ;
        RECT  1332.32 3499.515 1332.46 3500 ;
    END
  END ra_rotate_even_x_even_in[6]
  PIN ra_rotate_even_x_even_in[7]
    DIRECTION INPUT ;
    USE SIGNAL ;
    PORT
      LAYER met3 ;
        RECT  0 1919.15 0.8 1919.45 ;
    END
  END ra_rotate_even_x_even_in[7]
  PIN ra_rotate_even_x_even_in[8]
    DIRECTION INPUT ;
    USE SIGNAL ;
    PORT
      LAYER met3 ;
        RECT  0 1921.87 0.8 1922.17 ;
    END
  END ra_rotate_even_x_even_in[8]
  PIN ra_rotate_even_x_even_in[9]
    DIRECTION INPUT ;
    USE SIGNAL ;
    PORT
      LAYER met3 ;
        RECT  0 1915.07 0.8 1915.37 ;
    END
  END ra_rotate_even_x_even_in[9]
  PIN ra_rotate_even_x_odd_in[0]
    DIRECTION INPUT ;
    USE SIGNAL ;
    PORT
      LAYER met3 ;
        RECT  0 2025.23 0.8 2025.53 ;
    END
  END ra_rotate_even_x_odd_in[0]
  PIN ra_rotate_even_x_odd_in[10]
    DIRECTION INPUT ;
    USE SIGNAL ;
    PORT
      LAYER met3 ;
        RECT  0 1875.63 0.8 1875.93 ;
    END
  END ra_rotate_even_x_odd_in[10]
  PIN ra_rotate_even_x_odd_in[11]
    DIRECTION INPUT ;
    USE SIGNAL ;
    PORT
      LAYER met3 ;
        RECT  0 1889.23 0.8 1889.53 ;
    END
  END ra_rotate_even_x_odd_in[11]
  PIN ra_rotate_even_x_odd_in[12]
    DIRECTION INPUT ;
    USE SIGNAL ;
    PORT
      LAYER met3 ;
        RECT  0 1896.03 0.8 1896.33 ;
    END
  END ra_rotate_even_x_odd_in[12]
  PIN ra_rotate_even_x_odd_in[13]
    DIRECTION INPUT ;
    USE SIGNAL ;
    PORT
      LAYER met3 ;
        RECT  0 1901.47 0.8 1901.77 ;
    END
  END ra_rotate_even_x_odd_in[13]
  PIN ra_rotate_even_x_odd_in[14]
    DIRECTION INPUT ;
    USE SIGNAL ;
    PORT
      LAYER met3 ;
        RECT  0 1917.79 0.8 1918.09 ;
    END
  END ra_rotate_even_x_odd_in[14]
  PIN ra_rotate_even_x_odd_in[15]
    DIRECTION INPUT ;
    USE SIGNAL ;
    PORT
      LAYER met3 ;
        RECT  0 1957.23 0.8 1957.53 ;
    END
  END ra_rotate_even_x_odd_in[15]
  PIN ra_rotate_even_x_odd_in[1]
    DIRECTION INPUT ;
    USE SIGNAL ;
    PORT
      LAYER met3 ;
        RECT  0 2022.51 0.8 2022.81 ;
    END
  END ra_rotate_even_x_odd_in[1]
  PIN ra_rotate_even_x_odd_in[2]
    DIRECTION INPUT ;
    USE SIGNAL ;
    PORT
      LAYER met3 ;
        RECT  0 2037.47 0.8 2037.77 ;
    END
  END ra_rotate_even_x_odd_in[2]
  PIN ra_rotate_even_x_odd_in[3]
    DIRECTION INPUT ;
    USE SIGNAL ;
    PORT
      LAYER met3 ;
        RECT  0 2059.23 0.8 2059.53 ;
    END
  END ra_rotate_even_x_odd_in[3]
  PIN ra_rotate_even_x_odd_in[4]
    DIRECTION INPUT ;
    USE SIGNAL ;
    PORT
      LAYER met3 ;
        RECT  0 2066.03 0.8 2066.33 ;
    END
  END ra_rotate_even_x_odd_in[4]
  PIN ra_rotate_even_x_odd_in[5]
    DIRECTION INPUT ;
    USE SIGNAL ;
    PORT
      LAYER met3 ;
        RECT  0 2104.11 0.8 2104.41 ;
    END
  END ra_rotate_even_x_odd_in[5]
  PIN ra_rotate_even_x_odd_in[6]
    DIRECTION INPUT ;
    USE SIGNAL ;
    PORT
      LAYER met3 ;
        RECT  0 2110.91 0.8 2111.21 ;
    END
  END ra_rotate_even_x_odd_in[6]
  PIN ra_rotate_even_x_odd_in[7]
    DIRECTION INPUT ;
    USE SIGNAL ;
    PORT
      LAYER met3 ;
        RECT  0 1871.55 0.8 1871.85 ;
    END
  END ra_rotate_even_x_odd_in[7]
  PIN ra_rotate_even_x_odd_in[8]
    DIRECTION INPUT ;
    USE SIGNAL ;
    PORT
      LAYER met3 ;
        RECT  0 1860.67 0.8 1860.97 ;
    END
  END ra_rotate_even_x_odd_in[8]
  PIN ra_rotate_even_x_odd_in[9]
    DIRECTION INPUT ;
    USE SIGNAL ;
    PORT
      LAYER met3 ;
        RECT  0 1864.75 0.8 1865.05 ;
    END
  END ra_rotate_even_x_odd_in[9]
  PIN ra_rotate_odd_cos_val_in[0]
    DIRECTION INPUT ;
    USE SIGNAL ;
    PORT
      LAYER met3 ;
        RECT  0 1573.71 0.8 1574.01 ;
    END
  END ra_rotate_odd_cos_val_in[0]
  PIN ra_rotate_odd_cos_val_in[10]
    DIRECTION INPUT ;
    USE SIGNAL ;
    PORT
      LAYER met3 ;
        RECT  0 1524.75 0.8 1525.05 ;
    END
  END ra_rotate_odd_cos_val_in[10]
  PIN ra_rotate_odd_cos_val_in[11]
    DIRECTION INPUT ;
    USE SIGNAL ;
    PORT
      LAYER met3 ;
        RECT  0 1501.63 0.8 1501.93 ;
    END
  END ra_rotate_odd_cos_val_in[11]
  PIN ra_rotate_odd_cos_val_in[12]
    DIRECTION INPUT ;
    USE SIGNAL ;
    PORT
      LAYER met3 ;
        RECT  0 1500.27 0.8 1500.57 ;
    END
  END ra_rotate_odd_cos_val_in[12]
  PIN ra_rotate_odd_cos_val_in[13]
    DIRECTION INPUT ;
    USE SIGNAL ;
    PORT
      LAYER met3 ;
        RECT  0 1492.11 0.8 1492.41 ;
    END
  END ra_rotate_odd_cos_val_in[13]
  PIN ra_rotate_odd_cos_val_in[14]
    DIRECTION INPUT ;
    USE SIGNAL ;
    PORT
      LAYER met3 ;
        RECT  0 1481.23 0.8 1481.53 ;
    END
  END ra_rotate_odd_cos_val_in[14]
  PIN ra_rotate_odd_cos_val_in[15]
    DIRECTION INPUT ;
    USE SIGNAL ;
    PORT
      LAYER met3 ;
        RECT  0 1687.95 0.8 1688.25 ;
    END
  END ra_rotate_odd_cos_val_in[15]
  PIN ra_rotate_odd_cos_val_in[1]
    DIRECTION INPUT ;
    USE SIGNAL ;
    PORT
      LAYER met3 ;
        RECT  0 1562.83 0.8 1563.13 ;
    END
  END ra_rotate_odd_cos_val_in[1]
  PIN ra_rotate_odd_cos_val_in[2]
    DIRECTION INPUT ;
    USE SIGNAL ;
    PORT
      LAYER met3 ;
        RECT  0 1652.59 0.8 1652.89 ;
    END
  END ra_rotate_odd_cos_val_in[2]
  PIN ra_rotate_odd_cos_val_in[3]
    DIRECTION INPUT ;
    USE SIGNAL ;
    PORT
      LAYER met3 ;
        RECT  0 1560.11 0.8 1560.41 ;
    END
  END ra_rotate_odd_cos_val_in[3]
  PIN ra_rotate_odd_cos_val_in[4]
    DIRECTION INPUT ;
    USE SIGNAL ;
    PORT
      LAYER met3 ;
        RECT  0 1566.91 0.8 1567.21 ;
    END
  END ra_rotate_odd_cos_val_in[4]
  PIN ra_rotate_odd_cos_val_in[5]
    DIRECTION INPUT ;
    USE SIGNAL ;
    PORT
      LAYER met3 ;
        RECT  0 1681.15 0.8 1681.45 ;
    END
  END ra_rotate_odd_cos_val_in[5]
  PIN ra_rotate_odd_cos_val_in[6]
    DIRECTION INPUT ;
    USE SIGNAL ;
    PORT
      LAYER met3 ;
        RECT  0 1682.51 0.8 1682.81 ;
    END
  END ra_rotate_odd_cos_val_in[6]
  PIN ra_rotate_odd_cos_val_in[7]
    DIRECTION INPUT ;
    USE SIGNAL ;
    PORT
      LAYER met3 ;
        RECT  0 1531.55 0.8 1531.85 ;
    END
  END ra_rotate_odd_cos_val_in[7]
  PIN ra_rotate_odd_cos_val_in[8]
    DIRECTION INPUT ;
    USE SIGNAL ;
    PORT
      LAYER met3 ;
        RECT  0 1541.07 0.8 1541.37 ;
    END
  END ra_rotate_odd_cos_val_in[8]
  PIN ra_rotate_odd_cos_val_in[9]
    DIRECTION INPUT ;
    USE SIGNAL ;
    PORT
      LAYER met3 ;
        RECT  0 1523.39 0.8 1523.69 ;
    END
  END ra_rotate_odd_cos_val_in[9]
  PIN ra_rotate_odd_empty_out
    DIRECTION OUTPUT ;
    USE SIGNAL ;
    PORT
      LAYER met3 ;
        RECT  2999.2 1500.27 3000 1500.57 ;
    END
  END ra_rotate_odd_empty_out
  PIN ra_rotate_odd_rden_in
    DIRECTION INPUT ;
    USE SIGNAL ;
    PORT
      LAYER met3 ;
        RECT  2999.2 1414.59 3000 1414.89 ;
    END
  END ra_rotate_odd_rden_in
  PIN ra_rotate_odd_rdy_out
    DIRECTION OUTPUT ;
    USE SIGNAL ;
    PORT
      LAYER met3 ;
        RECT  2999.2 1517.95 3000 1518.25 ;
    END
  END ra_rotate_odd_rdy_out
  PIN ra_rotate_odd_result_out[0]
    DIRECTION OUTPUT ;
    USE SIGNAL ;
    PORT
      LAYER met2 ;
        RECT  1397.64 0 1397.78 0.485 ;
    END
  END ra_rotate_odd_result_out[0]
  PIN ra_rotate_odd_result_out[10]
    DIRECTION OUTPUT ;
    USE SIGNAL ;
    PORT
      LAYER met2 ;
        RECT  1554.04 0 1554.18 0.485 ;
    END
  END ra_rotate_odd_result_out[10]
  PIN ra_rotate_odd_result_out[11]
    DIRECTION OUTPUT ;
    USE SIGNAL ;
    PORT
      LAYER met2 ;
        RECT  1516.32 0 1516.46 0.485 ;
    END
  END ra_rotate_odd_result_out[11]
  PIN ra_rotate_odd_result_out[12]
    DIRECTION OUTPUT ;
    USE SIGNAL ;
    PORT
      LAYER met2 ;
        RECT  1558.64 0 1558.78 0.485 ;
    END
  END ra_rotate_odd_result_out[12]
  PIN ra_rotate_odd_result_out[13]
    DIRECTION OUTPUT ;
    USE SIGNAL ;
    PORT
      LAYER met2 ;
        RECT  1556.8 0 1556.94 0.485 ;
    END
  END ra_rotate_odd_result_out[13]
  PIN ra_rotate_odd_result_out[14]
    DIRECTION OUTPUT ;
    USE SIGNAL ;
    PORT
      LAYER met2 ;
        RECT  1553.12 0 1553.26 0.485 ;
    END
  END ra_rotate_odd_result_out[14]
  PIN ra_rotate_odd_result_out[15]
    DIRECTION OUTPUT ;
    USE SIGNAL ;
    PORT
      LAYER met2 ;
        RECT  1451 0 1451.14 0.485 ;
    END
  END ra_rotate_odd_result_out[15]
  PIN ra_rotate_odd_result_out[1]
    DIRECTION OUTPUT ;
    USE SIGNAL ;
    PORT
      LAYER met2 ;
        RECT  1392.12 0 1392.26 0.485 ;
    END
  END ra_rotate_odd_result_out[1]
  PIN ra_rotate_odd_result_out[2]
    DIRECTION OUTPUT ;
    USE SIGNAL ;
    PORT
      LAYER met2 ;
        RECT  1393.04 0 1393.18 0.485 ;
    END
  END ra_rotate_odd_result_out[2]
  PIN ra_rotate_odd_result_out[3]
    DIRECTION OUTPUT ;
    USE SIGNAL ;
    PORT
      LAYER met2 ;
        RECT  1438.12 0 1438.26 0.485 ;
    END
  END ra_rotate_odd_result_out[3]
  PIN ra_rotate_odd_result_out[4]
    DIRECTION OUTPUT ;
    USE SIGNAL ;
    PORT
      LAYER met2 ;
        RECT  1394.88 0 1395.02 0.485 ;
    END
  END ra_rotate_odd_result_out[4]
  PIN ra_rotate_odd_result_out[5]
    DIRECTION OUTPUT ;
    USE SIGNAL ;
    PORT
      LAYER met2 ;
        RECT  1468.48 0 1468.62 0.485 ;
    END
  END ra_rotate_odd_result_out[5]
  PIN ra_rotate_odd_result_out[6]
    DIRECTION OUTPUT ;
    USE SIGNAL ;
    PORT
      LAYER met2 ;
        RECT  1393.96 0 1394.1 0.485 ;
    END
  END ra_rotate_odd_result_out[6]
  PIN ra_rotate_odd_result_out[7]
    DIRECTION OUTPUT ;
    USE SIGNAL ;
    PORT
      LAYER met2 ;
        RECT  1506.2 0 1506.34 0.485 ;
    END
  END ra_rotate_odd_result_out[7]
  PIN ra_rotate_odd_result_out[8]
    DIRECTION OUTPUT ;
    USE SIGNAL ;
    PORT
      LAYER met2 ;
        RECT  1467.56 0 1467.7 0.485 ;
    END
  END ra_rotate_odd_result_out[8]
  PIN ra_rotate_odd_result_out[9]
    DIRECTION OUTPUT ;
    USE SIGNAL ;
    PORT
      LAYER met2 ;
        RECT  1488.72 0 1488.86 0.485 ;
    END
  END ra_rotate_odd_result_out[9]
  PIN ra_rotate_odd_sin_val_in[0]
    DIRECTION INPUT ;
    USE SIGNAL ;
    PORT
      LAYER met3 ;
        RECT  0 1776.35 0.8 1776.65 ;
    END
  END ra_rotate_odd_sin_val_in[0]
  PIN ra_rotate_odd_sin_val_in[10]
    DIRECTION INPUT ;
    USE SIGNAL ;
    PORT
      LAYER met3 ;
        RECT  0 1622.67 0.8 1622.97 ;
    END
  END ra_rotate_odd_sin_val_in[10]
  PIN ra_rotate_odd_sin_val_in[11]
    DIRECTION INPUT ;
    USE SIGNAL ;
    PORT
      LAYER met3 ;
        RECT  0 1603.63 0.8 1603.93 ;
    END
  END ra_rotate_odd_sin_val_in[11]
  PIN ra_rotate_odd_sin_val_in[12]
    DIRECTION INPUT ;
    USE SIGNAL ;
    PORT
      LAYER met3 ;
        RECT  0 1600.91 0.8 1601.21 ;
    END
  END ra_rotate_odd_sin_val_in[12]
  PIN ra_rotate_odd_sin_val_in[13]
    DIRECTION INPUT ;
    USE SIGNAL ;
    PORT
      LAYER met3 ;
        RECT  0 1592.75 0.8 1593.05 ;
    END
  END ra_rotate_odd_sin_val_in[13]
  PIN ra_rotate_odd_sin_val_in[14]
    DIRECTION INPUT ;
    USE SIGNAL ;
    PORT
      LAYER met3 ;
        RECT  0 1576.43 0.8 1576.73 ;
    END
  END ra_rotate_odd_sin_val_in[14]
  PIN ra_rotate_odd_sin_val_in[15]
    DIRECTION INPUT ;
    USE SIGNAL ;
    PORT
      LAYER met3 ;
        RECT  0 1538.35 0.8 1538.65 ;
    END
  END ra_rotate_odd_sin_val_in[15]
  PIN ra_rotate_odd_sin_val_in[1]
    DIRECTION INPUT ;
    USE SIGNAL ;
    PORT
      LAYER met3 ;
        RECT  0 1777.71 0.8 1778.01 ;
    END
  END ra_rotate_odd_sin_val_in[1]
  PIN ra_rotate_odd_sin_val_in[2]
    DIRECTION INPUT ;
    USE SIGNAL ;
    PORT
      LAYER met3 ;
        RECT  0 1779.07 0.8 1779.37 ;
    END
  END ra_rotate_odd_sin_val_in[2]
  PIN ra_rotate_odd_sin_val_in[3]
    DIRECTION INPUT ;
    USE SIGNAL ;
    PORT
      LAYER met3 ;
        RECT  0 1696.11 0.8 1696.41 ;
    END
  END ra_rotate_odd_sin_val_in[3]
  PIN ra_rotate_odd_sin_val_in[4]
    DIRECTION INPUT ;
    USE SIGNAL ;
    PORT
      LAYER met3 ;
        RECT  0 1798.11 0.8 1798.41 ;
    END
  END ra_rotate_odd_sin_val_in[4]
  PIN ra_rotate_odd_sin_val_in[5]
    DIRECTION INPUT ;
    USE SIGNAL ;
    PORT
      LAYER met3 ;
        RECT  0 1794.03 0.8 1794.33 ;
    END
  END ra_rotate_odd_sin_val_in[5]
  PIN ra_rotate_odd_sin_val_in[6]
    DIRECTION INPUT ;
    USE SIGNAL ;
    PORT
      LAYER met3 ;
        RECT  0 1693.39 0.8 1693.69 ;
    END
  END ra_rotate_odd_sin_val_in[6]
  PIN ra_rotate_odd_sin_val_in[7]
    DIRECTION INPUT ;
    USE SIGNAL ;
    PORT
      LAYER met3 ;
        RECT  0 1640.35 0.8 1640.65 ;
    END
  END ra_rotate_odd_sin_val_in[7]
  PIN ra_rotate_odd_sin_val_in[8]
    DIRECTION INPUT ;
    USE SIGNAL ;
    PORT
      LAYER met3 ;
        RECT  0 1645.79 0.8 1646.09 ;
    END
  END ra_rotate_odd_sin_val_in[8]
  PIN ra_rotate_odd_sin_val_in[9]
    DIRECTION INPUT ;
    USE SIGNAL ;
    PORT
      LAYER met3 ;
        RECT  0 1629.47 0.8 1629.77 ;
    END
  END ra_rotate_odd_sin_val_in[9]
  PIN ra_rotate_odd_valid_in
    DIRECTION INPUT ;
    USE SIGNAL ;
    PORT
      LAYER met3 ;
        RECT  2999.2 1519.31 3000 1519.61 ;
    END
  END ra_rotate_odd_valid_in
  PIN ra_rotate_odd_x_even_in[0]
    DIRECTION INPUT ;
    USE SIGNAL ;
    PORT
      LAYER met3 ;
        RECT  0 1697.47 0.8 1697.77 ;
    END
  END ra_rotate_odd_x_even_in[0]
  PIN ra_rotate_odd_x_even_in[10]
    DIRECTION INPUT ;
    USE SIGNAL ;
    PORT
      LAYER met3 ;
        RECT  0 1619.95 0.8 1620.25 ;
    END
  END ra_rotate_odd_x_even_in[10]
  PIN ra_rotate_odd_x_even_in[11]
    DIRECTION INPUT ;
    USE SIGNAL ;
    PORT
      LAYER met3 ;
        RECT  0 1602.27 0.8 1602.57 ;
    END
  END ra_rotate_odd_x_even_in[11]
  PIN ra_rotate_odd_x_even_in[12]
    DIRECTION INPUT ;
    USE SIGNAL ;
    PORT
      LAYER met3 ;
        RECT  0 1599.55 0.8 1599.85 ;
    END
  END ra_rotate_odd_x_even_in[12]
  PIN ra_rotate_odd_x_even_in[13]
    DIRECTION INPUT ;
    USE SIGNAL ;
    PORT
      LAYER met3 ;
        RECT  0 1591.39 0.8 1591.69 ;
    END
  END ra_rotate_odd_x_even_in[13]
  PIN ra_rotate_odd_x_even_in[14]
    DIRECTION INPUT ;
    USE SIGNAL ;
    PORT
      LAYER met3 ;
        RECT  0 1575.07 0.8 1575.37 ;
    END
  END ra_rotate_odd_x_even_in[14]
  PIN ra_rotate_odd_x_even_in[15]
    DIRECTION INPUT ;
    USE SIGNAL ;
    PORT
      LAYER met3 ;
        RECT  0 1539.71 0.8 1540.01 ;
    END
  END ra_rotate_odd_x_even_in[15]
  PIN ra_rotate_odd_x_even_in[1]
    DIRECTION INPUT ;
    USE SIGNAL ;
    PORT
      LAYER met3 ;
        RECT  0 1698.83 0.8 1699.13 ;
    END
  END ra_rotate_odd_x_even_in[1]
  PIN ra_rotate_odd_x_even_in[2]
    DIRECTION INPUT ;
    USE SIGNAL ;
    PORT
      LAYER met3 ;
        RECT  0 1708.35 0.8 1708.65 ;
    END
  END ra_rotate_odd_x_even_in[2]
  PIN ra_rotate_odd_x_even_in[3]
    DIRECTION INPUT ;
    USE SIGNAL ;
    PORT
      LAYER met3 ;
        RECT  0 1728.75 0.8 1729.05 ;
    END
  END ra_rotate_odd_x_even_in[3]
  PIN ra_rotate_odd_x_even_in[4]
    DIRECTION INPUT ;
    USE SIGNAL ;
    PORT
      LAYER met3 ;
        RECT  0 1749.15 0.8 1749.45 ;
    END
  END ra_rotate_odd_x_even_in[4]
  PIN ra_rotate_odd_x_even_in[5]
    DIRECTION INPUT ;
    USE SIGNAL ;
    PORT
      LAYER met3 ;
        RECT  0 1758.67 0.8 1758.97 ;
    END
  END ra_rotate_odd_x_even_in[5]
  PIN ra_rotate_odd_x_even_in[6]
    DIRECTION INPUT ;
    USE SIGNAL ;
    PORT
      LAYER met3 ;
        RECT  0 1783.15 0.8 1783.45 ;
    END
  END ra_rotate_odd_x_even_in[6]
  PIN ra_rotate_odd_x_even_in[7]
    DIRECTION INPUT ;
    USE SIGNAL ;
    PORT
      LAYER met3 ;
        RECT  0 1638.99 0.8 1639.29 ;
    END
  END ra_rotate_odd_x_even_in[7]
  PIN ra_rotate_odd_x_even_in[8]
    DIRECTION INPUT ;
    USE SIGNAL ;
    PORT
      LAYER met3 ;
        RECT  0 1644.43 0.8 1644.73 ;
    END
  END ra_rotate_odd_x_even_in[8]
  PIN ra_rotate_odd_x_even_in[9]
    DIRECTION INPUT ;
    USE SIGNAL ;
    PORT
      LAYER met3 ;
        RECT  0 1628.11 0.8 1628.41 ;
    END
  END ra_rotate_odd_x_even_in[9]
  PIN ra_rotate_odd_x_odd_in[0]
    DIRECTION INPUT ;
    USE SIGNAL ;
    PORT
      LAYER met3 ;
        RECT  0 1653.95 0.8 1654.25 ;
    END
  END ra_rotate_odd_x_odd_in[0]
  PIN ra_rotate_odd_x_odd_in[10]
    DIRECTION INPUT ;
    USE SIGNAL ;
    PORT
      LAYER met3 ;
        RECT  0 1522.03 0.8 1522.33 ;
    END
  END ra_rotate_odd_x_odd_in[10]
  PIN ra_rotate_odd_x_odd_in[11]
    DIRECTION INPUT ;
    USE SIGNAL ;
    PORT
      LAYER met3 ;
        RECT  0 1502.99 0.8 1503.29 ;
    END
  END ra_rotate_odd_x_odd_in[11]
  PIN ra_rotate_odd_x_odd_in[12]
    DIRECTION INPUT ;
    USE SIGNAL ;
    PORT
      LAYER met3 ;
        RECT  0 1498.91 0.8 1499.21 ;
    END
  END ra_rotate_odd_x_odd_in[12]
  PIN ra_rotate_odd_x_odd_in[13]
    DIRECTION INPUT ;
    USE SIGNAL ;
    PORT
      LAYER met3 ;
        RECT  0 1486.67 0.8 1486.97 ;
    END
  END ra_rotate_odd_x_odd_in[13]
  PIN ra_rotate_odd_x_odd_in[14]
    DIRECTION INPUT ;
    USE SIGNAL ;
    PORT
      LAYER met3 ;
        RECT  0 1479.87 0.8 1480.17 ;
    END
  END ra_rotate_odd_x_odd_in[14]
  PIN ra_rotate_odd_x_odd_in[15]
    DIRECTION INPUT ;
    USE SIGNAL ;
    PORT
      LAYER met3 ;
        RECT  0 1706.99 0.8 1707.29 ;
    END
  END ra_rotate_odd_x_odd_in[15]
  PIN ra_rotate_odd_x_odd_in[1]
    DIRECTION INPUT ;
    USE SIGNAL ;
    PORT
      LAYER met3 ;
        RECT  0 1648.51 0.8 1648.81 ;
    END
  END ra_rotate_odd_x_odd_in[1]
  PIN ra_rotate_odd_x_odd_in[2]
    DIRECTION INPUT ;
    USE SIGNAL ;
    PORT
      LAYER met3 ;
        RECT  0 1618.59 0.8 1618.89 ;
    END
  END ra_rotate_odd_x_odd_in[2]
  PIN ra_rotate_odd_x_odd_in[3]
    DIRECTION INPUT ;
    USE SIGNAL ;
    PORT
      LAYER met3 ;
        RECT  0 1610.43 0.8 1610.73 ;
    END
  END ra_rotate_odd_x_odd_in[3]
  PIN ra_rotate_odd_x_odd_in[4]
    DIRECTION INPUT ;
    USE SIGNAL ;
    PORT
      LAYER met3 ;
        RECT  0 1588.67 0.8 1588.97 ;
    END
  END ra_rotate_odd_x_odd_in[4]
  PIN ra_rotate_odd_x_odd_in[5]
    DIRECTION INPUT ;
    USE SIGNAL ;
    PORT
      LAYER met3 ;
        RECT  0 1568.27 0.8 1568.57 ;
    END
  END ra_rotate_odd_x_odd_in[5]
  PIN ra_rotate_odd_x_odd_in[6]
    DIRECTION INPUT ;
    USE SIGNAL ;
    PORT
      LAYER met3 ;
        RECT  0 1561.47 0.8 1561.77 ;
    END
  END ra_rotate_odd_x_odd_in[6]
  PIN ra_rotate_odd_x_odd_in[7]
    DIRECTION INPUT ;
    USE SIGNAL ;
    PORT
      LAYER met3 ;
        RECT  0 1526.11 0.8 1526.41 ;
    END
  END ra_rotate_odd_x_odd_in[7]
  PIN ra_rotate_odd_x_odd_in[8]
    DIRECTION INPUT ;
    USE SIGNAL ;
    PORT
      LAYER met3 ;
        RECT  0 1542.43 0.8 1542.73 ;
    END
  END ra_rotate_odd_x_odd_in[8]
  PIN ra_rotate_odd_x_odd_in[9]
    DIRECTION INPUT ;
    USE SIGNAL ;
    PORT
      LAYER met3 ;
        RECT  0 1519.31 0.8 1519.61 ;
    END
  END ra_rotate_odd_x_odd_in[9]
  PIN ra_rst_and_startup_done_out
    DIRECTION OUTPUT ;
    USE SIGNAL ;
    PORT
      LAYER met3 ;
        RECT  2999.2 1674.35 3000 1674.65 ;
    END
  END ra_rst_and_startup_done_out
  PIN rst
    DIRECTION INPUT ;
    USE SIGNAL ;
    PORT
      LAYER met3 ;
        RECT  2999.2 1678.43 3000 1678.73 ;
    END
  END rst
  PIN stall_rate_in[0]
    DIRECTION INPUT ;
    USE SIGNAL ;
    PORT
      LAYER met2 ;
        RECT  2 0 2.14 0.485 ;
    END
  END stall_rate_in[0]
  PIN stall_rate_in[1]
    DIRECTION INPUT ;
    USE SIGNAL ;
    PORT
      LAYER met2 ;
        RECT  2.92 0 3.06 0.485 ;
    END
  END stall_rate_in[1]
  PIN stall_rate_in[2]
    DIRECTION INPUT ;
    USE SIGNAL ;
    PORT
      LAYER met2 ;
        RECT  3.84 0 3.98 0.485 ;
    END
  END stall_rate_in[2]
  PIN stall_rate_valid_in
    DIRECTION INPUT ;
    USE SIGNAL ;
    PORT
      LAYER met2 ;
        RECT  4.76 0 4.9 0.485 ;
    END
  END stall_rate_valid_in
  PIN VSS
    DIRECTION INOUT ;
    USE GROUND ;
    PORT
      LAYER met5 ;
        RECT  10.12 3478.08 2990 3479.68 ;
        RECT  10.12 3450.88 2990 3452.48 ;
        RECT  10.12 3423.68 2990 3425.28 ;
        RECT  10.12 3396.48 2990 3398.08 ;
        RECT  10.12 3369.28 2990 3370.88 ;
        RECT  10.12 3342.08 2990 3343.68 ;
        RECT  10.12 3314.88 2990 3316.48 ;
        RECT  10.12 3287.68 2990 3289.28 ;
        RECT  10.12 3260.48 2990 3262.08 ;
        RECT  10.12 3233.28 2990 3234.88 ;
        RECT  10.12 3206.08 2990 3207.68 ;
        RECT  10.12 3178.88 2990 3180.48 ;
        RECT  10.12 3151.68 2990 3153.28 ;
        RECT  10.12 3124.48 2990 3126.08 ;
        RECT  10.12 3097.28 2990 3098.88 ;
        RECT  10.12 3070.08 2990 3071.68 ;
        RECT  10.12 3042.88 2990 3044.48 ;
        RECT  10.12 3015.68 2990 3017.28 ;
        RECT  10.12 2988.48 2990 2990.08 ;
        RECT  10.12 2961.28 2990 2962.88 ;
        RECT  10.12 2934.08 2990 2935.68 ;
        RECT  10.12 2906.88 2990 2908.48 ;
        RECT  10.12 2879.68 2990 2881.28 ;
        RECT  10.12 2852.48 2990 2854.08 ;
        RECT  10.12 2825.28 2990 2826.88 ;
        RECT  10.12 2798.08 2990 2799.68 ;
        RECT  10.12 2770.88 2990 2772.48 ;
        RECT  10.12 2743.68 2990 2745.28 ;
        RECT  10.12 2716.48 2990 2718.08 ;
        RECT  10.12 2689.28 2990 2690.88 ;
        RECT  10.12 2662.08 2990 2663.68 ;
        RECT  10.12 2634.88 2990 2636.48 ;
        RECT  10.12 2607.68 2990 2609.28 ;
        RECT  10.12 2580.48 2990 2582.08 ;
        RECT  10.12 2553.28 2990 2554.88 ;
        RECT  10.12 2526.08 2990 2527.68 ;
        RECT  10.12 2498.88 2990 2500.48 ;
        RECT  10.12 2471.68 2990 2473.28 ;
        RECT  10.12 2444.48 2990 2446.08 ;
        RECT  10.12 2417.28 2990 2418.88 ;
        RECT  10.12 2390.08 2990 2391.68 ;
        RECT  10.12 2362.88 2990 2364.48 ;
        RECT  10.12 2335.68 2990 2337.28 ;
        RECT  10.12 2308.48 2990 2310.08 ;
        RECT  10.12 2281.28 2990 2282.88 ;
        RECT  10.12 2254.08 2990 2255.68 ;
        RECT  10.12 2226.88 2990 2228.48 ;
        RECT  10.12 2199.68 2990 2201.28 ;
        RECT  10.12 2172.48 2990 2174.08 ;
        RECT  10.12 2145.28 2990 2146.88 ;
        RECT  10.12 2118.08 2990 2119.68 ;
        RECT  10.12 2090.88 2990 2092.48 ;
        RECT  10.12 2063.68 2990 2065.28 ;
        RECT  10.12 2036.48 2990 2038.08 ;
        RECT  10.12 2009.28 2990 2010.88 ;
        RECT  10.12 1982.08 2990 1983.68 ;
        RECT  10.12 1954.88 2990 1956.48 ;
        RECT  10.12 1927.68 2990 1929.28 ;
        RECT  10.12 1900.48 2990 1902.08 ;
        RECT  10.12 1873.28 2990 1874.88 ;
        RECT  10.12 1846.08 2990 1847.68 ;
        RECT  10.12 1818.88 2990 1820.48 ;
        RECT  10.12 1791.68 2990 1793.28 ;
        RECT  10.12 1764.48 2990 1766.08 ;
        RECT  10.12 1737.28 2990 1738.88 ;
        RECT  10.12 1710.08 2990 1711.68 ;
        RECT  10.12 1682.88 2990 1684.48 ;
        RECT  10.12 1655.68 2990 1657.28 ;
        RECT  10.12 1628.48 2990 1630.08 ;
        RECT  10.12 1601.28 2990 1602.88 ;
        RECT  10.12 1574.08 2990 1575.68 ;
        RECT  10.12 1546.88 2990 1548.48 ;
        RECT  10.12 1519.68 2990 1521.28 ;
        RECT  10.12 1492.48 2990 1494.08 ;
        RECT  10.12 1465.28 2990 1466.88 ;
        RECT  10.12 1438.08 2990 1439.68 ;
        RECT  10.12 1410.88 2990 1412.48 ;
        RECT  10.12 1383.68 2990 1385.28 ;
        RECT  10.12 1356.48 2990 1358.08 ;
        RECT  10.12 1329.28 2990 1330.88 ;
        RECT  10.12 1302.08 2990 1303.68 ;
        RECT  10.12 1274.88 2990 1276.48 ;
        RECT  10.12 1247.68 2990 1249.28 ;
        RECT  10.12 1220.48 2990 1222.08 ;
        RECT  10.12 1193.28 2990 1194.88 ;
        RECT  10.12 1166.08 2990 1167.68 ;
        RECT  10.12 1138.88 2990 1140.48 ;
        RECT  10.12 1111.68 2990 1113.28 ;
        RECT  10.12 1084.48 2990 1086.08 ;
        RECT  10.12 1057.28 2990 1058.88 ;
        RECT  10.12 1030.08 2990 1031.68 ;
        RECT  10.12 1002.88 2990 1004.48 ;
        RECT  10.12 975.68 2990 977.28 ;
        RECT  10.12 948.48 2990 950.08 ;
        RECT  10.12 921.28 2990 922.88 ;
        RECT  10.12 894.08 2990 895.68 ;
        RECT  10.12 866.88 2990 868.48 ;
        RECT  10.12 839.68 2990 841.28 ;
        RECT  10.12 812.48 2990 814.08 ;
        RECT  10.12 785.28 2990 786.88 ;
        RECT  10.12 758.08 2990 759.68 ;
        RECT  10.12 730.88 2990 732.48 ;
        RECT  10.12 703.68 2990 705.28 ;
        RECT  10.12 676.48 2990 678.08 ;
        RECT  10.12 649.28 2990 650.88 ;
        RECT  10.12 622.08 2990 623.68 ;
        RECT  10.12 594.88 2990 596.48 ;
        RECT  10.12 567.68 2990 569.28 ;
        RECT  10.12 540.48 2990 542.08 ;
        RECT  10.12 513.28 2990 514.88 ;
        RECT  10.12 486.08 2990 487.68 ;
        RECT  10.12 458.88 2990 460.48 ;
        RECT  10.12 431.68 2990 433.28 ;
        RECT  10.12 404.48 2990 406.08 ;
        RECT  10.12 377.28 2990 378.88 ;
        RECT  10.12 350.08 2990 351.68 ;
        RECT  10.12 322.88 2990 324.48 ;
        RECT  10.12 295.68 2990 297.28 ;
        RECT  10.12 268.48 2990 270.08 ;
        RECT  10.12 241.28 2990 242.88 ;
        RECT  10.12 214.08 2990 215.68 ;
        RECT  10.12 186.88 2990 188.48 ;
        RECT  10.12 159.68 2990 161.28 ;
        RECT  10.12 132.48 2990 134.08 ;
        RECT  10.12 105.28 2990 106.88 ;
        RECT  10.12 78.08 2990 79.68 ;
        RECT  10.12 50.88 2990 52.48 ;
        RECT  10.12 23.68 2990 25.28 ;
    END
  END VSS
  PIN VDD
    DIRECTION INOUT ;
    USE POWER ;
    PORT
      LAYER met5 ;
        RECT  10.12 3464.48 2990 3466.08 ;
        RECT  10.12 3437.28 2990 3438.88 ;
        RECT  10.12 3410.08 2990 3411.68 ;
        RECT  10.12 3382.88 2990 3384.48 ;
        RECT  10.12 3355.68 2990 3357.28 ;
        RECT  10.12 3328.48 2990 3330.08 ;
        RECT  10.12 3301.28 2990 3302.88 ;
        RECT  10.12 3274.08 2990 3275.68 ;
        RECT  10.12 3246.88 2990 3248.48 ;
        RECT  10.12 3219.68 2990 3221.28 ;
        RECT  10.12 3192.48 2990 3194.08 ;
        RECT  10.12 3165.28 2990 3166.88 ;
        RECT  10.12 3138.08 2990 3139.68 ;
        RECT  10.12 3110.88 2990 3112.48 ;
        RECT  10.12 3083.68 2990 3085.28 ;
        RECT  10.12 3056.48 2990 3058.08 ;
        RECT  10.12 3029.28 2990 3030.88 ;
        RECT  10.12 3002.08 2990 3003.68 ;
        RECT  10.12 2974.88 2990 2976.48 ;
        RECT  10.12 2947.68 2990 2949.28 ;
        RECT  10.12 2920.48 2990 2922.08 ;
        RECT  10.12 2893.28 2990 2894.88 ;
        RECT  10.12 2866.08 2990 2867.68 ;
        RECT  10.12 2838.88 2990 2840.48 ;
        RECT  10.12 2811.68 2990 2813.28 ;
        RECT  10.12 2784.48 2990 2786.08 ;
        RECT  10.12 2757.28 2990 2758.88 ;
        RECT  10.12 2730.08 2990 2731.68 ;
        RECT  10.12 2702.88 2990 2704.48 ;
        RECT  10.12 2675.68 2990 2677.28 ;
        RECT  10.12 2648.48 2990 2650.08 ;
        RECT  10.12 2621.28 2990 2622.88 ;
        RECT  10.12 2594.08 2990 2595.68 ;
        RECT  10.12 2566.88 2990 2568.48 ;
        RECT  10.12 2539.68 2990 2541.28 ;
        RECT  10.12 2512.48 2990 2514.08 ;
        RECT  10.12 2485.28 2990 2486.88 ;
        RECT  10.12 2458.08 2990 2459.68 ;
        RECT  10.12 2430.88 2990 2432.48 ;
        RECT  10.12 2403.68 2990 2405.28 ;
        RECT  10.12 2376.48 2990 2378.08 ;
        RECT  10.12 2349.28 2990 2350.88 ;
        RECT  10.12 2322.08 2990 2323.68 ;
        RECT  10.12 2294.88 2990 2296.48 ;
        RECT  10.12 2267.68 2990 2269.28 ;
        RECT  10.12 2240.48 2990 2242.08 ;
        RECT  10.12 2213.28 2990 2214.88 ;
        RECT  10.12 2186.08 2990 2187.68 ;
        RECT  10.12 2158.88 2990 2160.48 ;
        RECT  10.12 2131.68 2990 2133.28 ;
        RECT  10.12 2104.48 2990 2106.08 ;
        RECT  10.12 2077.28 2990 2078.88 ;
        RECT  10.12 2050.08 2990 2051.68 ;
        RECT  10.12 2022.88 2990 2024.48 ;
        RECT  10.12 1995.68 2990 1997.28 ;
        RECT  10.12 1968.48 2990 1970.08 ;
        RECT  10.12 1941.28 2990 1942.88 ;
        RECT  10.12 1914.08 2990 1915.68 ;
        RECT  10.12 1886.88 2990 1888.48 ;
        RECT  10.12 1859.68 2990 1861.28 ;
        RECT  10.12 1832.48 2990 1834.08 ;
        RECT  10.12 1805.28 2990 1806.88 ;
        RECT  10.12 1778.08 2990 1779.68 ;
        RECT  10.12 1750.88 2990 1752.48 ;
        RECT  10.12 1723.68 2990 1725.28 ;
        RECT  10.12 1696.48 2990 1698.08 ;
        RECT  10.12 1669.28 2990 1670.88 ;
        RECT  10.12 1642.08 2990 1643.68 ;
        RECT  10.12 1614.88 2990 1616.48 ;
        RECT  10.12 1587.68 2990 1589.28 ;
        RECT  10.12 1560.48 2990 1562.08 ;
        RECT  10.12 1533.28 2990 1534.88 ;
        RECT  10.12 1506.08 2990 1507.68 ;
        RECT  10.12 1478.88 2990 1480.48 ;
        RECT  10.12 1451.68 2990 1453.28 ;
        RECT  10.12 1424.48 2990 1426.08 ;
        RECT  10.12 1397.28 2990 1398.88 ;
        RECT  10.12 1370.08 2990 1371.68 ;
        RECT  10.12 1342.88 2990 1344.48 ;
        RECT  10.12 1315.68 2990 1317.28 ;
        RECT  10.12 1288.48 2990 1290.08 ;
        RECT  10.12 1261.28 2990 1262.88 ;
        RECT  10.12 1234.08 2990 1235.68 ;
        RECT  10.12 1206.88 2990 1208.48 ;
        RECT  10.12 1179.68 2990 1181.28 ;
        RECT  10.12 1152.48 2990 1154.08 ;
        RECT  10.12 1125.28 2990 1126.88 ;
        RECT  10.12 1098.08 2990 1099.68 ;
        RECT  10.12 1070.88 2990 1072.48 ;
        RECT  10.12 1043.68 2990 1045.28 ;
        RECT  10.12 1016.48 2990 1018.08 ;
        RECT  10.12 989.28 2990 990.88 ;
        RECT  10.12 962.08 2990 963.68 ;
        RECT  10.12 934.88 2990 936.48 ;
        RECT  10.12 907.68 2990 909.28 ;
        RECT  10.12 880.48 2990 882.08 ;
        RECT  10.12 853.28 2990 854.88 ;
        RECT  10.12 826.08 2990 827.68 ;
        RECT  10.12 798.88 2990 800.48 ;
        RECT  10.12 771.68 2990 773.28 ;
        RECT  10.12 744.48 2990 746.08 ;
        RECT  10.12 717.28 2990 718.88 ;
        RECT  10.12 690.08 2990 691.68 ;
        RECT  10.12 662.88 2990 664.48 ;
        RECT  10.12 635.68 2990 637.28 ;
        RECT  10.12 608.48 2990 610.08 ;
        RECT  10.12 581.28 2990 582.88 ;
        RECT  10.12 554.08 2990 555.68 ;
        RECT  10.12 526.88 2990 528.48 ;
        RECT  10.12 499.68 2990 501.28 ;
        RECT  10.12 472.48 2990 474.08 ;
        RECT  10.12 445.28 2990 446.88 ;
        RECT  10.12 418.08 2990 419.68 ;
        RECT  10.12 390.88 2990 392.48 ;
        RECT  10.12 363.68 2990 365.28 ;
        RECT  10.12 336.48 2990 338.08 ;
        RECT  10.12 309.28 2990 310.88 ;
        RECT  10.12 282.08 2990 283.68 ;
        RECT  10.12 254.88 2990 256.48 ;
        RECT  10.12 227.68 2990 229.28 ;
        RECT  10.12 200.48 2990 202.08 ;
        RECT  10.12 173.28 2990 174.88 ;
        RECT  10.12 146.08 2990 147.68 ;
        RECT  10.12 118.88 2990 120.48 ;
        RECT  10.12 91.68 2990 93.28 ;
        RECT  10.12 64.48 2990 66.08 ;
        RECT  10.12 37.28 2990 38.88 ;
    END
  END VDD
  OBS
    LAYER nwell ;
     RECT  0 0 3000 3500 ;
    LAYER pwell ;
     RECT  0 0 3000 3500 ;
    LAYER li1 ;
     RECT  0 0 3000 3500 ;
    LAYER met1 ;
     RECT  0 0 3000 3500 ;
    LAYER met2 ;
     RECT  0 0 3000 3500 ;
    LAYER met3 ;
     RECT  0 0 3000 3500 ;
    LAYER met4 ;
     RECT  0 0 3000 3500 ;
    LAYER met5 ;
     RECT  0 0 3000 3500 ;
  END
END transformer_layer_block
END LIBRARY
